VERSION 5.8 ;
BUSBITCHARS "[]" ;
DIVIDERCHAR "/" ;
UNITS
    DATABASE MICRONS 1000 ;
END UNITS

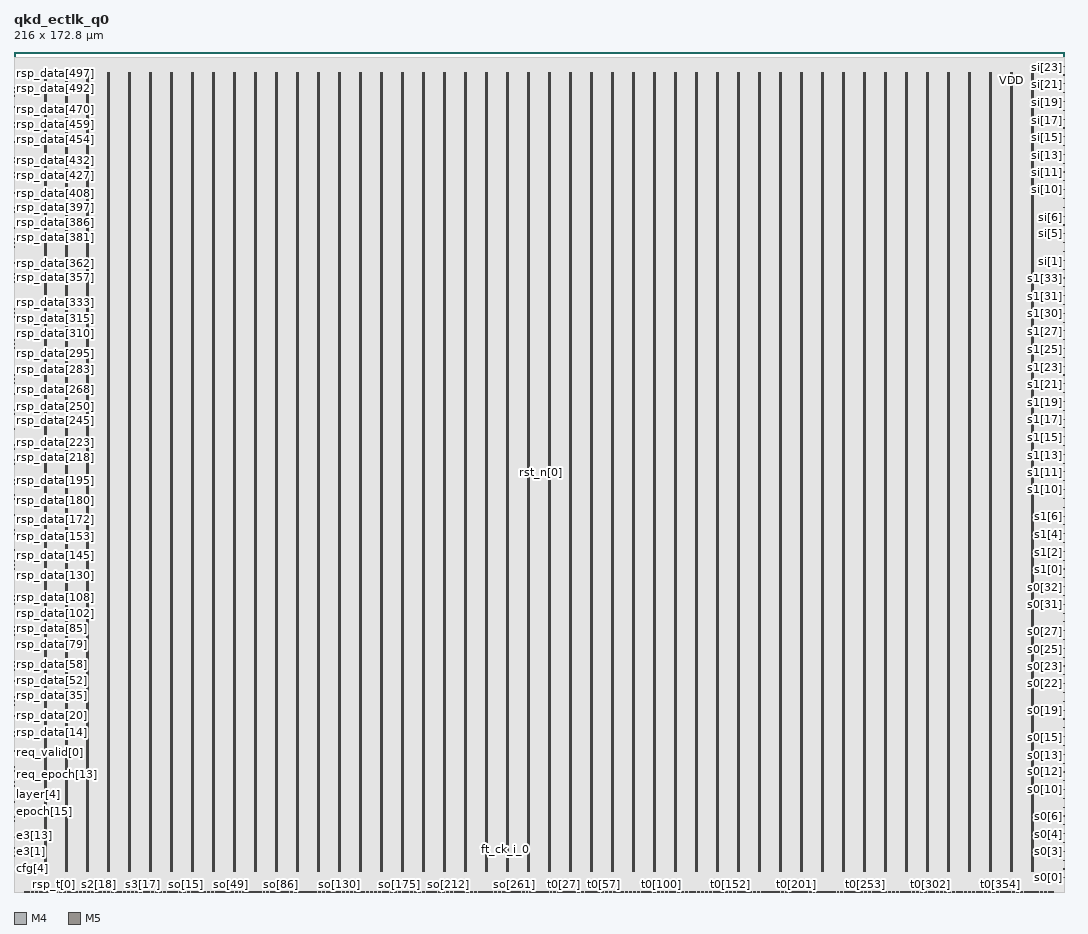
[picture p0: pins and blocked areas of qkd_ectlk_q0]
MACRO qkd_ectlk_q0
  FOREIGN qkd_ectlk_q0 0 0 ;
  CLASS BLOCK ;
  SIZE 216 BY 172.8 ;
  PIN cfg[0]
    DIRECTION INPUT ;
    USE SIGNAL ;
    PORT
      LAYER M4 ;
        RECT  0 2.124 0.192 2.148 ;
    END
  END cfg[0]
  PIN cfg[1]
    DIRECTION INPUT ;
    USE SIGNAL ;
    PORT
      LAYER M4 ;
        RECT  0 2.412 0.192 2.436 ;
    END
  END cfg[1]
  PIN cfg[2]
    DIRECTION INPUT ;
    USE SIGNAL ;
    PORT
      LAYER M4 ;
        RECT  0 2.7 0.192 2.724 ;
    END
  END cfg[2]
  PIN cfg[3]
    DIRECTION INPUT ;
    USE SIGNAL ;
    PORT
      LAYER M4 ;
        RECT  0 2.94 0.192 2.964 ;
    END
  END cfg[3]
  PIN cfg[4]
    DIRECTION INPUT ;
    USE SIGNAL ;
    PORT
      LAYER M4 ;
        RECT  0 3.228 0.192 3.252 ;
    END
  END cfg[4]
  PIN ck[0]
    DIRECTION INPUT ;
    USE SIGNAL ;
    PORT
      LAYER M5 ;
        RECT  108 86.16 108.048 86.64 ;
    END
  END ck[0]
  PIN e2[0]
    DIRECTION OUTPUT ;
    USE SIGNAL ;
    PORT
      LAYER M4 ;
        RECT  0 3.516 0.192 3.54 ;
    END
  END e2[0]
  PIN e2[10]
    DIRECTION OUTPUT ;
    USE SIGNAL ;
    PORT
      LAYER M4 ;
        RECT  0 6.3 0.192 6.324 ;
    END
  END e2[10]
  PIN e2[11]
    DIRECTION OUTPUT ;
    USE SIGNAL ;
    PORT
      LAYER M4 ;
        RECT  0 6.54 0.192 6.564 ;
    END
  END e2[11]
  PIN e2[12]
    DIRECTION OUTPUT ;
    USE SIGNAL ;
    PORT
      LAYER M4 ;
        RECT  0 6.828 0.192 6.852 ;
    END
  END e2[12]
  PIN e2[13]
    DIRECTION OUTPUT ;
    USE SIGNAL ;
    PORT
      LAYER M4 ;
        RECT  0 7.116 0.192 7.14 ;
    END
  END e2[13]
  PIN e2[14]
    DIRECTION OUTPUT ;
    USE SIGNAL ;
    PORT
      LAYER M4 ;
        RECT  0 7.404 0.192 7.428 ;
    END
  END e2[14]
  PIN e2[15]
    DIRECTION OUTPUT ;
    USE SIGNAL ;
    PORT
      LAYER M4 ;
        RECT  0 7.692 0.192 7.716 ;
    END
  END e2[15]
  PIN e2[1]
    DIRECTION OUTPUT ;
    USE SIGNAL ;
    PORT
      LAYER M4 ;
        RECT  0 3.804 0.192 3.828 ;
    END
  END e2[1]
  PIN e2[2]
    DIRECTION OUTPUT ;
    USE SIGNAL ;
    PORT
      LAYER M4 ;
        RECT  0 4.044 0.192 4.068 ;
    END
  END e2[2]
  PIN e2[3]
    DIRECTION OUTPUT ;
    USE SIGNAL ;
    PORT
      LAYER M4 ;
        RECT  0 4.332 0.192 4.356 ;
    END
  END e2[3]
  PIN e2[4]
    DIRECTION OUTPUT ;
    USE SIGNAL ;
    PORT
      LAYER M4 ;
        RECT  0 4.62 0.192 4.644 ;
    END
  END e2[4]
  PIN e2[5]
    DIRECTION OUTPUT ;
    USE SIGNAL ;
    PORT
      LAYER M4 ;
        RECT  0 4.908 0.192 4.932 ;
    END
  END e2[5]
  PIN e2[6]
    DIRECTION OUTPUT ;
    USE SIGNAL ;
    PORT
      LAYER M4 ;
        RECT  0 5.196 0.192 5.22 ;
    END
  END e2[6]
  PIN e2[7]
    DIRECTION OUTPUT ;
    USE SIGNAL ;
    PORT
      LAYER M4 ;
        RECT  0 5.436 0.192 5.46 ;
    END
  END e2[7]
  PIN e2[8]
    DIRECTION OUTPUT ;
    USE SIGNAL ;
    PORT
      LAYER M4 ;
        RECT  0 5.724 0.192 5.748 ;
    END
  END e2[8]
  PIN e2[9]
    DIRECTION OUTPUT ;
    USE SIGNAL ;
    PORT
      LAYER M4 ;
        RECT  0 6.012 0.192 6.036 ;
    END
  END e2[9]
  PIN e3[0]
    DIRECTION OUTPUT ;
    USE SIGNAL ;
    PORT
      LAYER M4 ;
        RECT  0 7.932 0.192 7.956 ;
    END
  END e3[0]
  PIN e3[10]
    DIRECTION OUTPUT ;
    USE SIGNAL ;
    PORT
      LAYER M4 ;
        RECT  0 10.716 0.192 10.74 ;
    END
  END e3[10]
  PIN e3[11]
    DIRECTION OUTPUT ;
    USE SIGNAL ;
    PORT
      LAYER M4 ;
        RECT  0 11.004 0.192 11.028 ;
    END
  END e3[11]
  PIN e3[12]
    DIRECTION OUTPUT ;
    USE SIGNAL ;
    PORT
      LAYER M4 ;
        RECT  0 11.292 0.192 11.316 ;
    END
  END e3[12]
  PIN e3[13]
    DIRECTION OUTPUT ;
    USE SIGNAL ;
    PORT
      LAYER M4 ;
        RECT  0 11.532 0.192 11.556 ;
    END
  END e3[13]
  PIN e3[14]
    DIRECTION OUTPUT ;
    USE SIGNAL ;
    PORT
      LAYER M4 ;
        RECT  0 11.82 0.192 11.844 ;
    END
  END e3[14]
  PIN e3[15]
    DIRECTION OUTPUT ;
    USE SIGNAL ;
    PORT
      LAYER M4 ;
        RECT  0 12.108 0.192 12.132 ;
    END
  END e3[15]
  PIN e3[1]
    DIRECTION OUTPUT ;
    USE SIGNAL ;
    PORT
      LAYER M4 ;
        RECT  0 8.22 0.192 8.244 ;
    END
  END e3[1]
  PIN e3[2]
    DIRECTION OUTPUT ;
    USE SIGNAL ;
    PORT
      LAYER M4 ;
        RECT  0 8.508 0.192 8.532 ;
    END
  END e3[2]
  PIN e3[3]
    DIRECTION OUTPUT ;
    USE SIGNAL ;
    PORT
      LAYER M4 ;
        RECT  0 8.796 0.192 8.82 ;
    END
  END e3[3]
  PIN e3[4]
    DIRECTION OUTPUT ;
    USE SIGNAL ;
    PORT
      LAYER M4 ;
        RECT  0 9.036 0.192 9.06 ;
    END
  END e3[4]
  PIN e3[5]
    DIRECTION OUTPUT ;
    USE SIGNAL ;
    PORT
      LAYER M4 ;
        RECT  0 9.324 0.192 9.348 ;
    END
  END e3[5]
  PIN e3[6]
    DIRECTION OUTPUT ;
    USE SIGNAL ;
    PORT
      LAYER M4 ;
        RECT  0 9.612 0.192 9.636 ;
    END
  END e3[6]
  PIN e3[7]
    DIRECTION OUTPUT ;
    USE SIGNAL ;
    PORT
      LAYER M4 ;
        RECT  0 9.9 0.192 9.924 ;
    END
  END e3[7]
  PIN e3[8]
    DIRECTION OUTPUT ;
    USE SIGNAL ;
    PORT
      LAYER M4 ;
        RECT  0 10.188 0.192 10.212 ;
    END
  END e3[8]
  PIN e3[9]
    DIRECTION OUTPUT ;
    USE SIGNAL ;
    PORT
      LAYER M4 ;
        RECT  0 10.428 0.192 10.452 ;
    END
  END e3[9]
  PIN epoch[0]
    DIRECTION INPUT ;
    USE SIGNAL ;
    PORT
      LAYER M4 ;
        RECT  0 12.396 0.192 12.42 ;
    END
  END epoch[0]
  PIN epoch[10]
    DIRECTION INPUT ;
    USE SIGNAL ;
    PORT
      LAYER M4 ;
        RECT  0 15.132 0.192 15.156 ;
    END
  END epoch[10]
  PIN epoch[11]
    DIRECTION INPUT ;
    USE SIGNAL ;
    PORT
      LAYER M4 ;
        RECT  0 15.42 0.192 15.444 ;
    END
  END epoch[11]
  PIN epoch[12]
    DIRECTION INPUT ;
    USE SIGNAL ;
    PORT
      LAYER M4 ;
        RECT  0 15.708 0.192 15.732 ;
    END
  END epoch[12]
  PIN epoch[13]
    DIRECTION INPUT ;
    USE SIGNAL ;
    PORT
      LAYER M4 ;
        RECT  0 15.996 0.192 16.02 ;
    END
  END epoch[13]
  PIN epoch[14]
    DIRECTION INPUT ;
    USE SIGNAL ;
    PORT
      LAYER M4 ;
        RECT  0 16.284 0.192 16.308 ;
    END
  END epoch[14]
  PIN epoch[15]
    DIRECTION INPUT ;
    USE SIGNAL ;
    PORT
      LAYER M4 ;
        RECT  0 16.524 0.192 16.548 ;
    END
  END epoch[15]
  PIN epoch[1]
    DIRECTION INPUT ;
    USE SIGNAL ;
    PORT
      LAYER M4 ;
        RECT  0 12.636 0.192 12.66 ;
    END
  END epoch[1]
  PIN epoch[2]
    DIRECTION INPUT ;
    USE SIGNAL ;
    PORT
      LAYER M4 ;
        RECT  0 12.924 0.192 12.948 ;
    END
  END epoch[2]
  PIN epoch[3]
    DIRECTION INPUT ;
    USE SIGNAL ;
    PORT
      LAYER M4 ;
        RECT  0 13.212 0.192 13.236 ;
    END
  END epoch[3]
  PIN epoch[4]
    DIRECTION INPUT ;
    USE SIGNAL ;
    PORT
      LAYER M4 ;
        RECT  0 13.5 0.192 13.524 ;
    END
  END epoch[4]
  PIN epoch[5]
    DIRECTION INPUT ;
    USE SIGNAL ;
    PORT
      LAYER M4 ;
        RECT  0 13.788 0.192 13.812 ;
    END
  END epoch[5]
  PIN epoch[6]
    DIRECTION INPUT ;
    USE SIGNAL ;
    PORT
      LAYER M4 ;
        RECT  0 14.028 0.192 14.052 ;
    END
  END epoch[6]
  PIN epoch[7]
    DIRECTION INPUT ;
    USE SIGNAL ;
    PORT
      LAYER M4 ;
        RECT  0 14.316 0.192 14.34 ;
    END
  END epoch[7]
  PIN epoch[8]
    DIRECTION INPUT ;
    USE SIGNAL ;
    PORT
      LAYER M4 ;
        RECT  0 14.604 0.192 14.628 ;
    END
  END epoch[8]
  PIN epoch[9]
    DIRECTION INPUT ;
    USE SIGNAL ;
    PORT
      LAYER M4 ;
        RECT  0 14.892 0.192 14.916 ;
    END
  END epoch[9]
  PIN fault[0]
    DIRECTION OUTPUT ;
    USE SIGNAL ;
    PORT
      LAYER M4 ;
        RECT  0 16.812 0.192 16.836 ;
    END
  END fault[0]
  PIN ft_ck_i_0
    DIRECTION INPUT ;
    USE SIGNAL ;
    PORT
      LAYER M5 ;
        RECT  101.04 8.535 101.088 9.015 ;
    END
  END ft_ck_i_0
  PIN ft_ck_o_0
    DIRECTION OUTPUT ;
    USE SIGNAL ;
    PORT
      LAYER M5 ;
        RECT  104.88 8.535 104.928 9.015 ;
    END
  END ft_ck_o_0
  PIN kgo[0]
    DIRECTION INPUT ;
    USE SIGNAL ;
    PORT
      LAYER M4 ;
        RECT  0 17.1 0.192 17.124 ;
    END
  END kgo[0]
  PIN layer[0]
    DIRECTION INPUT ;
    USE SIGNAL ;
    PORT
      LAYER M4 ;
        RECT  0 17.388 0.192 17.412 ;
    END
  END layer[0]
  PIN layer[1]
    DIRECTION INPUT ;
    USE SIGNAL ;
    PORT
      LAYER M4 ;
        RECT  0 17.628 0.192 17.652 ;
    END
  END layer[1]
  PIN layer[2]
    DIRECTION INPUT ;
    USE SIGNAL ;
    PORT
      LAYER M4 ;
        RECT  0 17.916 0.192 17.94 ;
    END
  END layer[2]
  PIN layer[3]
    DIRECTION INPUT ;
    USE SIGNAL ;
    PORT
      LAYER M4 ;
        RECT  0 18.204 0.192 18.228 ;
    END
  END layer[3]
  PIN layer[4]
    DIRECTION INPUT ;
    USE SIGNAL ;
    PORT
      LAYER M4 ;
        RECT  0 18.492 0.192 18.516 ;
    END
  END layer[4]
  PIN layer[5]
    DIRECTION INPUT ;
    USE SIGNAL ;
    PORT
      LAYER M4 ;
        RECT  0 18.78 0.192 18.804 ;
    END
  END layer[5]
  PIN req_epoch[0]
    DIRECTION OUTPUT ;
    USE SIGNAL ;
    PORT
      LAYER M4 ;
        RECT  0 19.02 0.192 19.044 ;
    END
  END req_epoch[0]
  PIN req_epoch[10]
    DIRECTION OUTPUT ;
    USE SIGNAL ;
    PORT
      LAYER M4 ;
        RECT  0 21.804 0.192 21.828 ;
    END
  END req_epoch[10]
  PIN req_epoch[11]
    DIRECTION OUTPUT ;
    USE SIGNAL ;
    PORT
      LAYER M4 ;
        RECT  0 22.092 0.192 22.116 ;
    END
  END req_epoch[11]
  PIN req_epoch[12]
    DIRECTION OUTPUT ;
    USE SIGNAL ;
    PORT
      LAYER M4 ;
        RECT  0 22.38 0.192 22.404 ;
    END
  END req_epoch[12]
  PIN req_epoch[13]
    DIRECTION OUTPUT ;
    USE SIGNAL ;
    PORT
      LAYER M4 ;
        RECT  0 22.62 0.192 22.644 ;
    END
  END req_epoch[13]
  PIN req_epoch[14]
    DIRECTION OUTPUT ;
    USE SIGNAL ;
    PORT
      LAYER M4 ;
        RECT  0 22.908 0.192 22.932 ;
    END
  END req_epoch[14]
  PIN req_epoch[15]
    DIRECTION OUTPUT ;
    USE SIGNAL ;
    PORT
      LAYER M4 ;
        RECT  0 23.196 0.192 23.22 ;
    END
  END req_epoch[15]
  PIN req_epoch[1]
    DIRECTION OUTPUT ;
    USE SIGNAL ;
    PORT
      LAYER M4 ;
        RECT  0 19.308 0.192 19.332 ;
    END
  END req_epoch[1]
  PIN req_epoch[2]
    DIRECTION OUTPUT ;
    USE SIGNAL ;
    PORT
      LAYER M4 ;
        RECT  0 19.596 0.192 19.62 ;
    END
  END req_epoch[2]
  PIN req_epoch[3]
    DIRECTION OUTPUT ;
    USE SIGNAL ;
    PORT
      LAYER M4 ;
        RECT  0 19.884 0.192 19.908 ;
    END
  END req_epoch[3]
  PIN req_epoch[4]
    DIRECTION OUTPUT ;
    USE SIGNAL ;
    PORT
      LAYER M4 ;
        RECT  0 20.124 0.192 20.148 ;
    END
  END req_epoch[4]
  PIN req_epoch[5]
    DIRECTION OUTPUT ;
    USE SIGNAL ;
    PORT
      LAYER M4 ;
        RECT  0 20.412 0.192 20.436 ;
    END
  END req_epoch[5]
  PIN req_epoch[6]
    DIRECTION OUTPUT ;
    USE SIGNAL ;
    PORT
      LAYER M4 ;
        RECT  0 20.7 0.192 20.724 ;
    END
  END req_epoch[6]
  PIN req_epoch[7]
    DIRECTION OUTPUT ;
    USE SIGNAL ;
    PORT
      LAYER M4 ;
        RECT  0 20.988 0.192 21.012 ;
    END
  END req_epoch[7]
  PIN req_epoch[8]
    DIRECTION OUTPUT ;
    USE SIGNAL ;
    PORT
      LAYER M4 ;
        RECT  0 21.228 0.192 21.252 ;
    END
  END req_epoch[8]
  PIN req_epoch[9]
    DIRECTION OUTPUT ;
    USE SIGNAL ;
    PORT
      LAYER M4 ;
        RECT  0 21.516 0.192 21.54 ;
    END
  END req_epoch[9]
  PIN req_layer[0]
    DIRECTION OUTPUT ;
    USE SIGNAL ;
    PORT
      LAYER M4 ;
        RECT  0 23.484 0.192 23.508 ;
    END
  END req_layer[0]
  PIN req_layer[1]
    DIRECTION OUTPUT ;
    USE SIGNAL ;
    PORT
      LAYER M4 ;
        RECT  0 23.724 0.192 23.748 ;
    END
  END req_layer[1]
  PIN req_layer[2]
    DIRECTION OUTPUT ;
    USE SIGNAL ;
    PORT
      LAYER M4 ;
        RECT  0 24.012 0.192 24.036 ;
    END
  END req_layer[2]
  PIN req_layer[3]
    DIRECTION OUTPUT ;
    USE SIGNAL ;
    PORT
      LAYER M4 ;
        RECT  0 24.3 0.192 24.324 ;
    END
  END req_layer[3]
  PIN req_layer[4]
    DIRECTION OUTPUT ;
    USE SIGNAL ;
    PORT
      LAYER M4 ;
        RECT  0 24.588 0.192 24.612 ;
    END
  END req_layer[4]
  PIN req_layer[5]
    DIRECTION OUTPUT ;
    USE SIGNAL ;
    PORT
      LAYER M4 ;
        RECT  0 24.876 0.192 24.9 ;
    END
  END req_layer[5]
  PIN req_t[0]
    DIRECTION OUTPUT ;
    USE SIGNAL ;
    PORT
      LAYER M4 ;
        RECT  0 25.116 0.192 25.14 ;
    END
  END req_t[0]
  PIN req_t[10]
    DIRECTION OUTPUT ;
    USE SIGNAL ;
    PORT
      LAYER M4 ;
        RECT  0 27.9 0.192 27.924 ;
    END
  END req_t[10]
  PIN req_t[11]
    DIRECTION OUTPUT ;
    USE SIGNAL ;
    PORT
      LAYER M4 ;
        RECT  0 28.188 0.192 28.212 ;
    END
  END req_t[11]
  PIN req_t[12]
    DIRECTION OUTPUT ;
    USE SIGNAL ;
    PORT
      LAYER M4 ;
        RECT  0 28.476 0.192 28.5 ;
    END
  END req_t[12]
  PIN req_t[1]
    DIRECTION OUTPUT ;
    USE SIGNAL ;
    PORT
      LAYER M4 ;
        RECT  0 25.404 0.192 25.428 ;
    END
  END req_t[1]
  PIN req_t[2]
    DIRECTION OUTPUT ;
    USE SIGNAL ;
    PORT
      LAYER M4 ;
        RECT  0 25.692 0.192 25.716 ;
    END
  END req_t[2]
  PIN req_t[3]
    DIRECTION OUTPUT ;
    USE SIGNAL ;
    PORT
      LAYER M4 ;
        RECT  0 25.98 0.192 26.004 ;
    END
  END req_t[3]
  PIN req_t[4]
    DIRECTION OUTPUT ;
    USE SIGNAL ;
    PORT
      LAYER M4 ;
        RECT  0 26.22 0.192 26.244 ;
    END
  END req_t[4]
  PIN req_t[5]
    DIRECTION OUTPUT ;
    USE SIGNAL ;
    PORT
      LAYER M4 ;
        RECT  0 26.508 0.192 26.532 ;
    END
  END req_t[5]
  PIN req_t[6]
    DIRECTION OUTPUT ;
    USE SIGNAL ;
    PORT
      LAYER M4 ;
        RECT  0 26.796 0.192 26.82 ;
    END
  END req_t[6]
  PIN req_t[7]
    DIRECTION OUTPUT ;
    USE SIGNAL ;
    PORT
      LAYER M4 ;
        RECT  0 27.084 0.192 27.108 ;
    END
  END req_t[7]
  PIN req_t[8]
    DIRECTION OUTPUT ;
    USE SIGNAL ;
    PORT
      LAYER M4 ;
        RECT  0 27.372 0.192 27.396 ;
    END
  END req_t[8]
  PIN req_t[9]
    DIRECTION OUTPUT ;
    USE SIGNAL ;
    PORT
      LAYER M4 ;
        RECT  0 27.612 0.192 27.636 ;
    END
  END req_t[9]
  PIN req_valid[0]
    DIRECTION OUTPUT ;
    USE SIGNAL ;
    PORT
      LAYER M4 ;
        RECT  0 28.716 0.192 28.74 ;
    END
  END req_valid[0]
  PIN rsp_data[0]
    DIRECTION INPUT ;
    USE SIGNAL ;
    PORT
      LAYER M4 ;
        RECT  0 29.004 0.192 29.028 ;
    END
  END rsp_data[0]
  PIN rsp_data[100]
    DIRECTION INPUT ;
    USE SIGNAL ;
    PORT
      LAYER M4 ;
        RECT  0 56.748 0.192 56.772 ;
    END
  END rsp_data[100]
  PIN rsp_data[101]
    DIRECTION INPUT ;
    USE SIGNAL ;
    PORT
      LAYER M4 ;
        RECT  0 56.988 0.192 57.012 ;
    END
  END rsp_data[101]
  PIN rsp_data[102]
    DIRECTION INPUT ;
    USE SIGNAL ;
    PORT
      LAYER M4 ;
        RECT  0 57.276 0.192 57.3 ;
    END
  END rsp_data[102]
  PIN rsp_data[103]
    DIRECTION INPUT ;
    USE SIGNAL ;
    PORT
      LAYER M4 ;
        RECT  0 57.564 0.192 57.588 ;
    END
  END rsp_data[103]
  PIN rsp_data[104]
    DIRECTION INPUT ;
    USE SIGNAL ;
    PORT
      LAYER M4 ;
        RECT  0 57.852 0.192 57.876 ;
    END
  END rsp_data[104]
  PIN rsp_data[105]
    DIRECTION INPUT ;
    USE SIGNAL ;
    PORT
      LAYER M4 ;
        RECT  0 58.14 0.192 58.164 ;
    END
  END rsp_data[105]
  PIN rsp_data[106]
    DIRECTION INPUT ;
    USE SIGNAL ;
    PORT
      LAYER M4 ;
        RECT  0 58.38 0.192 58.404 ;
    END
  END rsp_data[106]
  PIN rsp_data[107]
    DIRECTION INPUT ;
    USE SIGNAL ;
    PORT
      LAYER M4 ;
        RECT  0 58.668 0.192 58.692 ;
    END
  END rsp_data[107]
  PIN rsp_data[108]
    DIRECTION INPUT ;
    USE SIGNAL ;
    PORT
      LAYER M4 ;
        RECT  0 58.956 0.192 58.98 ;
    END
  END rsp_data[108]
  PIN rsp_data[109]
    DIRECTION INPUT ;
    USE SIGNAL ;
    PORT
      LAYER M4 ;
        RECT  0 59.244 0.192 59.268 ;
    END
  END rsp_data[109]
  PIN rsp_data[10]
    DIRECTION INPUT ;
    USE SIGNAL ;
    PORT
      LAYER M4 ;
        RECT  0 31.788 0.192 31.812 ;
    END
  END rsp_data[10]
  PIN rsp_data[110]
    DIRECTION INPUT ;
    USE SIGNAL ;
    PORT
      LAYER M4 ;
        RECT  0 59.484 0.192 59.508 ;
    END
  END rsp_data[110]
  PIN rsp_data[111]
    DIRECTION INPUT ;
    USE SIGNAL ;
    PORT
      LAYER M4 ;
        RECT  0 59.772 0.192 59.796 ;
    END
  END rsp_data[111]
  PIN rsp_data[112]
    DIRECTION INPUT ;
    USE SIGNAL ;
    PORT
      LAYER M4 ;
        RECT  0 60.06 0.192 60.084 ;
    END
  END rsp_data[112]
  PIN rsp_data[113]
    DIRECTION INPUT ;
    USE SIGNAL ;
    PORT
      LAYER M4 ;
        RECT  0 60.348 0.192 60.372 ;
    END
  END rsp_data[113]
  PIN rsp_data[114]
    DIRECTION INPUT ;
    USE SIGNAL ;
    PORT
      LAYER M4 ;
        RECT  0 60.588 0.192 60.612 ;
    END
  END rsp_data[114]
  PIN rsp_data[115]
    DIRECTION INPUT ;
    USE SIGNAL ;
    PORT
      LAYER M4 ;
        RECT  0 60.876 0.192 60.9 ;
    END
  END rsp_data[115]
  PIN rsp_data[116]
    DIRECTION INPUT ;
    USE SIGNAL ;
    PORT
      LAYER M4 ;
        RECT  0 61.164 0.192 61.188 ;
    END
  END rsp_data[116]
  PIN rsp_data[117]
    DIRECTION INPUT ;
    USE SIGNAL ;
    PORT
      LAYER M4 ;
        RECT  0 61.452 0.192 61.476 ;
    END
  END rsp_data[117]
  PIN rsp_data[118]
    DIRECTION INPUT ;
    USE SIGNAL ;
    PORT
      LAYER M4 ;
        RECT  0 61.74 0.192 61.764 ;
    END
  END rsp_data[118]
  PIN rsp_data[119]
    DIRECTION INPUT ;
    USE SIGNAL ;
    PORT
      LAYER M4 ;
        RECT  0 61.98 0.192 62.004 ;
    END
  END rsp_data[119]
  PIN rsp_data[11]
    DIRECTION INPUT ;
    USE SIGNAL ;
    PORT
      LAYER M4 ;
        RECT  0 32.076 0.192 32.1 ;
    END
  END rsp_data[11]
  PIN rsp_data[120]
    DIRECTION INPUT ;
    USE SIGNAL ;
    PORT
      LAYER M4 ;
        RECT  0 62.268 0.192 62.292 ;
    END
  END rsp_data[120]
  PIN rsp_data[121]
    DIRECTION INPUT ;
    USE SIGNAL ;
    PORT
      LAYER M4 ;
        RECT  0 62.556 0.192 62.58 ;
    END
  END rsp_data[121]
  PIN rsp_data[122]
    DIRECTION INPUT ;
    USE SIGNAL ;
    PORT
      LAYER M4 ;
        RECT  0 62.844 0.192 62.868 ;
    END
  END rsp_data[122]
  PIN rsp_data[123]
    DIRECTION INPUT ;
    USE SIGNAL ;
    PORT
      LAYER M4 ;
        RECT  0 63.084 0.192 63.108 ;
    END
  END rsp_data[123]
  PIN rsp_data[124]
    DIRECTION INPUT ;
    USE SIGNAL ;
    PORT
      LAYER M4 ;
        RECT  0 63.372 0.192 63.396 ;
    END
  END rsp_data[124]
  PIN rsp_data[125]
    DIRECTION INPUT ;
    USE SIGNAL ;
    PORT
      LAYER M4 ;
        RECT  0 63.66 0.192 63.684 ;
    END
  END rsp_data[125]
  PIN rsp_data[126]
    DIRECTION INPUT ;
    USE SIGNAL ;
    PORT
      LAYER M4 ;
        RECT  0 63.948 0.192 63.972 ;
    END
  END rsp_data[126]
  PIN rsp_data[127]
    DIRECTION INPUT ;
    USE SIGNAL ;
    PORT
      LAYER M4 ;
        RECT  0 64.236 0.192 64.26 ;
    END
  END rsp_data[127]
  PIN rsp_data[128]
    DIRECTION INPUT ;
    USE SIGNAL ;
    PORT
      LAYER M4 ;
        RECT  0 64.476 0.192 64.5 ;
    END
  END rsp_data[128]
  PIN rsp_data[129]
    DIRECTION INPUT ;
    USE SIGNAL ;
    PORT
      LAYER M4 ;
        RECT  0 64.764 0.192 64.788 ;
    END
  END rsp_data[129]
  PIN rsp_data[12]
    DIRECTION INPUT ;
    USE SIGNAL ;
    PORT
      LAYER M4 ;
        RECT  0 32.316 0.192 32.34 ;
    END
  END rsp_data[12]
  PIN rsp_data[130]
    DIRECTION INPUT ;
    USE SIGNAL ;
    PORT
      LAYER M4 ;
        RECT  0 65.052 0.192 65.076 ;
    END
  END rsp_data[130]
  PIN rsp_data[131]
    DIRECTION INPUT ;
    USE SIGNAL ;
    PORT
      LAYER M4 ;
        RECT  0 65.34 0.192 65.364 ;
    END
  END rsp_data[131]
  PIN rsp_data[132]
    DIRECTION INPUT ;
    USE SIGNAL ;
    PORT
      LAYER M4 ;
        RECT  0 65.58 0.192 65.604 ;
    END
  END rsp_data[132]
  PIN rsp_data[133]
    DIRECTION INPUT ;
    USE SIGNAL ;
    PORT
      LAYER M4 ;
        RECT  0 65.868 0.192 65.892 ;
    END
  END rsp_data[133]
  PIN rsp_data[134]
    DIRECTION INPUT ;
    USE SIGNAL ;
    PORT
      LAYER M4 ;
        RECT  0 66.156 0.192 66.18 ;
    END
  END rsp_data[134]
  PIN rsp_data[135]
    DIRECTION INPUT ;
    USE SIGNAL ;
    PORT
      LAYER M4 ;
        RECT  0 66.444 0.192 66.468 ;
    END
  END rsp_data[135]
  PIN rsp_data[136]
    DIRECTION INPUT ;
    USE SIGNAL ;
    PORT
      LAYER M4 ;
        RECT  0 66.732 0.192 66.756 ;
    END
  END rsp_data[136]
  PIN rsp_data[137]
    DIRECTION INPUT ;
    USE SIGNAL ;
    PORT
      LAYER M4 ;
        RECT  0 66.972 0.192 66.996 ;
    END
  END rsp_data[137]
  PIN rsp_data[138]
    DIRECTION INPUT ;
    USE SIGNAL ;
    PORT
      LAYER M4 ;
        RECT  0 67.26 0.192 67.284 ;
    END
  END rsp_data[138]
  PIN rsp_data[139]
    DIRECTION INPUT ;
    USE SIGNAL ;
    PORT
      LAYER M4 ;
        RECT  0 67.548 0.192 67.572 ;
    END
  END rsp_data[139]
  PIN rsp_data[13]
    DIRECTION INPUT ;
    USE SIGNAL ;
    PORT
      LAYER M4 ;
        RECT  0 32.604 0.192 32.628 ;
    END
  END rsp_data[13]
  PIN rsp_data[140]
    DIRECTION INPUT ;
    USE SIGNAL ;
    PORT
      LAYER M4 ;
        RECT  0 67.836 0.192 67.86 ;
    END
  END rsp_data[140]
  PIN rsp_data[141]
    DIRECTION INPUT ;
    USE SIGNAL ;
    PORT
      LAYER M4 ;
        RECT  0 68.076 0.192 68.1 ;
    END
  END rsp_data[141]
  PIN rsp_data[142]
    DIRECTION INPUT ;
    USE SIGNAL ;
    PORT
      LAYER M4 ;
        RECT  0 68.364 0.192 68.388 ;
    END
  END rsp_data[142]
  PIN rsp_data[143]
    DIRECTION INPUT ;
    USE SIGNAL ;
    PORT
      LAYER M4 ;
        RECT  0 68.652 0.192 68.676 ;
    END
  END rsp_data[143]
  PIN rsp_data[144]
    DIRECTION INPUT ;
    USE SIGNAL ;
    PORT
      LAYER M4 ;
        RECT  0 68.94 0.192 68.964 ;
    END
  END rsp_data[144]
  PIN rsp_data[145]
    DIRECTION INPUT ;
    USE SIGNAL ;
    PORT
      LAYER M4 ;
        RECT  0 69.18 0.192 69.204 ;
    END
  END rsp_data[145]
  PIN rsp_data[146]
    DIRECTION INPUT ;
    USE SIGNAL ;
    PORT
      LAYER M4 ;
        RECT  0 69.468 0.192 69.492 ;
    END
  END rsp_data[146]
  PIN rsp_data[147]
    DIRECTION INPUT ;
    USE SIGNAL ;
    PORT
      LAYER M4 ;
        RECT  0 69.756 0.192 69.78 ;
    END
  END rsp_data[147]
  PIN rsp_data[148]
    DIRECTION INPUT ;
    USE SIGNAL ;
    PORT
      LAYER M4 ;
        RECT  0 70.044 0.192 70.068 ;
    END
  END rsp_data[148]
  PIN rsp_data[149]
    DIRECTION INPUT ;
    USE SIGNAL ;
    PORT
      LAYER M4 ;
        RECT  0 70.332 0.192 70.356 ;
    END
  END rsp_data[149]
  PIN rsp_data[14]
    DIRECTION INPUT ;
    USE SIGNAL ;
    PORT
      LAYER M4 ;
        RECT  0 32.892 0.192 32.916 ;
    END
  END rsp_data[14]
  PIN rsp_data[150]
    DIRECTION INPUT ;
    USE SIGNAL ;
    PORT
      LAYER M4 ;
        RECT  0 70.572 0.192 70.596 ;
    END
  END rsp_data[150]
  PIN rsp_data[151]
    DIRECTION INPUT ;
    USE SIGNAL ;
    PORT
      LAYER M4 ;
        RECT  0 70.86 0.192 70.884 ;
    END
  END rsp_data[151]
  PIN rsp_data[152]
    DIRECTION INPUT ;
    USE SIGNAL ;
    PORT
      LAYER M4 ;
        RECT  0 71.148 0.192 71.172 ;
    END
  END rsp_data[152]
  PIN rsp_data[153]
    DIRECTION INPUT ;
    USE SIGNAL ;
    PORT
      LAYER M4 ;
        RECT  0 71.436 0.192 71.46 ;
    END
  END rsp_data[153]
  PIN rsp_data[154]
    DIRECTION INPUT ;
    USE SIGNAL ;
    PORT
      LAYER M4 ;
        RECT  0 71.676 0.192 71.7 ;
    END
  END rsp_data[154]
  PIN rsp_data[155]
    DIRECTION INPUT ;
    USE SIGNAL ;
    PORT
      LAYER M4 ;
        RECT  0 71.964 0.192 71.988 ;
    END
  END rsp_data[155]
  PIN rsp_data[156]
    DIRECTION INPUT ;
    USE SIGNAL ;
    PORT
      LAYER M4 ;
        RECT  0 72.252 0.192 72.276 ;
    END
  END rsp_data[156]
  PIN rsp_data[157]
    DIRECTION INPUT ;
    USE SIGNAL ;
    PORT
      LAYER M4 ;
        RECT  0 72.54 0.192 72.564 ;
    END
  END rsp_data[157]
  PIN rsp_data[158]
    DIRECTION INPUT ;
    USE SIGNAL ;
    PORT
      LAYER M4 ;
        RECT  0 72.828 0.192 72.852 ;
    END
  END rsp_data[158]
  PIN rsp_data[159]
    DIRECTION INPUT ;
    USE SIGNAL ;
    PORT
      LAYER M4 ;
        RECT  0 73.068 0.192 73.092 ;
    END
  END rsp_data[159]
  PIN rsp_data[15]
    DIRECTION INPUT ;
    USE SIGNAL ;
    PORT
      LAYER M4 ;
        RECT  0 33.18 0.192 33.204 ;
    END
  END rsp_data[15]
  PIN rsp_data[160]
    DIRECTION INPUT ;
    USE SIGNAL ;
    PORT
      LAYER M4 ;
        RECT  0 73.356 0.192 73.38 ;
    END
  END rsp_data[160]
  PIN rsp_data[161]
    DIRECTION INPUT ;
    USE SIGNAL ;
    PORT
      LAYER M4 ;
        RECT  0 73.644 0.192 73.668 ;
    END
  END rsp_data[161]
  PIN rsp_data[162]
    DIRECTION INPUT ;
    USE SIGNAL ;
    PORT
      LAYER M4 ;
        RECT  0 73.932 0.192 73.956 ;
    END
  END rsp_data[162]
  PIN rsp_data[163]
    DIRECTION INPUT ;
    USE SIGNAL ;
    PORT
      LAYER M4 ;
        RECT  0 74.172 0.192 74.196 ;
    END
  END rsp_data[163]
  PIN rsp_data[164]
    DIRECTION INPUT ;
    USE SIGNAL ;
    PORT
      LAYER M4 ;
        RECT  0 74.46 0.192 74.484 ;
    END
  END rsp_data[164]
  PIN rsp_data[165]
    DIRECTION INPUT ;
    USE SIGNAL ;
    PORT
      LAYER M4 ;
        RECT  0 74.748 0.192 74.772 ;
    END
  END rsp_data[165]
  PIN rsp_data[166]
    DIRECTION INPUT ;
    USE SIGNAL ;
    PORT
      LAYER M4 ;
        RECT  0 75.036 0.192 75.06 ;
    END
  END rsp_data[166]
  PIN rsp_data[167]
    DIRECTION INPUT ;
    USE SIGNAL ;
    PORT
      LAYER M4 ;
        RECT  0 75.324 0.192 75.348 ;
    END
  END rsp_data[167]
  PIN rsp_data[168]
    DIRECTION INPUT ;
    USE SIGNAL ;
    PORT
      LAYER M4 ;
        RECT  0 75.564 0.192 75.588 ;
    END
  END rsp_data[168]
  PIN rsp_data[169]
    DIRECTION INPUT ;
    USE SIGNAL ;
    PORT
      LAYER M4 ;
        RECT  0 75.852 0.192 75.876 ;
    END
  END rsp_data[169]
  PIN rsp_data[16]
    DIRECTION INPUT ;
    USE SIGNAL ;
    PORT
      LAYER M4 ;
        RECT  0 33.468 0.192 33.492 ;
    END
  END rsp_data[16]
  PIN rsp_data[170]
    DIRECTION INPUT ;
    USE SIGNAL ;
    PORT
      LAYER M4 ;
        RECT  0 76.14 0.192 76.164 ;
    END
  END rsp_data[170]
  PIN rsp_data[171]
    DIRECTION INPUT ;
    USE SIGNAL ;
    PORT
      LAYER M4 ;
        RECT  0 76.428 0.192 76.452 ;
    END
  END rsp_data[171]
  PIN rsp_data[172]
    DIRECTION INPUT ;
    USE SIGNAL ;
    PORT
      LAYER M4 ;
        RECT  0 76.668 0.192 76.692 ;
    END
  END rsp_data[172]
  PIN rsp_data[173]
    DIRECTION INPUT ;
    USE SIGNAL ;
    PORT
      LAYER M4 ;
        RECT  0 76.956 0.192 76.98 ;
    END
  END rsp_data[173]
  PIN rsp_data[174]
    DIRECTION INPUT ;
    USE SIGNAL ;
    PORT
      LAYER M4 ;
        RECT  0 77.244 0.192 77.268 ;
    END
  END rsp_data[174]
  PIN rsp_data[175]
    DIRECTION INPUT ;
    USE SIGNAL ;
    PORT
      LAYER M4 ;
        RECT  0 77.532 0.192 77.556 ;
    END
  END rsp_data[175]
  PIN rsp_data[176]
    DIRECTION INPUT ;
    USE SIGNAL ;
    PORT
      LAYER M4 ;
        RECT  0 77.772 0.192 77.796 ;
    END
  END rsp_data[176]
  PIN rsp_data[177]
    DIRECTION INPUT ;
    USE SIGNAL ;
    PORT
      LAYER M4 ;
        RECT  0 78.06 0.192 78.084 ;
    END
  END rsp_data[177]
  PIN rsp_data[178]
    DIRECTION INPUT ;
    USE SIGNAL ;
    PORT
      LAYER M4 ;
        RECT  0 78.348 0.192 78.372 ;
    END
  END rsp_data[178]
  PIN rsp_data[179]
    DIRECTION INPUT ;
    USE SIGNAL ;
    PORT
      LAYER M4 ;
        RECT  0 78.636 0.192 78.66 ;
    END
  END rsp_data[179]
  PIN rsp_data[17]
    DIRECTION INPUT ;
    USE SIGNAL ;
    PORT
      LAYER M4 ;
        RECT  0 33.708 0.192 33.732 ;
    END
  END rsp_data[17]
  PIN rsp_data[180]
    DIRECTION INPUT ;
    USE SIGNAL ;
    PORT
      LAYER M4 ;
        RECT  0 78.924 0.192 78.948 ;
    END
  END rsp_data[180]
  PIN rsp_data[181]
    DIRECTION INPUT ;
    USE SIGNAL ;
    PORT
      LAYER M4 ;
        RECT  0 79.164 0.192 79.188 ;
    END
  END rsp_data[181]
  PIN rsp_data[182]
    DIRECTION INPUT ;
    USE SIGNAL ;
    PORT
      LAYER M4 ;
        RECT  0 79.452 0.192 79.476 ;
    END
  END rsp_data[182]
  PIN rsp_data[183]
    DIRECTION INPUT ;
    USE SIGNAL ;
    PORT
      LAYER M4 ;
        RECT  0 79.74 0.192 79.764 ;
    END
  END rsp_data[183]
  PIN rsp_data[184]
    DIRECTION INPUT ;
    USE SIGNAL ;
    PORT
      LAYER M4 ;
        RECT  0 80.028 0.192 80.052 ;
    END
  END rsp_data[184]
  PIN rsp_data[185]
    DIRECTION INPUT ;
    USE SIGNAL ;
    PORT
      LAYER M4 ;
        RECT  0 80.268 0.192 80.292 ;
    END
  END rsp_data[185]
  PIN rsp_data[186]
    DIRECTION INPUT ;
    USE SIGNAL ;
    PORT
      LAYER M4 ;
        RECT  0 80.556 0.192 80.58 ;
    END
  END rsp_data[186]
  PIN rsp_data[187]
    DIRECTION INPUT ;
    USE SIGNAL ;
    PORT
      LAYER M4 ;
        RECT  0 80.844 0.192 80.868 ;
    END
  END rsp_data[187]
  PIN rsp_data[188]
    DIRECTION INPUT ;
    USE SIGNAL ;
    PORT
      LAYER M4 ;
        RECT  0 81.132 0.192 81.156 ;
    END
  END rsp_data[188]
  PIN rsp_data[189]
    DIRECTION INPUT ;
    USE SIGNAL ;
    PORT
      LAYER M4 ;
        RECT  0 81.42 0.192 81.444 ;
    END
  END rsp_data[189]
  PIN rsp_data[18]
    DIRECTION INPUT ;
    USE SIGNAL ;
    PORT
      LAYER M4 ;
        RECT  0 33.996 0.192 34.02 ;
    END
  END rsp_data[18]
  PIN rsp_data[190]
    DIRECTION INPUT ;
    USE SIGNAL ;
    PORT
      LAYER M4 ;
        RECT  0 81.66 0.192 81.684 ;
    END
  END rsp_data[190]
  PIN rsp_data[191]
    DIRECTION INPUT ;
    USE SIGNAL ;
    PORT
      LAYER M4 ;
        RECT  0 81.948 0.192 81.972 ;
    END
  END rsp_data[191]
  PIN rsp_data[192]
    DIRECTION INPUT ;
    USE SIGNAL ;
    PORT
      LAYER M4 ;
        RECT  0 82.236 0.192 82.26 ;
    END
  END rsp_data[192]
  PIN rsp_data[193]
    DIRECTION INPUT ;
    USE SIGNAL ;
    PORT
      LAYER M4 ;
        RECT  0 82.524 0.192 82.548 ;
    END
  END rsp_data[193]
  PIN rsp_data[194]
    DIRECTION INPUT ;
    USE SIGNAL ;
    PORT
      LAYER M4 ;
        RECT  0 82.764 0.192 82.788 ;
    END
  END rsp_data[194]
  PIN rsp_data[195]
    DIRECTION INPUT ;
    USE SIGNAL ;
    PORT
      LAYER M4 ;
        RECT  0 83.052 0.192 83.076 ;
    END
  END rsp_data[195]
  PIN rsp_data[196]
    DIRECTION INPUT ;
    USE SIGNAL ;
    PORT
      LAYER M4 ;
        RECT  0 83.34 0.192 83.364 ;
    END
  END rsp_data[196]
  PIN rsp_data[197]
    DIRECTION INPUT ;
    USE SIGNAL ;
    PORT
      LAYER M4 ;
        RECT  0 83.628 0.192 83.652 ;
    END
  END rsp_data[197]
  PIN rsp_data[198]
    DIRECTION INPUT ;
    USE SIGNAL ;
    PORT
      LAYER M4 ;
        RECT  0 83.916 0.192 83.94 ;
    END
  END rsp_data[198]
  PIN rsp_data[199]
    DIRECTION INPUT ;
    USE SIGNAL ;
    PORT
      LAYER M4 ;
        RECT  0 84.156 0.192 84.18 ;
    END
  END rsp_data[199]
  PIN rsp_data[19]
    DIRECTION INPUT ;
    USE SIGNAL ;
    PORT
      LAYER M4 ;
        RECT  0 34.284 0.192 34.308 ;
    END
  END rsp_data[19]
  PIN rsp_data[1]
    DIRECTION INPUT ;
    USE SIGNAL ;
    PORT
      LAYER M4 ;
        RECT  0 29.292 0.192 29.316 ;
    END
  END rsp_data[1]
  PIN rsp_data[200]
    DIRECTION INPUT ;
    USE SIGNAL ;
    PORT
      LAYER M4 ;
        RECT  0 84.444 0.192 84.468 ;
    END
  END rsp_data[200]
  PIN rsp_data[201]
    DIRECTION INPUT ;
    USE SIGNAL ;
    PORT
      LAYER M4 ;
        RECT  0 84.732 0.192 84.756 ;
    END
  END rsp_data[201]
  PIN rsp_data[202]
    DIRECTION INPUT ;
    USE SIGNAL ;
    PORT
      LAYER M4 ;
        RECT  0 85.02 0.192 85.044 ;
    END
  END rsp_data[202]
  PIN rsp_data[203]
    DIRECTION INPUT ;
    USE SIGNAL ;
    PORT
      LAYER M4 ;
        RECT  0 85.26 0.192 85.284 ;
    END
  END rsp_data[203]
  PIN rsp_data[204]
    DIRECTION INPUT ;
    USE SIGNAL ;
    PORT
      LAYER M4 ;
        RECT  0 85.548 0.192 85.572 ;
    END
  END rsp_data[204]
  PIN rsp_data[205]
    DIRECTION INPUT ;
    USE SIGNAL ;
    PORT
      LAYER M4 ;
        RECT  0 85.836 0.192 85.86 ;
    END
  END rsp_data[205]
  PIN rsp_data[206]
    DIRECTION INPUT ;
    USE SIGNAL ;
    PORT
      LAYER M4 ;
        RECT  0 86.124 0.192 86.148 ;
    END
  END rsp_data[206]
  PIN rsp_data[207]
    DIRECTION INPUT ;
    USE SIGNAL ;
    PORT
      LAYER M4 ;
        RECT  0 86.412 0.192 86.436 ;
    END
  END rsp_data[207]
  PIN rsp_data[208]
    DIRECTION INPUT ;
    USE SIGNAL ;
    PORT
      LAYER M4 ;
        RECT  0 86.652 0.192 86.676 ;
    END
  END rsp_data[208]
  PIN rsp_data[209]
    DIRECTION INPUT ;
    USE SIGNAL ;
    PORT
      LAYER M4 ;
        RECT  0 86.94 0.192 86.964 ;
    END
  END rsp_data[209]
  PIN rsp_data[20]
    DIRECTION INPUT ;
    USE SIGNAL ;
    PORT
      LAYER M4 ;
        RECT  0 34.572 0.192 34.596 ;
    END
  END rsp_data[20]
  PIN rsp_data[210]
    DIRECTION INPUT ;
    USE SIGNAL ;
    PORT
      LAYER M4 ;
        RECT  0 87.228 0.192 87.252 ;
    END
  END rsp_data[210]
  PIN rsp_data[211]
    DIRECTION INPUT ;
    USE SIGNAL ;
    PORT
      LAYER M4 ;
        RECT  0 87.516 0.192 87.54 ;
    END
  END rsp_data[211]
  PIN rsp_data[212]
    DIRECTION INPUT ;
    USE SIGNAL ;
    PORT
      LAYER M4 ;
        RECT  0 87.756 0.192 87.78 ;
    END
  END rsp_data[212]
  PIN rsp_data[213]
    DIRECTION INPUT ;
    USE SIGNAL ;
    PORT
      LAYER M4 ;
        RECT  0 88.044 0.192 88.068 ;
    END
  END rsp_data[213]
  PIN rsp_data[214]
    DIRECTION INPUT ;
    USE SIGNAL ;
    PORT
      LAYER M4 ;
        RECT  0 88.332 0.192 88.356 ;
    END
  END rsp_data[214]
  PIN rsp_data[215]
    DIRECTION INPUT ;
    USE SIGNAL ;
    PORT
      LAYER M4 ;
        RECT  0 88.62 0.192 88.644 ;
    END
  END rsp_data[215]
  PIN rsp_data[216]
    DIRECTION INPUT ;
    USE SIGNAL ;
    PORT
      LAYER M4 ;
        RECT  0 88.86 0.192 88.884 ;
    END
  END rsp_data[216]
  PIN rsp_data[217]
    DIRECTION INPUT ;
    USE SIGNAL ;
    PORT
      LAYER M4 ;
        RECT  0 89.148 0.192 89.172 ;
    END
  END rsp_data[217]
  PIN rsp_data[218]
    DIRECTION INPUT ;
    USE SIGNAL ;
    PORT
      LAYER M4 ;
        RECT  0 89.436 0.192 89.46 ;
    END
  END rsp_data[218]
  PIN rsp_data[219]
    DIRECTION INPUT ;
    USE SIGNAL ;
    PORT
      LAYER M4 ;
        RECT  0 89.724 0.192 89.748 ;
    END
  END rsp_data[219]
  PIN rsp_data[21]
    DIRECTION INPUT ;
    USE SIGNAL ;
    PORT
      LAYER M4 ;
        RECT  0 34.812 0.192 34.836 ;
    END
  END rsp_data[21]
  PIN rsp_data[220]
    DIRECTION INPUT ;
    USE SIGNAL ;
    PORT
      LAYER M4 ;
        RECT  0 90.012 0.192 90.036 ;
    END
  END rsp_data[220]
  PIN rsp_data[221]
    DIRECTION INPUT ;
    USE SIGNAL ;
    PORT
      LAYER M4 ;
        RECT  0 90.252 0.192 90.276 ;
    END
  END rsp_data[221]
  PIN rsp_data[222]
    DIRECTION INPUT ;
    USE SIGNAL ;
    PORT
      LAYER M4 ;
        RECT  0 90.54 0.192 90.564 ;
    END
  END rsp_data[222]
  PIN rsp_data[223]
    DIRECTION INPUT ;
    USE SIGNAL ;
    PORT
      LAYER M4 ;
        RECT  0 90.828 0.192 90.852 ;
    END
  END rsp_data[223]
  PIN rsp_data[224]
    DIRECTION INPUT ;
    USE SIGNAL ;
    PORT
      LAYER M4 ;
        RECT  0 91.116 0.192 91.14 ;
    END
  END rsp_data[224]
  PIN rsp_data[225]
    DIRECTION INPUT ;
    USE SIGNAL ;
    PORT
      LAYER M4 ;
        RECT  0 91.356 0.192 91.38 ;
    END
  END rsp_data[225]
  PIN rsp_data[226]
    DIRECTION INPUT ;
    USE SIGNAL ;
    PORT
      LAYER M4 ;
        RECT  0 91.644 0.192 91.668 ;
    END
  END rsp_data[226]
  PIN rsp_data[227]
    DIRECTION INPUT ;
    USE SIGNAL ;
    PORT
      LAYER M4 ;
        RECT  0 91.932 0.192 91.956 ;
    END
  END rsp_data[227]
  PIN rsp_data[228]
    DIRECTION INPUT ;
    USE SIGNAL ;
    PORT
      LAYER M4 ;
        RECT  0 92.22 0.192 92.244 ;
    END
  END rsp_data[228]
  PIN rsp_data[229]
    DIRECTION INPUT ;
    USE SIGNAL ;
    PORT
      LAYER M4 ;
        RECT  0 92.508 0.192 92.532 ;
    END
  END rsp_data[229]
  PIN rsp_data[22]
    DIRECTION INPUT ;
    USE SIGNAL ;
    PORT
      LAYER M4 ;
        RECT  0 35.1 0.192 35.124 ;
    END
  END rsp_data[22]
  PIN rsp_data[230]
    DIRECTION INPUT ;
    USE SIGNAL ;
    PORT
      LAYER M4 ;
        RECT  0 92.748 0.192 92.772 ;
    END
  END rsp_data[230]
  PIN rsp_data[231]
    DIRECTION INPUT ;
    USE SIGNAL ;
    PORT
      LAYER M4 ;
        RECT  0 93.036 0.192 93.06 ;
    END
  END rsp_data[231]
  PIN rsp_data[232]
    DIRECTION INPUT ;
    USE SIGNAL ;
    PORT
      LAYER M4 ;
        RECT  0 93.324 0.192 93.348 ;
    END
  END rsp_data[232]
  PIN rsp_data[233]
    DIRECTION INPUT ;
    USE SIGNAL ;
    PORT
      LAYER M4 ;
        RECT  0 93.612 0.192 93.636 ;
    END
  END rsp_data[233]
  PIN rsp_data[234]
    DIRECTION INPUT ;
    USE SIGNAL ;
    PORT
      LAYER M4 ;
        RECT  0 93.852 0.192 93.876 ;
    END
  END rsp_data[234]
  PIN rsp_data[235]
    DIRECTION INPUT ;
    USE SIGNAL ;
    PORT
      LAYER M4 ;
        RECT  0 94.14 0.192 94.164 ;
    END
  END rsp_data[235]
  PIN rsp_data[236]
    DIRECTION INPUT ;
    USE SIGNAL ;
    PORT
      LAYER M4 ;
        RECT  0 94.428 0.192 94.452 ;
    END
  END rsp_data[236]
  PIN rsp_data[237]
    DIRECTION INPUT ;
    USE SIGNAL ;
    PORT
      LAYER M4 ;
        RECT  0 94.716 0.192 94.74 ;
    END
  END rsp_data[237]
  PIN rsp_data[238]
    DIRECTION INPUT ;
    USE SIGNAL ;
    PORT
      LAYER M4 ;
        RECT  0 95.004 0.192 95.028 ;
    END
  END rsp_data[238]
  PIN rsp_data[239]
    DIRECTION INPUT ;
    USE SIGNAL ;
    PORT
      LAYER M4 ;
        RECT  0 95.244 0.192 95.268 ;
    END
  END rsp_data[239]
  PIN rsp_data[23]
    DIRECTION INPUT ;
    USE SIGNAL ;
    PORT
      LAYER M4 ;
        RECT  0 35.388 0.192 35.412 ;
    END
  END rsp_data[23]
  PIN rsp_data[240]
    DIRECTION INPUT ;
    USE SIGNAL ;
    PORT
      LAYER M4 ;
        RECT  0 95.532 0.192 95.556 ;
    END
  END rsp_data[240]
  PIN rsp_data[241]
    DIRECTION INPUT ;
    USE SIGNAL ;
    PORT
      LAYER M4 ;
        RECT  0 95.82 0.192 95.844 ;
    END
  END rsp_data[241]
  PIN rsp_data[242]
    DIRECTION INPUT ;
    USE SIGNAL ;
    PORT
      LAYER M4 ;
        RECT  0 96.108 0.192 96.132 ;
    END
  END rsp_data[242]
  PIN rsp_data[243]
    DIRECTION INPUT ;
    USE SIGNAL ;
    PORT
      LAYER M4 ;
        RECT  0 96.348 0.192 96.372 ;
    END
  END rsp_data[243]
  PIN rsp_data[244]
    DIRECTION INPUT ;
    USE SIGNAL ;
    PORT
      LAYER M4 ;
        RECT  0 96.636 0.192 96.66 ;
    END
  END rsp_data[244]
  PIN rsp_data[245]
    DIRECTION INPUT ;
    USE SIGNAL ;
    PORT
      LAYER M4 ;
        RECT  0 96.924 0.192 96.948 ;
    END
  END rsp_data[245]
  PIN rsp_data[246]
    DIRECTION INPUT ;
    USE SIGNAL ;
    PORT
      LAYER M4 ;
        RECT  0 97.212 0.192 97.236 ;
    END
  END rsp_data[246]
  PIN rsp_data[247]
    DIRECTION INPUT ;
    USE SIGNAL ;
    PORT
      LAYER M4 ;
        RECT  0 97.452 0.192 97.476 ;
    END
  END rsp_data[247]
  PIN rsp_data[248]
    DIRECTION INPUT ;
    USE SIGNAL ;
    PORT
      LAYER M4 ;
        RECT  0 97.74 0.192 97.764 ;
    END
  END rsp_data[248]
  PIN rsp_data[249]
    DIRECTION INPUT ;
    USE SIGNAL ;
    PORT
      LAYER M4 ;
        RECT  0 98.028 0.192 98.052 ;
    END
  END rsp_data[249]
  PIN rsp_data[24]
    DIRECTION INPUT ;
    USE SIGNAL ;
    PORT
      LAYER M4 ;
        RECT  0 35.676 0.192 35.7 ;
    END
  END rsp_data[24]
  PIN rsp_data[250]
    DIRECTION INPUT ;
    USE SIGNAL ;
    PORT
      LAYER M4 ;
        RECT  0 98.316 0.192 98.34 ;
    END
  END rsp_data[250]
  PIN rsp_data[251]
    DIRECTION INPUT ;
    USE SIGNAL ;
    PORT
      LAYER M4 ;
        RECT  0 98.604 0.192 98.628 ;
    END
  END rsp_data[251]
  PIN rsp_data[252]
    DIRECTION INPUT ;
    USE SIGNAL ;
    PORT
      LAYER M4 ;
        RECT  0 98.844 0.192 98.868 ;
    END
  END rsp_data[252]
  PIN rsp_data[253]
    DIRECTION INPUT ;
    USE SIGNAL ;
    PORT
      LAYER M4 ;
        RECT  0 99.132 0.192 99.156 ;
    END
  END rsp_data[253]
  PIN rsp_data[254]
    DIRECTION INPUT ;
    USE SIGNAL ;
    PORT
      LAYER M4 ;
        RECT  0 99.42 0.192 99.444 ;
    END
  END rsp_data[254]
  PIN rsp_data[255]
    DIRECTION INPUT ;
    USE SIGNAL ;
    PORT
      LAYER M4 ;
        RECT  0 99.708 0.192 99.732 ;
    END
  END rsp_data[255]
  PIN rsp_data[256]
    DIRECTION INPUT ;
    USE SIGNAL ;
    PORT
      LAYER M4 ;
        RECT  0 99.948 0.192 99.972 ;
    END
  END rsp_data[256]
  PIN rsp_data[257]
    DIRECTION INPUT ;
    USE SIGNAL ;
    PORT
      LAYER M4 ;
        RECT  0 100.236 0.192 100.26 ;
    END
  END rsp_data[257]
  PIN rsp_data[258]
    DIRECTION INPUT ;
    USE SIGNAL ;
    PORT
      LAYER M4 ;
        RECT  0 100.524 0.192 100.548 ;
    END
  END rsp_data[258]
  PIN rsp_data[259]
    DIRECTION INPUT ;
    USE SIGNAL ;
    PORT
      LAYER M4 ;
        RECT  0 100.812 0.192 100.836 ;
    END
  END rsp_data[259]
  PIN rsp_data[25]
    DIRECTION INPUT ;
    USE SIGNAL ;
    PORT
      LAYER M4 ;
        RECT  0 35.964 0.192 35.988 ;
    END
  END rsp_data[25]
  PIN rsp_data[260]
    DIRECTION INPUT ;
    USE SIGNAL ;
    PORT
      LAYER M4 ;
        RECT  0 101.1 0.192 101.124 ;
    END
  END rsp_data[260]
  PIN rsp_data[261]
    DIRECTION INPUT ;
    USE SIGNAL ;
    PORT
      LAYER M4 ;
        RECT  0 101.34 0.192 101.364 ;
    END
  END rsp_data[261]
  PIN rsp_data[262]
    DIRECTION INPUT ;
    USE SIGNAL ;
    PORT
      LAYER M4 ;
        RECT  0 101.628 0.192 101.652 ;
    END
  END rsp_data[262]
  PIN rsp_data[263]
    DIRECTION INPUT ;
    USE SIGNAL ;
    PORT
      LAYER M4 ;
        RECT  0 101.916 0.192 101.94 ;
    END
  END rsp_data[263]
  PIN rsp_data[264]
    DIRECTION INPUT ;
    USE SIGNAL ;
    PORT
      LAYER M4 ;
        RECT  0 102.204 0.192 102.228 ;
    END
  END rsp_data[264]
  PIN rsp_data[265]
    DIRECTION INPUT ;
    USE SIGNAL ;
    PORT
      LAYER M4 ;
        RECT  0 102.444 0.192 102.468 ;
    END
  END rsp_data[265]
  PIN rsp_data[266]
    DIRECTION INPUT ;
    USE SIGNAL ;
    PORT
      LAYER M4 ;
        RECT  0 102.732 0.192 102.756 ;
    END
  END rsp_data[266]
  PIN rsp_data[267]
    DIRECTION INPUT ;
    USE SIGNAL ;
    PORT
      LAYER M4 ;
        RECT  0 103.02 0.192 103.044 ;
    END
  END rsp_data[267]
  PIN rsp_data[268]
    DIRECTION INPUT ;
    USE SIGNAL ;
    PORT
      LAYER M4 ;
        RECT  0 103.308 0.192 103.332 ;
    END
  END rsp_data[268]
  PIN rsp_data[269]
    DIRECTION INPUT ;
    USE SIGNAL ;
    PORT
      LAYER M4 ;
        RECT  0 103.596 0.192 103.62 ;
    END
  END rsp_data[269]
  PIN rsp_data[26]
    DIRECTION INPUT ;
    USE SIGNAL ;
    PORT
      LAYER M4 ;
        RECT  0 36.204 0.192 36.228 ;
    END
  END rsp_data[26]
  PIN rsp_data[270]
    DIRECTION INPUT ;
    USE SIGNAL ;
    PORT
      LAYER M4 ;
        RECT  0 103.836 0.192 103.86 ;
    END
  END rsp_data[270]
  PIN rsp_data[271]
    DIRECTION INPUT ;
    USE SIGNAL ;
    PORT
      LAYER M4 ;
        RECT  0 104.124 0.192 104.148 ;
    END
  END rsp_data[271]
  PIN rsp_data[272]
    DIRECTION INPUT ;
    USE SIGNAL ;
    PORT
      LAYER M4 ;
        RECT  0 104.412 0.192 104.436 ;
    END
  END rsp_data[272]
  PIN rsp_data[273]
    DIRECTION INPUT ;
    USE SIGNAL ;
    PORT
      LAYER M4 ;
        RECT  0 104.7 0.192 104.724 ;
    END
  END rsp_data[273]
  PIN rsp_data[274]
    DIRECTION INPUT ;
    USE SIGNAL ;
    PORT
      LAYER M4 ;
        RECT  0 104.94 0.192 104.964 ;
    END
  END rsp_data[274]
  PIN rsp_data[275]
    DIRECTION INPUT ;
    USE SIGNAL ;
    PORT
      LAYER M4 ;
        RECT  0 105.228 0.192 105.252 ;
    END
  END rsp_data[275]
  PIN rsp_data[276]
    DIRECTION INPUT ;
    USE SIGNAL ;
    PORT
      LAYER M4 ;
        RECT  0 105.516 0.192 105.54 ;
    END
  END rsp_data[276]
  PIN rsp_data[277]
    DIRECTION INPUT ;
    USE SIGNAL ;
    PORT
      LAYER M4 ;
        RECT  0 105.804 0.192 105.828 ;
    END
  END rsp_data[277]
  PIN rsp_data[278]
    DIRECTION INPUT ;
    USE SIGNAL ;
    PORT
      LAYER M4 ;
        RECT  0 106.044 0.192 106.068 ;
    END
  END rsp_data[278]
  PIN rsp_data[279]
    DIRECTION INPUT ;
    USE SIGNAL ;
    PORT
      LAYER M4 ;
        RECT  0 106.332 0.192 106.356 ;
    END
  END rsp_data[279]
  PIN rsp_data[27]
    DIRECTION INPUT ;
    USE SIGNAL ;
    PORT
      LAYER M4 ;
        RECT  0 36.492 0.192 36.516 ;
    END
  END rsp_data[27]
  PIN rsp_data[280]
    DIRECTION INPUT ;
    USE SIGNAL ;
    PORT
      LAYER M4 ;
        RECT  0 106.62 0.192 106.644 ;
    END
  END rsp_data[280]
  PIN rsp_data[281]
    DIRECTION INPUT ;
    USE SIGNAL ;
    PORT
      LAYER M4 ;
        RECT  0 106.908 0.192 106.932 ;
    END
  END rsp_data[281]
  PIN rsp_data[282]
    DIRECTION INPUT ;
    USE SIGNAL ;
    PORT
      LAYER M4 ;
        RECT  0 107.196 0.192 107.22 ;
    END
  END rsp_data[282]
  PIN rsp_data[283]
    DIRECTION INPUT ;
    USE SIGNAL ;
    PORT
      LAYER M4 ;
        RECT  0 107.436 0.192 107.46 ;
    END
  END rsp_data[283]
  PIN rsp_data[284]
    DIRECTION INPUT ;
    USE SIGNAL ;
    PORT
      LAYER M4 ;
        RECT  0 107.724 0.192 107.748 ;
    END
  END rsp_data[284]
  PIN rsp_data[285]
    DIRECTION INPUT ;
    USE SIGNAL ;
    PORT
      LAYER M4 ;
        RECT  0 108.012 0.192 108.036 ;
    END
  END rsp_data[285]
  PIN rsp_data[286]
    DIRECTION INPUT ;
    USE SIGNAL ;
    PORT
      LAYER M4 ;
        RECT  0 108.3 0.192 108.324 ;
    END
  END rsp_data[286]
  PIN rsp_data[287]
    DIRECTION INPUT ;
    USE SIGNAL ;
    PORT
      LAYER M4 ;
        RECT  0 108.54 0.192 108.564 ;
    END
  END rsp_data[287]
  PIN rsp_data[288]
    DIRECTION INPUT ;
    USE SIGNAL ;
    PORT
      LAYER M4 ;
        RECT  0 108.828 0.192 108.852 ;
    END
  END rsp_data[288]
  PIN rsp_data[289]
    DIRECTION INPUT ;
    USE SIGNAL ;
    PORT
      LAYER M4 ;
        RECT  0 109.116 0.192 109.14 ;
    END
  END rsp_data[289]
  PIN rsp_data[28]
    DIRECTION INPUT ;
    USE SIGNAL ;
    PORT
      LAYER M4 ;
        RECT  0 36.78 0.192 36.804 ;
    END
  END rsp_data[28]
  PIN rsp_data[290]
    DIRECTION INPUT ;
    USE SIGNAL ;
    PORT
      LAYER M4 ;
        RECT  0 109.404 0.192 109.428 ;
    END
  END rsp_data[290]
  PIN rsp_data[291]
    DIRECTION INPUT ;
    USE SIGNAL ;
    PORT
      LAYER M4 ;
        RECT  0 109.692 0.192 109.716 ;
    END
  END rsp_data[291]
  PIN rsp_data[292]
    DIRECTION INPUT ;
    USE SIGNAL ;
    PORT
      LAYER M4 ;
        RECT  0 109.932 0.192 109.956 ;
    END
  END rsp_data[292]
  PIN rsp_data[293]
    DIRECTION INPUT ;
    USE SIGNAL ;
    PORT
      LAYER M4 ;
        RECT  0 110.22 0.192 110.244 ;
    END
  END rsp_data[293]
  PIN rsp_data[294]
    DIRECTION INPUT ;
    USE SIGNAL ;
    PORT
      LAYER M4 ;
        RECT  0 110.508 0.192 110.532 ;
    END
  END rsp_data[294]
  PIN rsp_data[295]
    DIRECTION INPUT ;
    USE SIGNAL ;
    PORT
      LAYER M4 ;
        RECT  0 110.796 0.192 110.82 ;
    END
  END rsp_data[295]
  PIN rsp_data[296]
    DIRECTION INPUT ;
    USE SIGNAL ;
    PORT
      LAYER M4 ;
        RECT  0 111.036 0.192 111.06 ;
    END
  END rsp_data[296]
  PIN rsp_data[297]
    DIRECTION INPUT ;
    USE SIGNAL ;
    PORT
      LAYER M4 ;
        RECT  0 111.324 0.192 111.348 ;
    END
  END rsp_data[297]
  PIN rsp_data[298]
    DIRECTION INPUT ;
    USE SIGNAL ;
    PORT
      LAYER M4 ;
        RECT  0 111.612 0.192 111.636 ;
    END
  END rsp_data[298]
  PIN rsp_data[299]
    DIRECTION INPUT ;
    USE SIGNAL ;
    PORT
      LAYER M4 ;
        RECT  0 111.9 0.192 111.924 ;
    END
  END rsp_data[299]
  PIN rsp_data[29]
    DIRECTION INPUT ;
    USE SIGNAL ;
    PORT
      LAYER M4 ;
        RECT  0 37.068 0.192 37.092 ;
    END
  END rsp_data[29]
  PIN rsp_data[2]
    DIRECTION INPUT ;
    USE SIGNAL ;
    PORT
      LAYER M4 ;
        RECT  0 29.58 0.192 29.604 ;
    END
  END rsp_data[2]
  PIN rsp_data[300]
    DIRECTION INPUT ;
    USE SIGNAL ;
    PORT
      LAYER M4 ;
        RECT  0 112.188 0.192 112.212 ;
    END
  END rsp_data[300]
  PIN rsp_data[301]
    DIRECTION INPUT ;
    USE SIGNAL ;
    PORT
      LAYER M4 ;
        RECT  0 112.428 0.192 112.452 ;
    END
  END rsp_data[301]
  PIN rsp_data[302]
    DIRECTION INPUT ;
    USE SIGNAL ;
    PORT
      LAYER M4 ;
        RECT  0 112.716 0.192 112.74 ;
    END
  END rsp_data[302]
  PIN rsp_data[303]
    DIRECTION INPUT ;
    USE SIGNAL ;
    PORT
      LAYER M4 ;
        RECT  0 113.004 0.192 113.028 ;
    END
  END rsp_data[303]
  PIN rsp_data[304]
    DIRECTION INPUT ;
    USE SIGNAL ;
    PORT
      LAYER M4 ;
        RECT  0 113.292 0.192 113.316 ;
    END
  END rsp_data[304]
  PIN rsp_data[305]
    DIRECTION INPUT ;
    USE SIGNAL ;
    PORT
      LAYER M4 ;
        RECT  0 113.532 0.192 113.556 ;
    END
  END rsp_data[305]
  PIN rsp_data[306]
    DIRECTION INPUT ;
    USE SIGNAL ;
    PORT
      LAYER M4 ;
        RECT  0 113.82 0.192 113.844 ;
    END
  END rsp_data[306]
  PIN rsp_data[307]
    DIRECTION INPUT ;
    USE SIGNAL ;
    PORT
      LAYER M4 ;
        RECT  0 114.108 0.192 114.132 ;
    END
  END rsp_data[307]
  PIN rsp_data[308]
    DIRECTION INPUT ;
    USE SIGNAL ;
    PORT
      LAYER M4 ;
        RECT  0 114.396 0.192 114.42 ;
    END
  END rsp_data[308]
  PIN rsp_data[309]
    DIRECTION INPUT ;
    USE SIGNAL ;
    PORT
      LAYER M4 ;
        RECT  0 114.636 0.192 114.66 ;
    END
  END rsp_data[309]
  PIN rsp_data[30]
    DIRECTION INPUT ;
    USE SIGNAL ;
    PORT
      LAYER M4 ;
        RECT  0 37.308 0.192 37.332 ;
    END
  END rsp_data[30]
  PIN rsp_data[310]
    DIRECTION INPUT ;
    USE SIGNAL ;
    PORT
      LAYER M4 ;
        RECT  0 114.924 0.192 114.948 ;
    END
  END rsp_data[310]
  PIN rsp_data[311]
    DIRECTION INPUT ;
    USE SIGNAL ;
    PORT
      LAYER M4 ;
        RECT  0 115.212 0.192 115.236 ;
    END
  END rsp_data[311]
  PIN rsp_data[312]
    DIRECTION INPUT ;
    USE SIGNAL ;
    PORT
      LAYER M4 ;
        RECT  0 115.5 0.192 115.524 ;
    END
  END rsp_data[312]
  PIN rsp_data[313]
    DIRECTION INPUT ;
    USE SIGNAL ;
    PORT
      LAYER M4 ;
        RECT  0 115.788 0.192 115.812 ;
    END
  END rsp_data[313]
  PIN rsp_data[314]
    DIRECTION INPUT ;
    USE SIGNAL ;
    PORT
      LAYER M4 ;
        RECT  0 116.028 0.192 116.052 ;
    END
  END rsp_data[314]
  PIN rsp_data[315]
    DIRECTION INPUT ;
    USE SIGNAL ;
    PORT
      LAYER M4 ;
        RECT  0 116.316 0.192 116.34 ;
    END
  END rsp_data[315]
  PIN rsp_data[316]
    DIRECTION INPUT ;
    USE SIGNAL ;
    PORT
      LAYER M4 ;
        RECT  0 116.604 0.192 116.628 ;
    END
  END rsp_data[316]
  PIN rsp_data[317]
    DIRECTION INPUT ;
    USE SIGNAL ;
    PORT
      LAYER M4 ;
        RECT  0 116.892 0.192 116.916 ;
    END
  END rsp_data[317]
  PIN rsp_data[318]
    DIRECTION INPUT ;
    USE SIGNAL ;
    PORT
      LAYER M4 ;
        RECT  0 117.132 0.192 117.156 ;
    END
  END rsp_data[318]
  PIN rsp_data[319]
    DIRECTION INPUT ;
    USE SIGNAL ;
    PORT
      LAYER M4 ;
        RECT  0 117.42 0.192 117.444 ;
    END
  END rsp_data[319]
  PIN rsp_data[31]
    DIRECTION INPUT ;
    USE SIGNAL ;
    PORT
      LAYER M4 ;
        RECT  0 37.596 0.192 37.62 ;
    END
  END rsp_data[31]
  PIN rsp_data[320]
    DIRECTION INPUT ;
    USE SIGNAL ;
    PORT
      LAYER M4 ;
        RECT  0 117.708 0.192 117.732 ;
    END
  END rsp_data[320]
  PIN rsp_data[321]
    DIRECTION INPUT ;
    USE SIGNAL ;
    PORT
      LAYER M4 ;
        RECT  0 117.996 0.192 118.02 ;
    END
  END rsp_data[321]
  PIN rsp_data[322]
    DIRECTION INPUT ;
    USE SIGNAL ;
    PORT
      LAYER M4 ;
        RECT  0 118.284 0.192 118.308 ;
    END
  END rsp_data[322]
  PIN rsp_data[323]
    DIRECTION INPUT ;
    USE SIGNAL ;
    PORT
      LAYER M4 ;
        RECT  0 118.524 0.192 118.548 ;
    END
  END rsp_data[323]
  PIN rsp_data[324]
    DIRECTION INPUT ;
    USE SIGNAL ;
    PORT
      LAYER M4 ;
        RECT  0 118.812 0.192 118.836 ;
    END
  END rsp_data[324]
  PIN rsp_data[325]
    DIRECTION INPUT ;
    USE SIGNAL ;
    PORT
      LAYER M4 ;
        RECT  0 119.1 0.192 119.124 ;
    END
  END rsp_data[325]
  PIN rsp_data[326]
    DIRECTION INPUT ;
    USE SIGNAL ;
    PORT
      LAYER M4 ;
        RECT  0 119.388 0.192 119.412 ;
    END
  END rsp_data[326]
  PIN rsp_data[327]
    DIRECTION INPUT ;
    USE SIGNAL ;
    PORT
      LAYER M4 ;
        RECT  0 119.628 0.192 119.652 ;
    END
  END rsp_data[327]
  PIN rsp_data[328]
    DIRECTION INPUT ;
    USE SIGNAL ;
    PORT
      LAYER M4 ;
        RECT  0 119.916 0.192 119.94 ;
    END
  END rsp_data[328]
  PIN rsp_data[329]
    DIRECTION INPUT ;
    USE SIGNAL ;
    PORT
      LAYER M4 ;
        RECT  0 120.204 0.192 120.228 ;
    END
  END rsp_data[329]
  PIN rsp_data[32]
    DIRECTION INPUT ;
    USE SIGNAL ;
    PORT
      LAYER M4 ;
        RECT  0 37.884 0.192 37.908 ;
    END
  END rsp_data[32]
  PIN rsp_data[330]
    DIRECTION INPUT ;
    USE SIGNAL ;
    PORT
      LAYER M4 ;
        RECT  0 120.492 0.192 120.516 ;
    END
  END rsp_data[330]
  PIN rsp_data[331]
    DIRECTION INPUT ;
    USE SIGNAL ;
    PORT
      LAYER M4 ;
        RECT  0 120.78 0.192 120.804 ;
    END
  END rsp_data[331]
  PIN rsp_data[332]
    DIRECTION INPUT ;
    USE SIGNAL ;
    PORT
      LAYER M4 ;
        RECT  0 121.02 0.192 121.044 ;
    END
  END rsp_data[332]
  PIN rsp_data[333]
    DIRECTION INPUT ;
    USE SIGNAL ;
    PORT
      LAYER M4 ;
        RECT  0 121.308 0.192 121.332 ;
    END
  END rsp_data[333]
  PIN rsp_data[334]
    DIRECTION INPUT ;
    USE SIGNAL ;
    PORT
      LAYER M4 ;
        RECT  0 121.596 0.192 121.62 ;
    END
  END rsp_data[334]
  PIN rsp_data[335]
    DIRECTION INPUT ;
    USE SIGNAL ;
    PORT
      LAYER M4 ;
        RECT  0 121.884 0.192 121.908 ;
    END
  END rsp_data[335]
  PIN rsp_data[336]
    DIRECTION INPUT ;
    USE SIGNAL ;
    PORT
      LAYER M4 ;
        RECT  0 122.124 0.192 122.148 ;
    END
  END rsp_data[336]
  PIN rsp_data[337]
    DIRECTION INPUT ;
    USE SIGNAL ;
    PORT
      LAYER M4 ;
        RECT  0 122.412 0.192 122.436 ;
    END
  END rsp_data[337]
  PIN rsp_data[338]
    DIRECTION INPUT ;
    USE SIGNAL ;
    PORT
      LAYER M4 ;
        RECT  0 122.7 0.192 122.724 ;
    END
  END rsp_data[338]
  PIN rsp_data[339]
    DIRECTION INPUT ;
    USE SIGNAL ;
    PORT
      LAYER M4 ;
        RECT  0 122.988 0.192 123.012 ;
    END
  END rsp_data[339]
  PIN rsp_data[33]
    DIRECTION INPUT ;
    USE SIGNAL ;
    PORT
      LAYER M4 ;
        RECT  0 38.172 0.192 38.196 ;
    END
  END rsp_data[33]
  PIN rsp_data[340]
    DIRECTION INPUT ;
    USE SIGNAL ;
    PORT
      LAYER M4 ;
        RECT  0 123.276 0.192 123.3 ;
    END
  END rsp_data[340]
  PIN rsp_data[341]
    DIRECTION INPUT ;
    USE SIGNAL ;
    PORT
      LAYER M4 ;
        RECT  0 123.516 0.192 123.54 ;
    END
  END rsp_data[341]
  PIN rsp_data[342]
    DIRECTION INPUT ;
    USE SIGNAL ;
    PORT
      LAYER M4 ;
        RECT  0 123.804 0.192 123.828 ;
    END
  END rsp_data[342]
  PIN rsp_data[343]
    DIRECTION INPUT ;
    USE SIGNAL ;
    PORT
      LAYER M4 ;
        RECT  0 124.092 0.192 124.116 ;
    END
  END rsp_data[343]
  PIN rsp_data[344]
    DIRECTION INPUT ;
    USE SIGNAL ;
    PORT
      LAYER M4 ;
        RECT  0 124.38 0.192 124.404 ;
    END
  END rsp_data[344]
  PIN rsp_data[345]
    DIRECTION INPUT ;
    USE SIGNAL ;
    PORT
      LAYER M4 ;
        RECT  0 124.62 0.192 124.644 ;
    END
  END rsp_data[345]
  PIN rsp_data[346]
    DIRECTION INPUT ;
    USE SIGNAL ;
    PORT
      LAYER M4 ;
        RECT  0 124.908 0.192 124.932 ;
    END
  END rsp_data[346]
  PIN rsp_data[347]
    DIRECTION INPUT ;
    USE SIGNAL ;
    PORT
      LAYER M4 ;
        RECT  0 125.196 0.192 125.22 ;
    END
  END rsp_data[347]
  PIN rsp_data[348]
    DIRECTION INPUT ;
    USE SIGNAL ;
    PORT
      LAYER M4 ;
        RECT  0 125.484 0.192 125.508 ;
    END
  END rsp_data[348]
  PIN rsp_data[349]
    DIRECTION INPUT ;
    USE SIGNAL ;
    PORT
      LAYER M4 ;
        RECT  0 125.724 0.192 125.748 ;
    END
  END rsp_data[349]
  PIN rsp_data[34]
    DIRECTION INPUT ;
    USE SIGNAL ;
    PORT
      LAYER M4 ;
        RECT  0 38.46 0.192 38.484 ;
    END
  END rsp_data[34]
  PIN rsp_data[350]
    DIRECTION INPUT ;
    USE SIGNAL ;
    PORT
      LAYER M4 ;
        RECT  0 126.012 0.192 126.036 ;
    END
  END rsp_data[350]
  PIN rsp_data[351]
    DIRECTION INPUT ;
    USE SIGNAL ;
    PORT
      LAYER M4 ;
        RECT  0 126.3 0.192 126.324 ;
    END
  END rsp_data[351]
  PIN rsp_data[352]
    DIRECTION INPUT ;
    USE SIGNAL ;
    PORT
      LAYER M4 ;
        RECT  0 126.588 0.192 126.612 ;
    END
  END rsp_data[352]
  PIN rsp_data[353]
    DIRECTION INPUT ;
    USE SIGNAL ;
    PORT
      LAYER M4 ;
        RECT  0 126.876 0.192 126.9 ;
    END
  END rsp_data[353]
  PIN rsp_data[354]
    DIRECTION INPUT ;
    USE SIGNAL ;
    PORT
      LAYER M4 ;
        RECT  0 127.116 0.192 127.14 ;
    END
  END rsp_data[354]
  PIN rsp_data[355]
    DIRECTION INPUT ;
    USE SIGNAL ;
    PORT
      LAYER M4 ;
        RECT  0 127.404 0.192 127.428 ;
    END
  END rsp_data[355]
  PIN rsp_data[356]
    DIRECTION INPUT ;
    USE SIGNAL ;
    PORT
      LAYER M4 ;
        RECT  0 127.692 0.192 127.716 ;
    END
  END rsp_data[356]
  PIN rsp_data[357]
    DIRECTION INPUT ;
    USE SIGNAL ;
    PORT
      LAYER M4 ;
        RECT  0 127.98 0.192 128.004 ;
    END
  END rsp_data[357]
  PIN rsp_data[358]
    DIRECTION INPUT ;
    USE SIGNAL ;
    PORT
      LAYER M4 ;
        RECT  0 128.22 0.192 128.244 ;
    END
  END rsp_data[358]
  PIN rsp_data[359]
    DIRECTION INPUT ;
    USE SIGNAL ;
    PORT
      LAYER M4 ;
        RECT  0 128.508 0.192 128.532 ;
    END
  END rsp_data[359]
  PIN rsp_data[35]
    DIRECTION INPUT ;
    USE SIGNAL ;
    PORT
      LAYER M4 ;
        RECT  0 38.7 0.192 38.724 ;
    END
  END rsp_data[35]
  PIN rsp_data[360]
    DIRECTION INPUT ;
    USE SIGNAL ;
    PORT
      LAYER M4 ;
        RECT  0 128.796 0.192 128.82 ;
    END
  END rsp_data[360]
  PIN rsp_data[361]
    DIRECTION INPUT ;
    USE SIGNAL ;
    PORT
      LAYER M4 ;
        RECT  0 129.084 0.192 129.108 ;
    END
  END rsp_data[361]
  PIN rsp_data[362]
    DIRECTION INPUT ;
    USE SIGNAL ;
    PORT
      LAYER M4 ;
        RECT  0 129.372 0.192 129.396 ;
    END
  END rsp_data[362]
  PIN rsp_data[363]
    DIRECTION INPUT ;
    USE SIGNAL ;
    PORT
      LAYER M4 ;
        RECT  0 129.612 0.192 129.636 ;
    END
  END rsp_data[363]
  PIN rsp_data[364]
    DIRECTION INPUT ;
    USE SIGNAL ;
    PORT
      LAYER M4 ;
        RECT  0 129.9 0.192 129.924 ;
    END
  END rsp_data[364]
  PIN rsp_data[365]
    DIRECTION INPUT ;
    USE SIGNAL ;
    PORT
      LAYER M4 ;
        RECT  0 130.188 0.192 130.212 ;
    END
  END rsp_data[365]
  PIN rsp_data[366]
    DIRECTION INPUT ;
    USE SIGNAL ;
    PORT
      LAYER M4 ;
        RECT  0 130.476 0.192 130.5 ;
    END
  END rsp_data[366]
  PIN rsp_data[367]
    DIRECTION INPUT ;
    USE SIGNAL ;
    PORT
      LAYER M4 ;
        RECT  0 130.716 0.192 130.74 ;
    END
  END rsp_data[367]
  PIN rsp_data[368]
    DIRECTION INPUT ;
    USE SIGNAL ;
    PORT
      LAYER M4 ;
        RECT  0 131.004 0.192 131.028 ;
    END
  END rsp_data[368]
  PIN rsp_data[369]
    DIRECTION INPUT ;
    USE SIGNAL ;
    PORT
      LAYER M4 ;
        RECT  0 131.292 0.192 131.316 ;
    END
  END rsp_data[369]
  PIN rsp_data[36]
    DIRECTION INPUT ;
    USE SIGNAL ;
    PORT
      LAYER M4 ;
        RECT  0 38.988 0.192 39.012 ;
    END
  END rsp_data[36]
  PIN rsp_data[370]
    DIRECTION INPUT ;
    USE SIGNAL ;
    PORT
      LAYER M4 ;
        RECT  0 131.58 0.192 131.604 ;
    END
  END rsp_data[370]
  PIN rsp_data[371]
    DIRECTION INPUT ;
    USE SIGNAL ;
    PORT
      LAYER M4 ;
        RECT  0 131.868 0.192 131.892 ;
    END
  END rsp_data[371]
  PIN rsp_data[372]
    DIRECTION INPUT ;
    USE SIGNAL ;
    PORT
      LAYER M4 ;
        RECT  0 132.108 0.192 132.132 ;
    END
  END rsp_data[372]
  PIN rsp_data[373]
    DIRECTION INPUT ;
    USE SIGNAL ;
    PORT
      LAYER M4 ;
        RECT  0 132.396 0.192 132.42 ;
    END
  END rsp_data[373]
  PIN rsp_data[374]
    DIRECTION INPUT ;
    USE SIGNAL ;
    PORT
      LAYER M4 ;
        RECT  0 132.684 0.192 132.708 ;
    END
  END rsp_data[374]
  PIN rsp_data[375]
    DIRECTION INPUT ;
    USE SIGNAL ;
    PORT
      LAYER M4 ;
        RECT  0 132.972 0.192 132.996 ;
    END
  END rsp_data[375]
  PIN rsp_data[376]
    DIRECTION INPUT ;
    USE SIGNAL ;
    PORT
      LAYER M4 ;
        RECT  0 133.212 0.192 133.236 ;
    END
  END rsp_data[376]
  PIN rsp_data[377]
    DIRECTION INPUT ;
    USE SIGNAL ;
    PORT
      LAYER M4 ;
        RECT  0 133.5 0.192 133.524 ;
    END
  END rsp_data[377]
  PIN rsp_data[378]
    DIRECTION INPUT ;
    USE SIGNAL ;
    PORT
      LAYER M4 ;
        RECT  0 133.788 0.192 133.812 ;
    END
  END rsp_data[378]
  PIN rsp_data[379]
    DIRECTION INPUT ;
    USE SIGNAL ;
    PORT
      LAYER M4 ;
        RECT  0 134.076 0.192 134.1 ;
    END
  END rsp_data[379]
  PIN rsp_data[37]
    DIRECTION INPUT ;
    USE SIGNAL ;
    PORT
      LAYER M4 ;
        RECT  0 39.276 0.192 39.3 ;
    END
  END rsp_data[37]
  PIN rsp_data[380]
    DIRECTION INPUT ;
    USE SIGNAL ;
    PORT
      LAYER M4 ;
        RECT  0 134.316 0.192 134.34 ;
    END
  END rsp_data[380]
  PIN rsp_data[381]
    DIRECTION INPUT ;
    USE SIGNAL ;
    PORT
      LAYER M4 ;
        RECT  0 134.604 0.192 134.628 ;
    END
  END rsp_data[381]
  PIN rsp_data[382]
    DIRECTION INPUT ;
    USE SIGNAL ;
    PORT
      LAYER M4 ;
        RECT  0 134.892 0.192 134.916 ;
    END
  END rsp_data[382]
  PIN rsp_data[383]
    DIRECTION INPUT ;
    USE SIGNAL ;
    PORT
      LAYER M4 ;
        RECT  0 135.18 0.192 135.204 ;
    END
  END rsp_data[383]
  PIN rsp_data[384]
    DIRECTION INPUT ;
    USE SIGNAL ;
    PORT
      LAYER M4 ;
        RECT  0 135.468 0.192 135.492 ;
    END
  END rsp_data[384]
  PIN rsp_data[385]
    DIRECTION INPUT ;
    USE SIGNAL ;
    PORT
      LAYER M4 ;
        RECT  0 135.708 0.192 135.732 ;
    END
  END rsp_data[385]
  PIN rsp_data[386]
    DIRECTION INPUT ;
    USE SIGNAL ;
    PORT
      LAYER M4 ;
        RECT  0 135.996 0.192 136.02 ;
    END
  END rsp_data[386]
  PIN rsp_data[387]
    DIRECTION INPUT ;
    USE SIGNAL ;
    PORT
      LAYER M4 ;
        RECT  0 136.284 0.192 136.308 ;
    END
  END rsp_data[387]
  PIN rsp_data[388]
    DIRECTION INPUT ;
    USE SIGNAL ;
    PORT
      LAYER M4 ;
        RECT  0 136.572 0.192 136.596 ;
    END
  END rsp_data[388]
  PIN rsp_data[389]
    DIRECTION INPUT ;
    USE SIGNAL ;
    PORT
      LAYER M4 ;
        RECT  0 136.812 0.192 136.836 ;
    END
  END rsp_data[389]
  PIN rsp_data[38]
    DIRECTION INPUT ;
    USE SIGNAL ;
    PORT
      LAYER M4 ;
        RECT  0 39.564 0.192 39.588 ;
    END
  END rsp_data[38]
  PIN rsp_data[390]
    DIRECTION INPUT ;
    USE SIGNAL ;
    PORT
      LAYER M4 ;
        RECT  0 137.1 0.192 137.124 ;
    END
  END rsp_data[390]
  PIN rsp_data[391]
    DIRECTION INPUT ;
    USE SIGNAL ;
    PORT
      LAYER M4 ;
        RECT  0 137.388 0.192 137.412 ;
    END
  END rsp_data[391]
  PIN rsp_data[392]
    DIRECTION INPUT ;
    USE SIGNAL ;
    PORT
      LAYER M4 ;
        RECT  0 137.676 0.192 137.7 ;
    END
  END rsp_data[392]
  PIN rsp_data[393]
    DIRECTION INPUT ;
    USE SIGNAL ;
    PORT
      LAYER M4 ;
        RECT  0 137.964 0.192 137.988 ;
    END
  END rsp_data[393]
  PIN rsp_data[394]
    DIRECTION INPUT ;
    USE SIGNAL ;
    PORT
      LAYER M4 ;
        RECT  0 138.204 0.192 138.228 ;
    END
  END rsp_data[394]
  PIN rsp_data[395]
    DIRECTION INPUT ;
    USE SIGNAL ;
    PORT
      LAYER M4 ;
        RECT  0 138.492 0.192 138.516 ;
    END
  END rsp_data[395]
  PIN rsp_data[396]
    DIRECTION INPUT ;
    USE SIGNAL ;
    PORT
      LAYER M4 ;
        RECT  0 138.78 0.192 138.804 ;
    END
  END rsp_data[396]
  PIN rsp_data[397]
    DIRECTION INPUT ;
    USE SIGNAL ;
    PORT
      LAYER M4 ;
        RECT  0 139.068 0.192 139.092 ;
    END
  END rsp_data[397]
  PIN rsp_data[398]
    DIRECTION INPUT ;
    USE SIGNAL ;
    PORT
      LAYER M4 ;
        RECT  0 139.308 0.192 139.332 ;
    END
  END rsp_data[398]
  PIN rsp_data[399]
    DIRECTION INPUT ;
    USE SIGNAL ;
    PORT
      LAYER M4 ;
        RECT  0 139.596 0.192 139.62 ;
    END
  END rsp_data[399]
  PIN rsp_data[39]
    DIRECTION INPUT ;
    USE SIGNAL ;
    PORT
      LAYER M4 ;
        RECT  0 39.804 0.192 39.828 ;
    END
  END rsp_data[39]
  PIN rsp_data[3]
    DIRECTION INPUT ;
    USE SIGNAL ;
    PORT
      LAYER M4 ;
        RECT  0 29.868 0.192 29.892 ;
    END
  END rsp_data[3]
  PIN rsp_data[400]
    DIRECTION INPUT ;
    USE SIGNAL ;
    PORT
      LAYER M4 ;
        RECT  0 139.884 0.192 139.908 ;
    END
  END rsp_data[400]
  PIN rsp_data[401]
    DIRECTION INPUT ;
    USE SIGNAL ;
    PORT
      LAYER M4 ;
        RECT  0 140.172 0.192 140.196 ;
    END
  END rsp_data[401]
  PIN rsp_data[402]
    DIRECTION INPUT ;
    USE SIGNAL ;
    PORT
      LAYER M4 ;
        RECT  0 140.46 0.192 140.484 ;
    END
  END rsp_data[402]
  PIN rsp_data[403]
    DIRECTION INPUT ;
    USE SIGNAL ;
    PORT
      LAYER M4 ;
        RECT  0 140.7 0.192 140.724 ;
    END
  END rsp_data[403]
  PIN rsp_data[404]
    DIRECTION INPUT ;
    USE SIGNAL ;
    PORT
      LAYER M4 ;
        RECT  0 140.988 0.192 141.012 ;
    END
  END rsp_data[404]
  PIN rsp_data[405]
    DIRECTION INPUT ;
    USE SIGNAL ;
    PORT
      LAYER M4 ;
        RECT  0 141.276 0.192 141.3 ;
    END
  END rsp_data[405]
  PIN rsp_data[406]
    DIRECTION INPUT ;
    USE SIGNAL ;
    PORT
      LAYER M4 ;
        RECT  0 141.564 0.192 141.588 ;
    END
  END rsp_data[406]
  PIN rsp_data[407]
    DIRECTION INPUT ;
    USE SIGNAL ;
    PORT
      LAYER M4 ;
        RECT  0 141.804 0.192 141.828 ;
    END
  END rsp_data[407]
  PIN rsp_data[408]
    DIRECTION INPUT ;
    USE SIGNAL ;
    PORT
      LAYER M4 ;
        RECT  0 142.092 0.192 142.116 ;
    END
  END rsp_data[408]
  PIN rsp_data[409]
    DIRECTION INPUT ;
    USE SIGNAL ;
    PORT
      LAYER M4 ;
        RECT  0 142.38 0.192 142.404 ;
    END
  END rsp_data[409]
  PIN rsp_data[40]
    DIRECTION INPUT ;
    USE SIGNAL ;
    PORT
      LAYER M4 ;
        RECT  0 40.092 0.192 40.116 ;
    END
  END rsp_data[40]
  PIN rsp_data[410]
    DIRECTION INPUT ;
    USE SIGNAL ;
    PORT
      LAYER M4 ;
        RECT  0 142.668 0.192 142.692 ;
    END
  END rsp_data[410]
  PIN rsp_data[411]
    DIRECTION INPUT ;
    USE SIGNAL ;
    PORT
      LAYER M4 ;
        RECT  0 142.908 0.192 142.932 ;
    END
  END rsp_data[411]
  PIN rsp_data[412]
    DIRECTION INPUT ;
    USE SIGNAL ;
    PORT
      LAYER M4 ;
        RECT  0 143.196 0.192 143.22 ;
    END
  END rsp_data[412]
  PIN rsp_data[413]
    DIRECTION INPUT ;
    USE SIGNAL ;
    PORT
      LAYER M4 ;
        RECT  0 143.484 0.192 143.508 ;
    END
  END rsp_data[413]
  PIN rsp_data[414]
    DIRECTION INPUT ;
    USE SIGNAL ;
    PORT
      LAYER M4 ;
        RECT  0 143.772 0.192 143.796 ;
    END
  END rsp_data[414]
  PIN rsp_data[415]
    DIRECTION INPUT ;
    USE SIGNAL ;
    PORT
      LAYER M4 ;
        RECT  0 144.06 0.192 144.084 ;
    END
  END rsp_data[415]
  PIN rsp_data[416]
    DIRECTION INPUT ;
    USE SIGNAL ;
    PORT
      LAYER M4 ;
        RECT  0 144.3 0.192 144.324 ;
    END
  END rsp_data[416]
  PIN rsp_data[417]
    DIRECTION INPUT ;
    USE SIGNAL ;
    PORT
      LAYER M4 ;
        RECT  0 144.588 0.192 144.612 ;
    END
  END rsp_data[417]
  PIN rsp_data[418]
    DIRECTION INPUT ;
    USE SIGNAL ;
    PORT
      LAYER M4 ;
        RECT  0 144.876 0.192 144.9 ;
    END
  END rsp_data[418]
  PIN rsp_data[419]
    DIRECTION INPUT ;
    USE SIGNAL ;
    PORT
      LAYER M4 ;
        RECT  0 145.164 0.192 145.188 ;
    END
  END rsp_data[419]
  PIN rsp_data[41]
    DIRECTION INPUT ;
    USE SIGNAL ;
    PORT
      LAYER M4 ;
        RECT  0 40.38 0.192 40.404 ;
    END
  END rsp_data[41]
  PIN rsp_data[420]
    DIRECTION INPUT ;
    USE SIGNAL ;
    PORT
      LAYER M4 ;
        RECT  0 145.404 0.192 145.428 ;
    END
  END rsp_data[420]
  PIN rsp_data[421]
    DIRECTION INPUT ;
    USE SIGNAL ;
    PORT
      LAYER M4 ;
        RECT  0 145.692 0.192 145.716 ;
    END
  END rsp_data[421]
  PIN rsp_data[422]
    DIRECTION INPUT ;
    USE SIGNAL ;
    PORT
      LAYER M4 ;
        RECT  0 145.98 0.192 146.004 ;
    END
  END rsp_data[422]
  PIN rsp_data[423]
    DIRECTION INPUT ;
    USE SIGNAL ;
    PORT
      LAYER M4 ;
        RECT  0 146.268 0.192 146.292 ;
    END
  END rsp_data[423]
  PIN rsp_data[424]
    DIRECTION INPUT ;
    USE SIGNAL ;
    PORT
      LAYER M4 ;
        RECT  0 146.556 0.192 146.58 ;
    END
  END rsp_data[424]
  PIN rsp_data[425]
    DIRECTION INPUT ;
    USE SIGNAL ;
    PORT
      LAYER M4 ;
        RECT  0 146.796 0.192 146.82 ;
    END
  END rsp_data[425]
  PIN rsp_data[426]
    DIRECTION INPUT ;
    USE SIGNAL ;
    PORT
      LAYER M4 ;
        RECT  0 147.084 0.192 147.108 ;
    END
  END rsp_data[426]
  PIN rsp_data[427]
    DIRECTION INPUT ;
    USE SIGNAL ;
    PORT
      LAYER M4 ;
        RECT  0 147.372 0.192 147.396 ;
    END
  END rsp_data[427]
  PIN rsp_data[428]
    DIRECTION INPUT ;
    USE SIGNAL ;
    PORT
      LAYER M4 ;
        RECT  0 147.66 0.192 147.684 ;
    END
  END rsp_data[428]
  PIN rsp_data[429]
    DIRECTION INPUT ;
    USE SIGNAL ;
    PORT
      LAYER M4 ;
        RECT  0 147.9 0.192 147.924 ;
    END
  END rsp_data[429]
  PIN rsp_data[42]
    DIRECTION INPUT ;
    USE SIGNAL ;
    PORT
      LAYER M4 ;
        RECT  0 40.668 0.192 40.692 ;
    END
  END rsp_data[42]
  PIN rsp_data[430]
    DIRECTION INPUT ;
    USE SIGNAL ;
    PORT
      LAYER M4 ;
        RECT  0 148.188 0.192 148.212 ;
    END
  END rsp_data[430]
  PIN rsp_data[431]
    DIRECTION INPUT ;
    USE SIGNAL ;
    PORT
      LAYER M4 ;
        RECT  0 148.476 0.192 148.5 ;
    END
  END rsp_data[431]
  PIN rsp_data[432]
    DIRECTION INPUT ;
    USE SIGNAL ;
    PORT
      LAYER M4 ;
        RECT  0 148.764 0.192 148.788 ;
    END
  END rsp_data[432]
  PIN rsp_data[433]
    DIRECTION INPUT ;
    USE SIGNAL ;
    PORT
      LAYER M4 ;
        RECT  0 149.052 0.192 149.076 ;
    END
  END rsp_data[433]
  PIN rsp_data[434]
    DIRECTION INPUT ;
    USE SIGNAL ;
    PORT
      LAYER M4 ;
        RECT  0 149.292 0.192 149.316 ;
    END
  END rsp_data[434]
  PIN rsp_data[435]
    DIRECTION INPUT ;
    USE SIGNAL ;
    PORT
      LAYER M4 ;
        RECT  0 149.58 0.192 149.604 ;
    END
  END rsp_data[435]
  PIN rsp_data[436]
    DIRECTION INPUT ;
    USE SIGNAL ;
    PORT
      LAYER M4 ;
        RECT  0 149.868 0.192 149.892 ;
    END
  END rsp_data[436]
  PIN rsp_data[437]
    DIRECTION INPUT ;
    USE SIGNAL ;
    PORT
      LAYER M4 ;
        RECT  0 150.156 0.192 150.18 ;
    END
  END rsp_data[437]
  PIN rsp_data[438]
    DIRECTION INPUT ;
    USE SIGNAL ;
    PORT
      LAYER M4 ;
        RECT  0 150.396 0.192 150.42 ;
    END
  END rsp_data[438]
  PIN rsp_data[439]
    DIRECTION INPUT ;
    USE SIGNAL ;
    PORT
      LAYER M4 ;
        RECT  0 150.684 0.192 150.708 ;
    END
  END rsp_data[439]
  PIN rsp_data[43]
    DIRECTION INPUT ;
    USE SIGNAL ;
    PORT
      LAYER M4 ;
        RECT  0 40.908 0.192 40.932 ;
    END
  END rsp_data[43]
  PIN rsp_data[440]
    DIRECTION INPUT ;
    USE SIGNAL ;
    PORT
      LAYER M4 ;
        RECT  0 150.972 0.192 150.996 ;
    END
  END rsp_data[440]
  PIN rsp_data[441]
    DIRECTION INPUT ;
    USE SIGNAL ;
    PORT
      LAYER M4 ;
        RECT  0 151.26 0.192 151.284 ;
    END
  END rsp_data[441]
  PIN rsp_data[442]
    DIRECTION INPUT ;
    USE SIGNAL ;
    PORT
      LAYER M4 ;
        RECT  0 151.548 0.192 151.572 ;
    END
  END rsp_data[442]
  PIN rsp_data[443]
    DIRECTION INPUT ;
    USE SIGNAL ;
    PORT
      LAYER M4 ;
        RECT  0 151.788 0.192 151.812 ;
    END
  END rsp_data[443]
  PIN rsp_data[444]
    DIRECTION INPUT ;
    USE SIGNAL ;
    PORT
      LAYER M4 ;
        RECT  0 152.076 0.192 152.1 ;
    END
  END rsp_data[444]
  PIN rsp_data[445]
    DIRECTION INPUT ;
    USE SIGNAL ;
    PORT
      LAYER M4 ;
        RECT  0 152.364 0.192 152.388 ;
    END
  END rsp_data[445]
  PIN rsp_data[446]
    DIRECTION INPUT ;
    USE SIGNAL ;
    PORT
      LAYER M4 ;
        RECT  0 152.652 0.192 152.676 ;
    END
  END rsp_data[446]
  PIN rsp_data[447]
    DIRECTION INPUT ;
    USE SIGNAL ;
    PORT
      LAYER M4 ;
        RECT  0 152.892 0.192 152.916 ;
    END
  END rsp_data[447]
  PIN rsp_data[448]
    DIRECTION INPUT ;
    USE SIGNAL ;
    PORT
      LAYER M4 ;
        RECT  0 153.18 0.192 153.204 ;
    END
  END rsp_data[448]
  PIN rsp_data[449]
    DIRECTION INPUT ;
    USE SIGNAL ;
    PORT
      LAYER M4 ;
        RECT  0 153.468 0.192 153.492 ;
    END
  END rsp_data[449]
  PIN rsp_data[44]
    DIRECTION INPUT ;
    USE SIGNAL ;
    PORT
      LAYER M4 ;
        RECT  0 41.196 0.192 41.22 ;
    END
  END rsp_data[44]
  PIN rsp_data[450]
    DIRECTION INPUT ;
    USE SIGNAL ;
    PORT
      LAYER M4 ;
        RECT  0 153.756 0.192 153.78 ;
    END
  END rsp_data[450]
  PIN rsp_data[451]
    DIRECTION INPUT ;
    USE SIGNAL ;
    PORT
      LAYER M4 ;
        RECT  0 153.996 0.192 154.02 ;
    END
  END rsp_data[451]
  PIN rsp_data[452]
    DIRECTION INPUT ;
    USE SIGNAL ;
    PORT
      LAYER M4 ;
        RECT  0 154.284 0.192 154.308 ;
    END
  END rsp_data[452]
  PIN rsp_data[453]
    DIRECTION INPUT ;
    USE SIGNAL ;
    PORT
      LAYER M4 ;
        RECT  0 154.572 0.192 154.596 ;
    END
  END rsp_data[453]
  PIN rsp_data[454]
    DIRECTION INPUT ;
    USE SIGNAL ;
    PORT
      LAYER M4 ;
        RECT  0 154.86 0.192 154.884 ;
    END
  END rsp_data[454]
  PIN rsp_data[455]
    DIRECTION INPUT ;
    USE SIGNAL ;
    PORT
      LAYER M4 ;
        RECT  0 155.148 0.192 155.172 ;
    END
  END rsp_data[455]
  PIN rsp_data[456]
    DIRECTION INPUT ;
    USE SIGNAL ;
    PORT
      LAYER M4 ;
        RECT  0 155.388 0.192 155.412 ;
    END
  END rsp_data[456]
  PIN rsp_data[457]
    DIRECTION INPUT ;
    USE SIGNAL ;
    PORT
      LAYER M4 ;
        RECT  0 155.676 0.192 155.7 ;
    END
  END rsp_data[457]
  PIN rsp_data[458]
    DIRECTION INPUT ;
    USE SIGNAL ;
    PORT
      LAYER M4 ;
        RECT  0 155.964 0.192 155.988 ;
    END
  END rsp_data[458]
  PIN rsp_data[459]
    DIRECTION INPUT ;
    USE SIGNAL ;
    PORT
      LAYER M4 ;
        RECT  0 156.252 0.192 156.276 ;
    END
  END rsp_data[459]
  PIN rsp_data[45]
    DIRECTION INPUT ;
    USE SIGNAL ;
    PORT
      LAYER M4 ;
        RECT  0 41.484 0.192 41.508 ;
    END
  END rsp_data[45]
  PIN rsp_data[460]
    DIRECTION INPUT ;
    USE SIGNAL ;
    PORT
      LAYER M4 ;
        RECT  0 156.492 0.192 156.516 ;
    END
  END rsp_data[460]
  PIN rsp_data[461]
    DIRECTION INPUT ;
    USE SIGNAL ;
    PORT
      LAYER M4 ;
        RECT  0 156.78 0.192 156.804 ;
    END
  END rsp_data[461]
  PIN rsp_data[462]
    DIRECTION INPUT ;
    USE SIGNAL ;
    PORT
      LAYER M4 ;
        RECT  0 157.068 0.192 157.092 ;
    END
  END rsp_data[462]
  PIN rsp_data[463]
    DIRECTION INPUT ;
    USE SIGNAL ;
    PORT
      LAYER M4 ;
        RECT  0 157.356 0.192 157.38 ;
    END
  END rsp_data[463]
  PIN rsp_data[464]
    DIRECTION INPUT ;
    USE SIGNAL ;
    PORT
      LAYER M4 ;
        RECT  0 157.644 0.192 157.668 ;
    END
  END rsp_data[464]
  PIN rsp_data[465]
    DIRECTION INPUT ;
    USE SIGNAL ;
    PORT
      LAYER M4 ;
        RECT  0 157.884 0.192 157.908 ;
    END
  END rsp_data[465]
  PIN rsp_data[466]
    DIRECTION INPUT ;
    USE SIGNAL ;
    PORT
      LAYER M4 ;
        RECT  0 158.172 0.192 158.196 ;
    END
  END rsp_data[466]
  PIN rsp_data[467]
    DIRECTION INPUT ;
    USE SIGNAL ;
    PORT
      LAYER M4 ;
        RECT  0 158.46 0.192 158.484 ;
    END
  END rsp_data[467]
  PIN rsp_data[468]
    DIRECTION INPUT ;
    USE SIGNAL ;
    PORT
      LAYER M4 ;
        RECT  0 158.748 0.192 158.772 ;
    END
  END rsp_data[468]
  PIN rsp_data[469]
    DIRECTION INPUT ;
    USE SIGNAL ;
    PORT
      LAYER M4 ;
        RECT  0 158.988 0.192 159.012 ;
    END
  END rsp_data[469]
  PIN rsp_data[46]
    DIRECTION INPUT ;
    USE SIGNAL ;
    PORT
      LAYER M4 ;
        RECT  0 41.772 0.192 41.796 ;
    END
  END rsp_data[46]
  PIN rsp_data[470]
    DIRECTION INPUT ;
    USE SIGNAL ;
    PORT
      LAYER M4 ;
        RECT  0 159.276 0.192 159.3 ;
    END
  END rsp_data[470]
  PIN rsp_data[471]
    DIRECTION INPUT ;
    USE SIGNAL ;
    PORT
      LAYER M4 ;
        RECT  0 159.564 0.192 159.588 ;
    END
  END rsp_data[471]
  PIN rsp_data[472]
    DIRECTION INPUT ;
    USE SIGNAL ;
    PORT
      LAYER M4 ;
        RECT  0 159.852 0.192 159.876 ;
    END
  END rsp_data[472]
  PIN rsp_data[473]
    DIRECTION INPUT ;
    USE SIGNAL ;
    PORT
      LAYER M4 ;
        RECT  0 160.14 0.192 160.164 ;
    END
  END rsp_data[473]
  PIN rsp_data[474]
    DIRECTION INPUT ;
    USE SIGNAL ;
    PORT
      LAYER M4 ;
        RECT  0 160.38 0.192 160.404 ;
    END
  END rsp_data[474]
  PIN rsp_data[475]
    DIRECTION INPUT ;
    USE SIGNAL ;
    PORT
      LAYER M4 ;
        RECT  0 160.668 0.192 160.692 ;
    END
  END rsp_data[475]
  PIN rsp_data[476]
    DIRECTION INPUT ;
    USE SIGNAL ;
    PORT
      LAYER M4 ;
        RECT  0 160.956 0.192 160.98 ;
    END
  END rsp_data[476]
  PIN rsp_data[477]
    DIRECTION INPUT ;
    USE SIGNAL ;
    PORT
      LAYER M4 ;
        RECT  0 161.244 0.192 161.268 ;
    END
  END rsp_data[477]
  PIN rsp_data[478]
    DIRECTION INPUT ;
    USE SIGNAL ;
    PORT
      LAYER M4 ;
        RECT  0 161.484 0.192 161.508 ;
    END
  END rsp_data[478]
  PIN rsp_data[479]
    DIRECTION INPUT ;
    USE SIGNAL ;
    PORT
      LAYER M4 ;
        RECT  0 161.772 0.192 161.796 ;
    END
  END rsp_data[479]
  PIN rsp_data[47]
    DIRECTION INPUT ;
    USE SIGNAL ;
    PORT
      LAYER M4 ;
        RECT  0 42.06 0.192 42.084 ;
    END
  END rsp_data[47]
  PIN rsp_data[480]
    DIRECTION INPUT ;
    USE SIGNAL ;
    PORT
      LAYER M4 ;
        RECT  0 162.06 0.192 162.084 ;
    END
  END rsp_data[480]
  PIN rsp_data[481]
    DIRECTION INPUT ;
    USE SIGNAL ;
    PORT
      LAYER M4 ;
        RECT  0 162.348 0.192 162.372 ;
    END
  END rsp_data[481]
  PIN rsp_data[482]
    DIRECTION INPUT ;
    USE SIGNAL ;
    PORT
      LAYER M4 ;
        RECT  0 162.588 0.192 162.612 ;
    END
  END rsp_data[482]
  PIN rsp_data[483]
    DIRECTION INPUT ;
    USE SIGNAL ;
    PORT
      LAYER M4 ;
        RECT  0 162.876 0.192 162.9 ;
    END
  END rsp_data[483]
  PIN rsp_data[484]
    DIRECTION INPUT ;
    USE SIGNAL ;
    PORT
      LAYER M4 ;
        RECT  0 163.164 0.192 163.188 ;
    END
  END rsp_data[484]
  PIN rsp_data[485]
    DIRECTION INPUT ;
    USE SIGNAL ;
    PORT
      LAYER M4 ;
        RECT  0 163.452 0.192 163.476 ;
    END
  END rsp_data[485]
  PIN rsp_data[486]
    DIRECTION INPUT ;
    USE SIGNAL ;
    PORT
      LAYER M4 ;
        RECT  0 163.74 0.192 163.764 ;
    END
  END rsp_data[486]
  PIN rsp_data[487]
    DIRECTION INPUT ;
    USE SIGNAL ;
    PORT
      LAYER M4 ;
        RECT  0 163.98 0.192 164.004 ;
    END
  END rsp_data[487]
  PIN rsp_data[488]
    DIRECTION INPUT ;
    USE SIGNAL ;
    PORT
      LAYER M4 ;
        RECT  0 164.268 0.192 164.292 ;
    END
  END rsp_data[488]
  PIN rsp_data[489]
    DIRECTION INPUT ;
    USE SIGNAL ;
    PORT
      LAYER M4 ;
        RECT  0 164.556 0.192 164.58 ;
    END
  END rsp_data[489]
  PIN rsp_data[48]
    DIRECTION INPUT ;
    USE SIGNAL ;
    PORT
      LAYER M4 ;
        RECT  0 42.3 0.192 42.324 ;
    END
  END rsp_data[48]
  PIN rsp_data[490]
    DIRECTION INPUT ;
    USE SIGNAL ;
    PORT
      LAYER M4 ;
        RECT  0 164.844 0.192 164.868 ;
    END
  END rsp_data[490]
  PIN rsp_data[491]
    DIRECTION INPUT ;
    USE SIGNAL ;
    PORT
      LAYER M4 ;
        RECT  0 165.084 0.192 165.108 ;
    END
  END rsp_data[491]
  PIN rsp_data[492]
    DIRECTION INPUT ;
    USE SIGNAL ;
    PORT
      LAYER M4 ;
        RECT  0 165.372 0.192 165.396 ;
    END
  END rsp_data[492]
  PIN rsp_data[493]
    DIRECTION INPUT ;
    USE SIGNAL ;
    PORT
      LAYER M4 ;
        RECT  0 165.66 0.192 165.684 ;
    END
  END rsp_data[493]
  PIN rsp_data[494]
    DIRECTION INPUT ;
    USE SIGNAL ;
    PORT
      LAYER M4 ;
        RECT  0 165.948 0.192 165.972 ;
    END
  END rsp_data[494]
  PIN rsp_data[495]
    DIRECTION INPUT ;
    USE SIGNAL ;
    PORT
      LAYER M4 ;
        RECT  0 166.236 0.192 166.26 ;
    END
  END rsp_data[495]
  PIN rsp_data[496]
    DIRECTION INPUT ;
    USE SIGNAL ;
    PORT
      LAYER M4 ;
        RECT  0 166.476 0.192 166.5 ;
    END
  END rsp_data[496]
  PIN rsp_data[497]
    DIRECTION INPUT ;
    USE SIGNAL ;
    PORT
      LAYER M4 ;
        RECT  0 166.764 0.192 166.788 ;
    END
  END rsp_data[497]
  PIN rsp_data[498]
    DIRECTION INPUT ;
    USE SIGNAL ;
    PORT
      LAYER M4 ;
        RECT  0 167.052 0.192 167.076 ;
    END
  END rsp_data[498]
  PIN rsp_data[499]
    DIRECTION INPUT ;
    USE SIGNAL ;
    PORT
      LAYER M4 ;
        RECT  0 167.34 0.192 167.364 ;
    END
  END rsp_data[499]
  PIN rsp_data[49]
    DIRECTION INPUT ;
    USE SIGNAL ;
    PORT
      LAYER M4 ;
        RECT  0 42.588 0.192 42.612 ;
    END
  END rsp_data[49]
  PIN rsp_data[4]
    DIRECTION INPUT ;
    USE SIGNAL ;
    PORT
      LAYER M4 ;
        RECT  0 30.108 0.192 30.132 ;
    END
  END rsp_data[4]
  PIN rsp_data[500]
    DIRECTION INPUT ;
    USE SIGNAL ;
    PORT
      LAYER M4 ;
        RECT  0 167.58 0.192 167.604 ;
    END
  END rsp_data[500]
  PIN rsp_data[501]
    DIRECTION INPUT ;
    USE SIGNAL ;
    PORT
      LAYER M4 ;
        RECT  0 167.868 0.192 167.892 ;
    END
  END rsp_data[501]
  PIN rsp_data[502]
    DIRECTION INPUT ;
    USE SIGNAL ;
    PORT
      LAYER M4 ;
        RECT  0 168.156 0.192 168.18 ;
    END
  END rsp_data[502]
  PIN rsp_data[503]
    DIRECTION INPUT ;
    USE SIGNAL ;
    PORT
      LAYER M4 ;
        RECT  0 168.444 0.192 168.468 ;
    END
  END rsp_data[503]
  PIN rsp_data[504]
    DIRECTION INPUT ;
    USE SIGNAL ;
    PORT
      LAYER M4 ;
        RECT  0 168.732 0.192 168.756 ;
    END
  END rsp_data[504]
  PIN rsp_data[505]
    DIRECTION INPUT ;
    USE SIGNAL ;
    PORT
      LAYER M4 ;
        RECT  0 168.972 0.192 168.996 ;
    END
  END rsp_data[505]
  PIN rsp_data[506]
    DIRECTION INPUT ;
    USE SIGNAL ;
    PORT
      LAYER M4 ;
        RECT  0 169.26 0.192 169.284 ;
    END
  END rsp_data[506]
  PIN rsp_data[507]
    DIRECTION INPUT ;
    USE SIGNAL ;
    PORT
      LAYER M4 ;
        RECT  0 169.548 0.192 169.572 ;
    END
  END rsp_data[507]
  PIN rsp_data[508]
    DIRECTION INPUT ;
    USE SIGNAL ;
    PORT
      LAYER M4 ;
        RECT  0 169.836 0.192 169.86 ;
    END
  END rsp_data[508]
  PIN rsp_data[509]
    DIRECTION INPUT ;
    USE SIGNAL ;
    PORT
      LAYER M4 ;
        RECT  0 170.076 0.192 170.1 ;
    END
  END rsp_data[509]
  PIN rsp_data[50]
    DIRECTION INPUT ;
    USE SIGNAL ;
    PORT
      LAYER M4 ;
        RECT  0 42.876 0.192 42.9 ;
    END
  END rsp_data[50]
  PIN rsp_data[510]
    DIRECTION INPUT ;
    USE SIGNAL ;
    PORT
      LAYER M4 ;
        RECT  0 170.364 0.192 170.388 ;
    END
  END rsp_data[510]
  PIN rsp_data[511]
    DIRECTION INPUT ;
    USE SIGNAL ;
    PORT
      LAYER M4 ;
        RECT  0 170.652 0.192 170.676 ;
    END
  END rsp_data[511]
  PIN rsp_data[51]
    DIRECTION INPUT ;
    USE SIGNAL ;
    PORT
      LAYER M4 ;
        RECT  0 43.164 0.192 43.188 ;
    END
  END rsp_data[51]
  PIN rsp_data[52]
    DIRECTION INPUT ;
    USE SIGNAL ;
    PORT
      LAYER M4 ;
        RECT  0 43.404 0.192 43.428 ;
    END
  END rsp_data[52]
  PIN rsp_data[53]
    DIRECTION INPUT ;
    USE SIGNAL ;
    PORT
      LAYER M4 ;
        RECT  0 43.692 0.192 43.716 ;
    END
  END rsp_data[53]
  PIN rsp_data[54]
    DIRECTION INPUT ;
    USE SIGNAL ;
    PORT
      LAYER M4 ;
        RECT  0 43.98 0.192 44.004 ;
    END
  END rsp_data[54]
  PIN rsp_data[55]
    DIRECTION INPUT ;
    USE SIGNAL ;
    PORT
      LAYER M4 ;
        RECT  0 44.268 0.192 44.292 ;
    END
  END rsp_data[55]
  PIN rsp_data[56]
    DIRECTION INPUT ;
    USE SIGNAL ;
    PORT
      LAYER M4 ;
        RECT  0 44.556 0.192 44.58 ;
    END
  END rsp_data[56]
  PIN rsp_data[57]
    DIRECTION INPUT ;
    USE SIGNAL ;
    PORT
      LAYER M4 ;
        RECT  0 44.796 0.192 44.82 ;
    END
  END rsp_data[57]
  PIN rsp_data[58]
    DIRECTION INPUT ;
    USE SIGNAL ;
    PORT
      LAYER M4 ;
        RECT  0 45.084 0.192 45.108 ;
    END
  END rsp_data[58]
  PIN rsp_data[59]
    DIRECTION INPUT ;
    USE SIGNAL ;
    PORT
      LAYER M4 ;
        RECT  0 45.372 0.192 45.396 ;
    END
  END rsp_data[59]
  PIN rsp_data[5]
    DIRECTION INPUT ;
    USE SIGNAL ;
    PORT
      LAYER M4 ;
        RECT  0 30.396 0.192 30.42 ;
    END
  END rsp_data[5]
  PIN rsp_data[60]
    DIRECTION INPUT ;
    USE SIGNAL ;
    PORT
      LAYER M4 ;
        RECT  0 45.66 0.192 45.684 ;
    END
  END rsp_data[60]
  PIN rsp_data[61]
    DIRECTION INPUT ;
    USE SIGNAL ;
    PORT
      LAYER M4 ;
        RECT  0 45.9 0.192 45.924 ;
    END
  END rsp_data[61]
  PIN rsp_data[62]
    DIRECTION INPUT ;
    USE SIGNAL ;
    PORT
      LAYER M4 ;
        RECT  0 46.188 0.192 46.212 ;
    END
  END rsp_data[62]
  PIN rsp_data[63]
    DIRECTION INPUT ;
    USE SIGNAL ;
    PORT
      LAYER M4 ;
        RECT  0 46.476 0.192 46.5 ;
    END
  END rsp_data[63]
  PIN rsp_data[64]
    DIRECTION INPUT ;
    USE SIGNAL ;
    PORT
      LAYER M4 ;
        RECT  0 46.764 0.192 46.788 ;
    END
  END rsp_data[64]
  PIN rsp_data[65]
    DIRECTION INPUT ;
    USE SIGNAL ;
    PORT
      LAYER M4 ;
        RECT  0 47.052 0.192 47.076 ;
    END
  END rsp_data[65]
  PIN rsp_data[66]
    DIRECTION INPUT ;
    USE SIGNAL ;
    PORT
      LAYER M4 ;
        RECT  0 47.292 0.192 47.316 ;
    END
  END rsp_data[66]
  PIN rsp_data[67]
    DIRECTION INPUT ;
    USE SIGNAL ;
    PORT
      LAYER M4 ;
        RECT  0 47.58 0.192 47.604 ;
    END
  END rsp_data[67]
  PIN rsp_data[68]
    DIRECTION INPUT ;
    USE SIGNAL ;
    PORT
      LAYER M4 ;
        RECT  0 47.868 0.192 47.892 ;
    END
  END rsp_data[68]
  PIN rsp_data[69]
    DIRECTION INPUT ;
    USE SIGNAL ;
    PORT
      LAYER M4 ;
        RECT  0 48.156 0.192 48.18 ;
    END
  END rsp_data[69]
  PIN rsp_data[6]
    DIRECTION INPUT ;
    USE SIGNAL ;
    PORT
      LAYER M4 ;
        RECT  0 30.684 0.192 30.708 ;
    END
  END rsp_data[6]
  PIN rsp_data[70]
    DIRECTION INPUT ;
    USE SIGNAL ;
    PORT
      LAYER M4 ;
        RECT  0 48.396 0.192 48.42 ;
    END
  END rsp_data[70]
  PIN rsp_data[71]
    DIRECTION INPUT ;
    USE SIGNAL ;
    PORT
      LAYER M4 ;
        RECT  0 48.684 0.192 48.708 ;
    END
  END rsp_data[71]
  PIN rsp_data[72]
    DIRECTION INPUT ;
    USE SIGNAL ;
    PORT
      LAYER M4 ;
        RECT  0 48.972 0.192 48.996 ;
    END
  END rsp_data[72]
  PIN rsp_data[73]
    DIRECTION INPUT ;
    USE SIGNAL ;
    PORT
      LAYER M4 ;
        RECT  0 49.26 0.192 49.284 ;
    END
  END rsp_data[73]
  PIN rsp_data[74]
    DIRECTION INPUT ;
    USE SIGNAL ;
    PORT
      LAYER M4 ;
        RECT  0 49.5 0.192 49.524 ;
    END
  END rsp_data[74]
  PIN rsp_data[75]
    DIRECTION INPUT ;
    USE SIGNAL ;
    PORT
      LAYER M4 ;
        RECT  0 49.788 0.192 49.812 ;
    END
  END rsp_data[75]
  PIN rsp_data[76]
    DIRECTION INPUT ;
    USE SIGNAL ;
    PORT
      LAYER M4 ;
        RECT  0 50.076 0.192 50.1 ;
    END
  END rsp_data[76]
  PIN rsp_data[77]
    DIRECTION INPUT ;
    USE SIGNAL ;
    PORT
      LAYER M4 ;
        RECT  0 50.364 0.192 50.388 ;
    END
  END rsp_data[77]
  PIN rsp_data[78]
    DIRECTION INPUT ;
    USE SIGNAL ;
    PORT
      LAYER M4 ;
        RECT  0 50.652 0.192 50.676 ;
    END
  END rsp_data[78]
  PIN rsp_data[79]
    DIRECTION INPUT ;
    USE SIGNAL ;
    PORT
      LAYER M4 ;
        RECT  0 50.892 0.192 50.916 ;
    END
  END rsp_data[79]
  PIN rsp_data[7]
    DIRECTION INPUT ;
    USE SIGNAL ;
    PORT
      LAYER M4 ;
        RECT  0 30.972 0.192 30.996 ;
    END
  END rsp_data[7]
  PIN rsp_data[80]
    DIRECTION INPUT ;
    USE SIGNAL ;
    PORT
      LAYER M4 ;
        RECT  0 51.18 0.192 51.204 ;
    END
  END rsp_data[80]
  PIN rsp_data[81]
    DIRECTION INPUT ;
    USE SIGNAL ;
    PORT
      LAYER M4 ;
        RECT  0 51.468 0.192 51.492 ;
    END
  END rsp_data[81]
  PIN rsp_data[82]
    DIRECTION INPUT ;
    USE SIGNAL ;
    PORT
      LAYER M4 ;
        RECT  0 51.756 0.192 51.78 ;
    END
  END rsp_data[82]
  PIN rsp_data[83]
    DIRECTION INPUT ;
    USE SIGNAL ;
    PORT
      LAYER M4 ;
        RECT  0 51.996 0.192 52.02 ;
    END
  END rsp_data[83]
  PIN rsp_data[84]
    DIRECTION INPUT ;
    USE SIGNAL ;
    PORT
      LAYER M4 ;
        RECT  0 52.284 0.192 52.308 ;
    END
  END rsp_data[84]
  PIN rsp_data[85]
    DIRECTION INPUT ;
    USE SIGNAL ;
    PORT
      LAYER M4 ;
        RECT  0 52.572 0.192 52.596 ;
    END
  END rsp_data[85]
  PIN rsp_data[86]
    DIRECTION INPUT ;
    USE SIGNAL ;
    PORT
      LAYER M4 ;
        RECT  0 52.86 0.192 52.884 ;
    END
  END rsp_data[86]
  PIN rsp_data[87]
    DIRECTION INPUT ;
    USE SIGNAL ;
    PORT
      LAYER M4 ;
        RECT  0 53.148 0.192 53.172 ;
    END
  END rsp_data[87]
  PIN rsp_data[88]
    DIRECTION INPUT ;
    USE SIGNAL ;
    PORT
      LAYER M4 ;
        RECT  0 53.388 0.192 53.412 ;
    END
  END rsp_data[88]
  PIN rsp_data[89]
    DIRECTION INPUT ;
    USE SIGNAL ;
    PORT
      LAYER M4 ;
        RECT  0 53.676 0.192 53.7 ;
    END
  END rsp_data[89]
  PIN rsp_data[8]
    DIRECTION INPUT ;
    USE SIGNAL ;
    PORT
      LAYER M4 ;
        RECT  0 31.212 0.192 31.236 ;
    END
  END rsp_data[8]
  PIN rsp_data[90]
    DIRECTION INPUT ;
    USE SIGNAL ;
    PORT
      LAYER M4 ;
        RECT  0 53.964 0.192 53.988 ;
    END
  END rsp_data[90]
  PIN rsp_data[91]
    DIRECTION INPUT ;
    USE SIGNAL ;
    PORT
      LAYER M4 ;
        RECT  0 54.252 0.192 54.276 ;
    END
  END rsp_data[91]
  PIN rsp_data[92]
    DIRECTION INPUT ;
    USE SIGNAL ;
    PORT
      LAYER M4 ;
        RECT  0 54.492 0.192 54.516 ;
    END
  END rsp_data[92]
  PIN rsp_data[93]
    DIRECTION INPUT ;
    USE SIGNAL ;
    PORT
      LAYER M4 ;
        RECT  0 54.78 0.192 54.804 ;
    END
  END rsp_data[93]
  PIN rsp_data[94]
    DIRECTION INPUT ;
    USE SIGNAL ;
    PORT
      LAYER M4 ;
        RECT  0 55.068 0.192 55.092 ;
    END
  END rsp_data[94]
  PIN rsp_data[95]
    DIRECTION INPUT ;
    USE SIGNAL ;
    PORT
      LAYER M4 ;
        RECT  0 55.356 0.192 55.38 ;
    END
  END rsp_data[95]
  PIN rsp_data[96]
    DIRECTION INPUT ;
    USE SIGNAL ;
    PORT
      LAYER M4 ;
        RECT  0 55.644 0.192 55.668 ;
    END
  END rsp_data[96]
  PIN rsp_data[97]
    DIRECTION INPUT ;
    USE SIGNAL ;
    PORT
      LAYER M4 ;
        RECT  0 55.884 0.192 55.908 ;
    END
  END rsp_data[97]
  PIN rsp_data[98]
    DIRECTION INPUT ;
    USE SIGNAL ;
    PORT
      LAYER M4 ;
        RECT  0 56.172 0.192 56.196 ;
    END
  END rsp_data[98]
  PIN rsp_data[99]
    DIRECTION INPUT ;
    USE SIGNAL ;
    PORT
      LAYER M4 ;
        RECT  0 56.46 0.192 56.484 ;
    END
  END rsp_data[99]
  PIN rsp_data[9]
    DIRECTION INPUT ;
    USE SIGNAL ;
    PORT
      LAYER M4 ;
        RECT  0 31.5 0.192 31.524 ;
    END
  END rsp_data[9]
  PIN rsp_epoch[0]
    DIRECTION INPUT ;
    USE SIGNAL ;
    PORT
      LAYER M5 ;
        RECT  2.124 0 2.148 0.192 ;
    END
  END rsp_epoch[0]
  PIN rsp_epoch[10]
    DIRECTION INPUT ;
    USE SIGNAL ;
    PORT
      LAYER M5 ;
        RECT  4.86 0 4.884 0.192 ;
    END
  END rsp_epoch[10]
  PIN rsp_epoch[11]
    DIRECTION INPUT ;
    USE SIGNAL ;
    PORT
      LAYER M5 ;
        RECT  5.148 0 5.172 0.192 ;
    END
  END rsp_epoch[11]
  PIN rsp_epoch[12]
    DIRECTION INPUT ;
    USE SIGNAL ;
    PORT
      LAYER M5 ;
        RECT  5.436 0 5.46 0.192 ;
    END
  END rsp_epoch[12]
  PIN rsp_epoch[13]
    DIRECTION INPUT ;
    USE SIGNAL ;
    PORT
      LAYER M5 ;
        RECT  5.676 0 5.7 0.192 ;
    END
  END rsp_epoch[13]
  PIN rsp_epoch[14]
    DIRECTION INPUT ;
    USE SIGNAL ;
    PORT
      LAYER M5 ;
        RECT  5.964 0 5.988 0.192 ;
    END
  END rsp_epoch[14]
  PIN rsp_epoch[15]
    DIRECTION INPUT ;
    USE SIGNAL ;
    PORT
      LAYER M5 ;
        RECT  6.252 0 6.276 0.192 ;
    END
  END rsp_epoch[15]
  PIN rsp_epoch[1]
    DIRECTION INPUT ;
    USE SIGNAL ;
    PORT
      LAYER M5 ;
        RECT  2.412 0 2.436 0.192 ;
    END
  END rsp_epoch[1]
  PIN rsp_epoch[2]
    DIRECTION INPUT ;
    USE SIGNAL ;
    PORT
      LAYER M5 ;
        RECT  2.652 0 2.676 0.192 ;
    END
  END rsp_epoch[2]
  PIN rsp_epoch[3]
    DIRECTION INPUT ;
    USE SIGNAL ;
    PORT
      LAYER M5 ;
        RECT  2.94 0 2.964 0.192 ;
    END
  END rsp_epoch[3]
  PIN rsp_epoch[4]
    DIRECTION INPUT ;
    USE SIGNAL ;
    PORT
      LAYER M5 ;
        RECT  3.228 0 3.252 0.192 ;
    END
  END rsp_epoch[4]
  PIN rsp_epoch[5]
    DIRECTION INPUT ;
    USE SIGNAL ;
    PORT
      LAYER M5 ;
        RECT  3.516 0 3.54 0.192 ;
    END
  END rsp_epoch[5]
  PIN rsp_epoch[6]
    DIRECTION INPUT ;
    USE SIGNAL ;
    PORT
      LAYER M5 ;
        RECT  3.756 0 3.78 0.192 ;
    END
  END rsp_epoch[6]
  PIN rsp_epoch[7]
    DIRECTION INPUT ;
    USE SIGNAL ;
    PORT
      LAYER M5 ;
        RECT  4.044 0 4.068 0.192 ;
    END
  END rsp_epoch[7]
  PIN rsp_epoch[8]
    DIRECTION INPUT ;
    USE SIGNAL ;
    PORT
      LAYER M5 ;
        RECT  4.332 0 4.356 0.192 ;
    END
  END rsp_epoch[8]
  PIN rsp_epoch[9]
    DIRECTION INPUT ;
    USE SIGNAL ;
    PORT
      LAYER M5 ;
        RECT  4.62 0 4.644 0.192 ;
    END
  END rsp_epoch[9]
  PIN rsp_layer[0]
    DIRECTION INPUT ;
    USE SIGNAL ;
    PORT
      LAYER M5 ;
        RECT  6.54 0 6.564 0.192 ;
    END
  END rsp_layer[0]
  PIN rsp_layer[1]
    DIRECTION INPUT ;
    USE SIGNAL ;
    PORT
      LAYER M5 ;
        RECT  6.78 0 6.804 0.192 ;
    END
  END rsp_layer[1]
  PIN rsp_layer[2]
    DIRECTION INPUT ;
    USE SIGNAL ;
    PORT
      LAYER M5 ;
        RECT  7.068 0 7.092 0.192 ;
    END
  END rsp_layer[2]
  PIN rsp_layer[3]
    DIRECTION INPUT ;
    USE SIGNAL ;
    PORT
      LAYER M5 ;
        RECT  7.356 0 7.38 0.192 ;
    END
  END rsp_layer[3]
  PIN rsp_layer[4]
    DIRECTION INPUT ;
    USE SIGNAL ;
    PORT
      LAYER M5 ;
        RECT  7.596 0 7.62 0.192 ;
    END
  END rsp_layer[4]
  PIN rsp_layer[5]
    DIRECTION INPUT ;
    USE SIGNAL ;
    PORT
      LAYER M5 ;
        RECT  7.884 0 7.908 0.192 ;
    END
  END rsp_layer[5]
  PIN rsp_t[0]
    DIRECTION INPUT ;
    USE SIGNAL ;
    PORT
      LAYER M5 ;
        RECT  8.172 0 8.196 0.192 ;
    END
  END rsp_t[0]
  PIN rsp_t[10]
    DIRECTION INPUT ;
    USE SIGNAL ;
    PORT
      LAYER M5 ;
        RECT  10.908 0 10.932 0.192 ;
    END
  END rsp_t[10]
  PIN rsp_t[11]
    DIRECTION INPUT ;
    USE SIGNAL ;
    PORT
      LAYER M5 ;
        RECT  11.196 0 11.22 0.192 ;
    END
  END rsp_t[11]
  PIN rsp_t[12]
    DIRECTION INPUT ;
    USE SIGNAL ;
    PORT
      LAYER M5 ;
        RECT  11.484 0 11.508 0.192 ;
    END
  END rsp_t[12]
  PIN rsp_t[13]
    DIRECTION INPUT ;
    USE SIGNAL ;
    PORT
      LAYER M5 ;
        RECT  11.724 0 11.748 0.192 ;
    END
  END rsp_t[13]
  PIN rsp_t[1]
    DIRECTION INPUT ;
    USE SIGNAL ;
    PORT
      LAYER M5 ;
        RECT  8.46 0 8.484 0.192 ;
    END
  END rsp_t[1]
  PIN rsp_t[2]
    DIRECTION INPUT ;
    USE SIGNAL ;
    PORT
      LAYER M5 ;
        RECT  8.7 0 8.724 0.192 ;
    END
  END rsp_t[2]
  PIN rsp_t[3]
    DIRECTION INPUT ;
    USE SIGNAL ;
    PORT
      LAYER M5 ;
        RECT  8.988 0 9.012 0.192 ;
    END
  END rsp_t[3]
  PIN rsp_t[4]
    DIRECTION INPUT ;
    USE SIGNAL ;
    PORT
      LAYER M5 ;
        RECT  9.276 0 9.3 0.192 ;
    END
  END rsp_t[4]
  PIN rsp_t[5]
    DIRECTION INPUT ;
    USE SIGNAL ;
    PORT
      LAYER M5 ;
        RECT  9.516 0 9.54 0.192 ;
    END
  END rsp_t[5]
  PIN rsp_t[6]
    DIRECTION INPUT ;
    USE SIGNAL ;
    PORT
      LAYER M5 ;
        RECT  9.804 0 9.828 0.192 ;
    END
  END rsp_t[6]
  PIN rsp_t[7]
    DIRECTION INPUT ;
    USE SIGNAL ;
    PORT
      LAYER M5 ;
        RECT  10.092 0 10.116 0.192 ;
    END
  END rsp_t[7]
  PIN rsp_t[8]
    DIRECTION INPUT ;
    USE SIGNAL ;
    PORT
      LAYER M5 ;
        RECT  10.38 0 10.404 0.192 ;
    END
  END rsp_t[8]
  PIN rsp_t[9]
    DIRECTION INPUT ;
    USE SIGNAL ;
    PORT
      LAYER M5 ;
        RECT  10.62 0 10.644 0.192 ;
    END
  END rsp_t[9]
  PIN rsp_v[0]
    DIRECTION INPUT ;
    USE SIGNAL ;
    PORT
      LAYER M5 ;
        RECT  12.012 0 12.036 0.192 ;
    END
  END rsp_v[0]
  PIN rsp_valid[0]
    DIRECTION INPUT ;
    USE SIGNAL ;
    PORT
      LAYER M5 ;
        RECT  12.3 0 12.324 0.192 ;
    END
  END rsp_valid[0]
  PIN rst_n[0]
    DIRECTION INPUT ;
    USE SIGNAL ;
    PORT
      LAYER M5 ;
        RECT  108.396 86.304 108.42 86.496 ;
    END
  END rst_n[0]
  PIN s0[0]
    DIRECTION INPUT ;
    USE SIGNAL ;
    PORT
      LAYER M4 ;
        RECT  215.808 2.892 216 2.916 ;
    END
  END s0[0]
  PIN s0[10]
    DIRECTION INPUT ;
    USE SIGNAL ;
    PORT
      LAYER M4 ;
        RECT  215.808 21.036 216 21.06 ;
    END
  END s0[10]
  PIN s0[11]
    DIRECTION INPUT ;
    USE SIGNAL ;
    PORT
      LAYER M4 ;
        RECT  215.808 22.86 216 22.884 ;
    END
  END s0[11]
  PIN s0[12]
    DIRECTION INPUT ;
    USE SIGNAL ;
    PORT
      LAYER M4 ;
        RECT  215.808 24.684 216 24.708 ;
    END
  END s0[12]
  PIN s0[13]
    DIRECTION INPUT ;
    USE SIGNAL ;
    PORT
      LAYER M4 ;
        RECT  215.808 26.508 216 26.532 ;
    END
  END s0[13]
  PIN s0[14]
    DIRECTION INPUT ;
    USE SIGNAL ;
    PORT
      LAYER M4 ;
        RECT  215.808 28.284 216 28.308 ;
    END
  END s0[14]
  PIN s0[15]
    DIRECTION INPUT ;
    USE SIGNAL ;
    PORT
      LAYER M4 ;
        RECT  215.808 30.108 216 30.132 ;
    END
  END s0[15]
  PIN s0[16]
    DIRECTION INPUT ;
    USE SIGNAL ;
    PORT
      LAYER M4 ;
        RECT  215.808 31.932 216 31.956 ;
    END
  END s0[16]
  PIN s0[17]
    DIRECTION INPUT ;
    USE SIGNAL ;
    PORT
      LAYER M4 ;
        RECT  215.808 33.756 216 33.78 ;
    END
  END s0[17]
  PIN s0[18]
    DIRECTION INPUT ;
    USE SIGNAL ;
    PORT
      LAYER M4 ;
        RECT  215.808 35.58 216 35.604 ;
    END
  END s0[18]
  PIN s0[19]
    DIRECTION INPUT ;
    USE SIGNAL ;
    PORT
      LAYER M4 ;
        RECT  215.808 37.404 216 37.428 ;
    END
  END s0[19]
  PIN s0[1]
    DIRECTION INPUT ;
    USE SIGNAL ;
    PORT
      LAYER M4 ;
        RECT  215.808 4.716 216 4.74 ;
    END
  END s0[1]
  PIN s0[20]
    DIRECTION INPUT ;
    USE SIGNAL ;
    PORT
      LAYER M4 ;
        RECT  215.808 39.18 216 39.204 ;
    END
  END s0[20]
  PIN s0[21]
    DIRECTION INPUT ;
    USE SIGNAL ;
    PORT
      LAYER M4 ;
        RECT  215.808 41.004 216 41.028 ;
    END
  END s0[21]
  PIN s0[22]
    DIRECTION INPUT ;
    USE SIGNAL ;
    PORT
      LAYER M4 ;
        RECT  215.808 42.828 216 42.852 ;
    END
  END s0[22]
  PIN s0[23]
    DIRECTION INPUT ;
    USE SIGNAL ;
    PORT
      LAYER M4 ;
        RECT  215.808 44.652 216 44.676 ;
    END
  END s0[23]
  PIN s0[24]
    DIRECTION INPUT ;
    USE SIGNAL ;
    PORT
      LAYER M4 ;
        RECT  215.808 46.476 216 46.5 ;
    END
  END s0[24]
  PIN s0[25]
    DIRECTION INPUT ;
    USE SIGNAL ;
    PORT
      LAYER M4 ;
        RECT  215.808 48.252 216 48.276 ;
    END
  END s0[25]
  PIN s0[26]
    DIRECTION INPUT ;
    USE SIGNAL ;
    PORT
      LAYER M4 ;
        RECT  215.808 50.076 216 50.1 ;
    END
  END s0[26]
  PIN s0[27]
    DIRECTION INPUT ;
    USE SIGNAL ;
    PORT
      LAYER M4 ;
        RECT  215.808 51.9 216 51.924 ;
    END
  END s0[27]
  PIN s0[28]
    DIRECTION INPUT ;
    USE SIGNAL ;
    PORT
      LAYER M4 ;
        RECT  215.808 53.724 216 53.748 ;
    END
  END s0[28]
  PIN s0[29]
    DIRECTION INPUT ;
    USE SIGNAL ;
    PORT
      LAYER M4 ;
        RECT  215.808 55.548 216 55.572 ;
    END
  END s0[29]
  PIN s0[2]
    DIRECTION INPUT ;
    USE SIGNAL ;
    PORT
      LAYER M4 ;
        RECT  215.808 6.54 216 6.564 ;
    END
  END s0[2]
  PIN s0[30]
    DIRECTION INPUT ;
    USE SIGNAL ;
    PORT
      LAYER M4 ;
        RECT  215.808 57.324 216 57.348 ;
    END
  END s0[30]
  PIN s0[31]
    DIRECTION INPUT ;
    USE SIGNAL ;
    PORT
      LAYER M4 ;
        RECT  215.808 59.148 216 59.172 ;
    END
  END s0[31]
  PIN s0[32]
    DIRECTION INPUT ;
    USE SIGNAL ;
    PORT
      LAYER M4 ;
        RECT  215.808 60.972 216 60.996 ;
    END
  END s0[32]
  PIN s0[33]
    DIRECTION INPUT ;
    USE SIGNAL ;
    PORT
      LAYER M4 ;
        RECT  215.808 62.796 216 62.82 ;
    END
  END s0[33]
  PIN s0[3]
    DIRECTION INPUT ;
    USE SIGNAL ;
    PORT
      LAYER M4 ;
        RECT  215.808 8.364 216 8.388 ;
    END
  END s0[3]
  PIN s0[4]
    DIRECTION INPUT ;
    USE SIGNAL ;
    PORT
      LAYER M4 ;
        RECT  215.808 10.14 216 10.164 ;
    END
  END s0[4]
  PIN s0[5]
    DIRECTION INPUT ;
    USE SIGNAL ;
    PORT
      LAYER M4 ;
        RECT  215.808 11.964 216 11.988 ;
    END
  END s0[5]
  PIN s0[6]
    DIRECTION INPUT ;
    USE SIGNAL ;
    PORT
      LAYER M4 ;
        RECT  215.808 13.788 216 13.812 ;
    END
  END s0[6]
  PIN s0[7]
    DIRECTION INPUT ;
    USE SIGNAL ;
    PORT
      LAYER M4 ;
        RECT  215.808 15.612 216 15.636 ;
    END
  END s0[7]
  PIN s0[8]
    DIRECTION INPUT ;
    USE SIGNAL ;
    PORT
      LAYER M4 ;
        RECT  215.808 17.436 216 17.46 ;
    END
  END s0[8]
  PIN s0[9]
    DIRECTION INPUT ;
    USE SIGNAL ;
    PORT
      LAYER M4 ;
        RECT  215.808 19.212 216 19.236 ;
    END
  END s0[9]
  PIN s1[0]
    DIRECTION INPUT ;
    USE SIGNAL ;
    PORT
      LAYER M4 ;
        RECT  215.808 64.62 216 64.644 ;
    END
  END s1[0]
  PIN s1[10]
    DIRECTION INPUT ;
    USE SIGNAL ;
    PORT
      LAYER M4 ;
        RECT  215.808 82.764 216 82.788 ;
    END
  END s1[10]
  PIN s1[11]
    DIRECTION INPUT ;
    USE SIGNAL ;
    PORT
      LAYER M4 ;
        RECT  215.808 84.588 216 84.612 ;
    END
  END s1[11]
  PIN s1[12]
    DIRECTION INPUT ;
    USE SIGNAL ;
    PORT
      LAYER M4 ;
        RECT  215.808 86.412 216 86.436 ;
    END
  END s1[12]
  PIN s1[13]
    DIRECTION INPUT ;
    USE SIGNAL ;
    PORT
      LAYER M4 ;
        RECT  215.808 88.188 216 88.212 ;
    END
  END s1[13]
  PIN s1[14]
    DIRECTION INPUT ;
    USE SIGNAL ;
    PORT
      LAYER M4 ;
        RECT  215.808 90.012 216 90.036 ;
    END
  END s1[14]
  PIN s1[15]
    DIRECTION INPUT ;
    USE SIGNAL ;
    PORT
      LAYER M4 ;
        RECT  215.808 91.836 216 91.86 ;
    END
  END s1[15]
  PIN s1[16]
    DIRECTION INPUT ;
    USE SIGNAL ;
    PORT
      LAYER M4 ;
        RECT  215.808 93.66 216 93.684 ;
    END
  END s1[16]
  PIN s1[17]
    DIRECTION INPUT ;
    USE SIGNAL ;
    PORT
      LAYER M4 ;
        RECT  215.808 95.484 216 95.508 ;
    END
  END s1[17]
  PIN s1[18]
    DIRECTION INPUT ;
    USE SIGNAL ;
    PORT
      LAYER M4 ;
        RECT  215.808 97.26 216 97.284 ;
    END
  END s1[18]
  PIN s1[19]
    DIRECTION INPUT ;
    USE SIGNAL ;
    PORT
      LAYER M4 ;
        RECT  215.808 99.084 216 99.108 ;
    END
  END s1[19]
  PIN s1[1]
    DIRECTION INPUT ;
    USE SIGNAL ;
    PORT
      LAYER M4 ;
        RECT  215.808 66.444 216 66.468 ;
    END
  END s1[1]
  PIN s1[20]
    DIRECTION INPUT ;
    USE SIGNAL ;
    PORT
      LAYER M4 ;
        RECT  215.808 100.908 216 100.932 ;
    END
  END s1[20]
  PIN s1[21]
    DIRECTION INPUT ;
    USE SIGNAL ;
    PORT
      LAYER M4 ;
        RECT  215.808 102.732 216 102.756 ;
    END
  END s1[21]
  PIN s1[22]
    DIRECTION INPUT ;
    USE SIGNAL ;
    PORT
      LAYER M4 ;
        RECT  215.808 104.556 216 104.58 ;
    END
  END s1[22]
  PIN s1[23]
    DIRECTION INPUT ;
    USE SIGNAL ;
    PORT
      LAYER M4 ;
        RECT  215.808 106.332 216 106.356 ;
    END
  END s1[23]
  PIN s1[24]
    DIRECTION INPUT ;
    USE SIGNAL ;
    PORT
      LAYER M4 ;
        RECT  215.808 108.156 216 108.18 ;
    END
  END s1[24]
  PIN s1[25]
    DIRECTION INPUT ;
    USE SIGNAL ;
    PORT
      LAYER M4 ;
        RECT  215.808 109.98 216 110.004 ;
    END
  END s1[25]
  PIN s1[26]
    DIRECTION INPUT ;
    USE SIGNAL ;
    PORT
      LAYER M4 ;
        RECT  215.808 111.804 216 111.828 ;
    END
  END s1[26]
  PIN s1[27]
    DIRECTION INPUT ;
    USE SIGNAL ;
    PORT
      LAYER M4 ;
        RECT  215.808 113.628 216 113.652 ;
    END
  END s1[27]
  PIN s1[28]
    DIRECTION INPUT ;
    USE SIGNAL ;
    PORT
      LAYER M4 ;
        RECT  215.808 115.452 216 115.476 ;
    END
  END s1[28]
  PIN s1[29]
    DIRECTION INPUT ;
    USE SIGNAL ;
    PORT
      LAYER M4 ;
        RECT  215.808 117.228 216 117.252 ;
    END
  END s1[29]
  PIN s1[2]
    DIRECTION INPUT ;
    USE SIGNAL ;
    PORT
      LAYER M4 ;
        RECT  215.808 68.22 216 68.244 ;
    END
  END s1[2]
  PIN s1[30]
    DIRECTION INPUT ;
    USE SIGNAL ;
    PORT
      LAYER M4 ;
        RECT  215.808 119.052 216 119.076 ;
    END
  END s1[30]
  PIN s1[31]
    DIRECTION INPUT ;
    USE SIGNAL ;
    PORT
      LAYER M4 ;
        RECT  215.808 120.876 216 120.9 ;
    END
  END s1[31]
  PIN s1[32]
    DIRECTION INPUT ;
    USE SIGNAL ;
    PORT
      LAYER M4 ;
        RECT  215.808 122.7 216 122.724 ;
    END
  END s1[32]
  PIN s1[33]
    DIRECTION INPUT ;
    USE SIGNAL ;
    PORT
      LAYER M4 ;
        RECT  215.808 124.524 216 124.548 ;
    END
  END s1[33]
  PIN s1[3]
    DIRECTION INPUT ;
    USE SIGNAL ;
    PORT
      LAYER M4 ;
        RECT  215.808 70.044 216 70.068 ;
    END
  END s1[3]
  PIN s1[4]
    DIRECTION INPUT ;
    USE SIGNAL ;
    PORT
      LAYER M4 ;
        RECT  215.808 71.868 216 71.892 ;
    END
  END s1[4]
  PIN s1[5]
    DIRECTION INPUT ;
    USE SIGNAL ;
    PORT
      LAYER M4 ;
        RECT  215.808 73.692 216 73.716 ;
    END
  END s1[5]
  PIN s1[6]
    DIRECTION INPUT ;
    USE SIGNAL ;
    PORT
      LAYER M4 ;
        RECT  215.808 75.516 216 75.54 ;
    END
  END s1[6]
  PIN s1[7]
    DIRECTION INPUT ;
    USE SIGNAL ;
    PORT
      LAYER M4 ;
        RECT  215.808 77.292 216 77.316 ;
    END
  END s1[7]
  PIN s1[8]
    DIRECTION INPUT ;
    USE SIGNAL ;
    PORT
      LAYER M4 ;
        RECT  215.808 79.116 216 79.14 ;
    END
  END s1[8]
  PIN s1[9]
    DIRECTION INPUT ;
    USE SIGNAL ;
    PORT
      LAYER M4 ;
        RECT  215.808 80.94 216 80.964 ;
    END
  END s1[9]
  PIN s2[0]
    DIRECTION INPUT ;
    USE SIGNAL ;
    PORT
      LAYER M5 ;
        RECT  12.54 0 12.564 0.192 ;
    END
  END s2[0]
  PIN s2[10]
    DIRECTION INPUT ;
    USE SIGNAL ;
    PORT
      LAYER M5 ;
        RECT  15.324 0 15.348 0.192 ;
    END
  END s2[10]
  PIN s2[11]
    DIRECTION INPUT ;
    USE SIGNAL ;
    PORT
      LAYER M5 ;
        RECT  15.564 0 15.588 0.192 ;
    END
  END s2[11]
  PIN s2[12]
    DIRECTION INPUT ;
    USE SIGNAL ;
    PORT
      LAYER M5 ;
        RECT  15.852 0 15.876 0.192 ;
    END
  END s2[12]
  PIN s2[13]
    DIRECTION INPUT ;
    USE SIGNAL ;
    PORT
      LAYER M5 ;
        RECT  16.14 0 16.164 0.192 ;
    END
  END s2[13]
  PIN s2[14]
    DIRECTION INPUT ;
    USE SIGNAL ;
    PORT
      LAYER M5 ;
        RECT  16.428 0 16.452 0.192 ;
    END
  END s2[14]
  PIN s2[15]
    DIRECTION INPUT ;
    USE SIGNAL ;
    PORT
      LAYER M5 ;
        RECT  16.668 0 16.692 0.192 ;
    END
  END s2[15]
  PIN s2[16]
    DIRECTION INPUT ;
    USE SIGNAL ;
    PORT
      LAYER M5 ;
        RECT  16.956 0 16.98 0.192 ;
    END
  END s2[16]
  PIN s2[17]
    DIRECTION INPUT ;
    USE SIGNAL ;
    PORT
      LAYER M5 ;
        RECT  17.244 0 17.268 0.192 ;
    END
  END s2[17]
  PIN s2[18]
    DIRECTION INPUT ;
    USE SIGNAL ;
    PORT
      LAYER M5 ;
        RECT  17.484 0 17.508 0.192 ;
    END
  END s2[18]
  PIN s2[19]
    DIRECTION INPUT ;
    USE SIGNAL ;
    PORT
      LAYER M5 ;
        RECT  17.772 0 17.796 0.192 ;
    END
  END s2[19]
  PIN s2[1]
    DIRECTION INPUT ;
    USE SIGNAL ;
    PORT
      LAYER M5 ;
        RECT  12.828 0 12.852 0.192 ;
    END
  END s2[1]
  PIN s2[20]
    DIRECTION INPUT ;
    USE SIGNAL ;
    PORT
      LAYER M5 ;
        RECT  18.06 0 18.084 0.192 ;
    END
  END s2[20]
  PIN s2[21]
    DIRECTION INPUT ;
    USE SIGNAL ;
    PORT
      LAYER M5 ;
        RECT  18.348 0 18.372 0.192 ;
    END
  END s2[21]
  PIN s2[22]
    DIRECTION INPUT ;
    USE SIGNAL ;
    PORT
      LAYER M5 ;
        RECT  18.588 0 18.612 0.192 ;
    END
  END s2[22]
  PIN s2[23]
    DIRECTION INPUT ;
    USE SIGNAL ;
    PORT
      LAYER M5 ;
        RECT  18.876 0 18.9 0.192 ;
    END
  END s2[23]
  PIN s2[24]
    DIRECTION INPUT ;
    USE SIGNAL ;
    PORT
      LAYER M5 ;
        RECT  19.164 0 19.188 0.192 ;
    END
  END s2[24]
  PIN s2[25]
    DIRECTION INPUT ;
    USE SIGNAL ;
    PORT
      LAYER M5 ;
        RECT  19.404 0 19.428 0.192 ;
    END
  END s2[25]
  PIN s2[26]
    DIRECTION INPUT ;
    USE SIGNAL ;
    PORT
      LAYER M5 ;
        RECT  19.692 0 19.716 0.192 ;
    END
  END s2[26]
  PIN s2[27]
    DIRECTION INPUT ;
    USE SIGNAL ;
    PORT
      LAYER M5 ;
        RECT  19.98 0 20.004 0.192 ;
    END
  END s2[27]
  PIN s2[28]
    DIRECTION INPUT ;
    USE SIGNAL ;
    PORT
      LAYER M5 ;
        RECT  20.268 0 20.292 0.192 ;
    END
  END s2[28]
  PIN s2[29]
    DIRECTION INPUT ;
    USE SIGNAL ;
    PORT
      LAYER M5 ;
        RECT  20.508 0 20.532 0.192 ;
    END
  END s2[29]
  PIN s2[2]
    DIRECTION INPUT ;
    USE SIGNAL ;
    PORT
      LAYER M5 ;
        RECT  13.116 0 13.14 0.192 ;
    END
  END s2[2]
  PIN s2[30]
    DIRECTION INPUT ;
    USE SIGNAL ;
    PORT
      LAYER M5 ;
        RECT  20.796 0 20.82 0.192 ;
    END
  END s2[30]
  PIN s2[31]
    DIRECTION INPUT ;
    USE SIGNAL ;
    PORT
      LAYER M5 ;
        RECT  21.084 0 21.108 0.192 ;
    END
  END s2[31]
  PIN s2[32]
    DIRECTION INPUT ;
    USE SIGNAL ;
    PORT
      LAYER M5 ;
        RECT  21.372 0 21.396 0.192 ;
    END
  END s2[32]
  PIN s2[33]
    DIRECTION INPUT ;
    USE SIGNAL ;
    PORT
      LAYER M5 ;
        RECT  21.612 0 21.636 0.192 ;
    END
  END s2[33]
  PIN s2[3]
    DIRECTION INPUT ;
    USE SIGNAL ;
    PORT
      LAYER M5 ;
        RECT  13.404 0 13.428 0.192 ;
    END
  END s2[3]
  PIN s2[4]
    DIRECTION INPUT ;
    USE SIGNAL ;
    PORT
      LAYER M5 ;
        RECT  13.644 0 13.668 0.192 ;
    END
  END s2[4]
  PIN s2[5]
    DIRECTION INPUT ;
    USE SIGNAL ;
    PORT
      LAYER M5 ;
        RECT  13.932 0 13.956 0.192 ;
    END
  END s2[5]
  PIN s2[6]
    DIRECTION INPUT ;
    USE SIGNAL ;
    PORT
      LAYER M5 ;
        RECT  14.22 0 14.244 0.192 ;
    END
  END s2[6]
  PIN s2[7]
    DIRECTION INPUT ;
    USE SIGNAL ;
    PORT
      LAYER M5 ;
        RECT  14.46 0 14.484 0.192 ;
    END
  END s2[7]
  PIN s2[8]
    DIRECTION INPUT ;
    USE SIGNAL ;
    PORT
      LAYER M5 ;
        RECT  14.748 0 14.772 0.192 ;
    END
  END s2[8]
  PIN s2[9]
    DIRECTION INPUT ;
    USE SIGNAL ;
    PORT
      LAYER M5 ;
        RECT  15.036 0 15.06 0.192 ;
    END
  END s2[9]
  PIN s3[0]
    DIRECTION INPUT ;
    USE SIGNAL ;
    PORT
      LAYER M5 ;
        RECT  21.9 0 21.924 0.192 ;
    END
  END s3[0]
  PIN s3[10]
    DIRECTION INPUT ;
    USE SIGNAL ;
    PORT
      LAYER M5 ;
        RECT  24.636 0 24.66 0.192 ;
    END
  END s3[10]
  PIN s3[11]
    DIRECTION INPUT ;
    USE SIGNAL ;
    PORT
      LAYER M5 ;
        RECT  24.924 0 24.948 0.192 ;
    END
  END s3[11]
  PIN s3[12]
    DIRECTION INPUT ;
    USE SIGNAL ;
    PORT
      LAYER M5 ;
        RECT  25.212 0 25.236 0.192 ;
    END
  END s3[12]
  PIN s3[13]
    DIRECTION INPUT ;
    USE SIGNAL ;
    PORT
      LAYER M5 ;
        RECT  25.452 0 25.476 0.192 ;
    END
  END s3[13]
  PIN s3[14]
    DIRECTION INPUT ;
    USE SIGNAL ;
    PORT
      LAYER M5 ;
        RECT  25.74 0 25.764 0.192 ;
    END
  END s3[14]
  PIN s3[15]
    DIRECTION INPUT ;
    USE SIGNAL ;
    PORT
      LAYER M5 ;
        RECT  26.028 0 26.052 0.192 ;
    END
  END s3[15]
  PIN s3[16]
    DIRECTION INPUT ;
    USE SIGNAL ;
    PORT
      LAYER M5 ;
        RECT  26.268 0 26.292 0.192 ;
    END
  END s3[16]
  PIN s3[17]
    DIRECTION INPUT ;
    USE SIGNAL ;
    PORT
      LAYER M5 ;
        RECT  26.556 0 26.58 0.192 ;
    END
  END s3[17]
  PIN s3[18]
    DIRECTION INPUT ;
    USE SIGNAL ;
    PORT
      LAYER M5 ;
        RECT  26.844 0 26.868 0.192 ;
    END
  END s3[18]
  PIN s3[19]
    DIRECTION INPUT ;
    USE SIGNAL ;
    PORT
      LAYER M5 ;
        RECT  27.132 0 27.156 0.192 ;
    END
  END s3[19]
  PIN s3[1]
    DIRECTION INPUT ;
    USE SIGNAL ;
    PORT
      LAYER M5 ;
        RECT  22.188 0 22.212 0.192 ;
    END
  END s3[1]
  PIN s3[20]
    DIRECTION INPUT ;
    USE SIGNAL ;
    PORT
      LAYER M5 ;
        RECT  27.372 0 27.396 0.192 ;
    END
  END s3[20]
  PIN s3[21]
    DIRECTION INPUT ;
    USE SIGNAL ;
    PORT
      LAYER M5 ;
        RECT  27.66 0 27.684 0.192 ;
    END
  END s3[21]
  PIN s3[22]
    DIRECTION INPUT ;
    USE SIGNAL ;
    PORT
      LAYER M5 ;
        RECT  27.948 0 27.972 0.192 ;
    END
  END s3[22]
  PIN s3[23]
    DIRECTION INPUT ;
    USE SIGNAL ;
    PORT
      LAYER M5 ;
        RECT  28.236 0 28.26 0.192 ;
    END
  END s3[23]
  PIN s3[24]
    DIRECTION INPUT ;
    USE SIGNAL ;
    PORT
      LAYER M5 ;
        RECT  28.476 0 28.5 0.192 ;
    END
  END s3[24]
  PIN s3[25]
    DIRECTION INPUT ;
    USE SIGNAL ;
    PORT
      LAYER M5 ;
        RECT  28.764 0 28.788 0.192 ;
    END
  END s3[25]
  PIN s3[26]
    DIRECTION INPUT ;
    USE SIGNAL ;
    PORT
      LAYER M5 ;
        RECT  29.052 0 29.076 0.192 ;
    END
  END s3[26]
  PIN s3[27]
    DIRECTION INPUT ;
    USE SIGNAL ;
    PORT
      LAYER M5 ;
        RECT  29.292 0 29.316 0.192 ;
    END
  END s3[27]
  PIN s3[28]
    DIRECTION INPUT ;
    USE SIGNAL ;
    PORT
      LAYER M5 ;
        RECT  29.58 0 29.604 0.192 ;
    END
  END s3[28]
  PIN s3[29]
    DIRECTION INPUT ;
    USE SIGNAL ;
    PORT
      LAYER M5 ;
        RECT  29.868 0 29.892 0.192 ;
    END
  END s3[29]
  PIN s3[2]
    DIRECTION INPUT ;
    USE SIGNAL ;
    PORT
      LAYER M5 ;
        RECT  22.428 0 22.452 0.192 ;
    END
  END s3[2]
  PIN s3[30]
    DIRECTION INPUT ;
    USE SIGNAL ;
    PORT
      LAYER M5 ;
        RECT  30.156 0 30.18 0.192 ;
    END
  END s3[30]
  PIN s3[31]
    DIRECTION INPUT ;
    USE SIGNAL ;
    PORT
      LAYER M5 ;
        RECT  30.396 0 30.42 0.192 ;
    END
  END s3[31]
  PIN s3[32]
    DIRECTION INPUT ;
    USE SIGNAL ;
    PORT
      LAYER M5 ;
        RECT  30.684 0 30.708 0.192 ;
    END
  END s3[32]
  PIN s3[33]
    DIRECTION INPUT ;
    USE SIGNAL ;
    PORT
      LAYER M5 ;
        RECT  30.972 0 30.996 0.192 ;
    END
  END s3[33]
  PIN s3[3]
    DIRECTION INPUT ;
    USE SIGNAL ;
    PORT
      LAYER M5 ;
        RECT  22.716 0 22.74 0.192 ;
    END
  END s3[3]
  PIN s3[4]
    DIRECTION INPUT ;
    USE SIGNAL ;
    PORT
      LAYER M5 ;
        RECT  23.004 0 23.028 0.192 ;
    END
  END s3[4]
  PIN s3[5]
    DIRECTION INPUT ;
    USE SIGNAL ;
    PORT
      LAYER M5 ;
        RECT  23.292 0 23.316 0.192 ;
    END
  END s3[5]
  PIN s3[6]
    DIRECTION INPUT ;
    USE SIGNAL ;
    PORT
      LAYER M5 ;
        RECT  23.532 0 23.556 0.192 ;
    END
  END s3[6]
  PIN s3[7]
    DIRECTION INPUT ;
    USE SIGNAL ;
    PORT
      LAYER M5 ;
        RECT  23.82 0 23.844 0.192 ;
    END
  END s3[7]
  PIN s3[8]
    DIRECTION INPUT ;
    USE SIGNAL ;
    PORT
      LAYER M5 ;
        RECT  24.108 0 24.132 0.192 ;
    END
  END s3[8]
  PIN s3[9]
    DIRECTION INPUT ;
    USE SIGNAL ;
    PORT
      LAYER M5 ;
        RECT  24.348 0 24.372 0.192 ;
    END
  END s3[9]
  PIN si[0]
    DIRECTION INPUT ;
    USE SIGNAL ;
    PORT
      LAYER M4 ;
        RECT  215.808 126.3 216 126.324 ;
    END
  END si[0]
  PIN si[10]
    DIRECTION INPUT ;
    USE SIGNAL ;
    PORT
      LAYER M4 ;
        RECT  215.808 144.492 216 144.516 ;
    END
  END si[10]
  PIN si[11]
    DIRECTION INPUT ;
    USE SIGNAL ;
    PORT
      LAYER M4 ;
        RECT  215.808 146.268 216 146.292 ;
    END
  END si[11]
  PIN si[12]
    DIRECTION INPUT ;
    USE SIGNAL ;
    PORT
      LAYER M4 ;
        RECT  215.808 148.092 216 148.116 ;
    END
  END si[12]
  PIN si[13]
    DIRECTION INPUT ;
    USE SIGNAL ;
    PORT
      LAYER M4 ;
        RECT  215.808 149.916 216 149.94 ;
    END
  END si[13]
  PIN si[14]
    DIRECTION INPUT ;
    USE SIGNAL ;
    PORT
      LAYER M4 ;
        RECT  215.808 151.74 216 151.764 ;
    END
  END si[14]
  PIN si[15]
    DIRECTION INPUT ;
    USE SIGNAL ;
    PORT
      LAYER M4 ;
        RECT  215.808 153.564 216 153.588 ;
    END
  END si[15]
  PIN si[16]
    DIRECTION INPUT ;
    USE SIGNAL ;
    PORT
      LAYER M4 ;
        RECT  215.808 155.34 216 155.364 ;
    END
  END si[16]
  PIN si[17]
    DIRECTION INPUT ;
    USE SIGNAL ;
    PORT
      LAYER M4 ;
        RECT  215.808 157.164 216 157.188 ;
    END
  END si[17]
  PIN si[18]
    DIRECTION INPUT ;
    USE SIGNAL ;
    PORT
      LAYER M4 ;
        RECT  215.808 158.988 216 159.012 ;
    END
  END si[18]
  PIN si[19]
    DIRECTION INPUT ;
    USE SIGNAL ;
    PORT
      LAYER M4 ;
        RECT  215.808 160.812 216 160.836 ;
    END
  END si[19]
  PIN si[1]
    DIRECTION INPUT ;
    USE SIGNAL ;
    PORT
      LAYER M4 ;
        RECT  215.808 128.124 216 128.148 ;
    END
  END si[1]
  PIN si[20]
    DIRECTION INPUT ;
    USE SIGNAL ;
    PORT
      LAYER M4 ;
        RECT  215.808 162.636 216 162.66 ;
    END
  END si[20]
  PIN si[21]
    DIRECTION INPUT ;
    USE SIGNAL ;
    PORT
      LAYER M4 ;
        RECT  215.808 164.412 216 164.436 ;
    END
  END si[21]
  PIN si[22]
    DIRECTION INPUT ;
    USE SIGNAL ;
    PORT
      LAYER M4 ;
        RECT  215.808 166.236 216 166.26 ;
    END
  END si[22]
  PIN si[23]
    DIRECTION INPUT ;
    USE SIGNAL ;
    PORT
      LAYER M4 ;
        RECT  215.808 168.06 216 168.084 ;
    END
  END si[23]
  PIN si[24]
    DIRECTION INPUT ;
    USE SIGNAL ;
    PORT
      LAYER M4 ;
        RECT  215.808 169.884 216 169.908 ;
    END
  END si[24]
  PIN si[2]
    DIRECTION INPUT ;
    USE SIGNAL ;
    PORT
      LAYER M4 ;
        RECT  215.808 129.948 216 129.972 ;
    END
  END si[2]
  PIN si[3]
    DIRECTION INPUT ;
    USE SIGNAL ;
    PORT
      LAYER M4 ;
        RECT  215.808 131.772 216 131.796 ;
    END
  END si[3]
  PIN si[4]
    DIRECTION INPUT ;
    USE SIGNAL ;
    PORT
      LAYER M4 ;
        RECT  215.808 133.596 216 133.62 ;
    END
  END si[4]
  PIN si[5]
    DIRECTION INPUT ;
    USE SIGNAL ;
    PORT
      LAYER M4 ;
        RECT  215.808 135.372 216 135.396 ;
    END
  END si[5]
  PIN si[6]
    DIRECTION INPUT ;
    USE SIGNAL ;
    PORT
      LAYER M4 ;
        RECT  215.808 137.196 216 137.22 ;
    END
  END si[6]
  PIN si[7]
    DIRECTION INPUT ;
    USE SIGNAL ;
    PORT
      LAYER M4 ;
        RECT  215.808 139.02 216 139.044 ;
    END
  END si[7]
  PIN si[8]
    DIRECTION INPUT ;
    USE SIGNAL ;
    PORT
      LAYER M4 ;
        RECT  215.808 140.844 216 140.868 ;
    END
  END si[8]
  PIN si[9]
    DIRECTION INPUT ;
    USE SIGNAL ;
    PORT
      LAYER M4 ;
        RECT  215.808 142.668 216 142.692 ;
    END
  END si[9]
  PIN so[0]
    DIRECTION OUTPUT ;
    USE SIGNAL ;
    PORT
      LAYER M5 ;
        RECT  31.212 0 31.236 0.192 ;
    END
  END so[0]
  PIN so[100]
    DIRECTION OUTPUT ;
    USE SIGNAL ;
    PORT
      LAYER M5 ;
        RECT  58.716 0 58.74 0.192 ;
    END
  END so[100]
  PIN so[101]
    DIRECTION OUTPUT ;
    USE SIGNAL ;
    PORT
      LAYER M5 ;
        RECT  58.956 0 58.98 0.192 ;
    END
  END so[101]
  PIN so[102]
    DIRECTION OUTPUT ;
    USE SIGNAL ;
    PORT
      LAYER M5 ;
        RECT  59.244 0 59.268 0.192 ;
    END
  END so[102]
  PIN so[103]
    DIRECTION OUTPUT ;
    USE SIGNAL ;
    PORT
      LAYER M5 ;
        RECT  59.532 0 59.556 0.192 ;
    END
  END so[103]
  PIN so[104]
    DIRECTION OUTPUT ;
    USE SIGNAL ;
    PORT
      LAYER M5 ;
        RECT  59.772 0 59.796 0.192 ;
    END
  END so[104]
  PIN so[105]
    DIRECTION OUTPUT ;
    USE SIGNAL ;
    PORT
      LAYER M5 ;
        RECT  60.06 0 60.084 0.192 ;
    END
  END so[105]
  PIN so[106]
    DIRECTION OUTPUT ;
    USE SIGNAL ;
    PORT
      LAYER M5 ;
        RECT  60.348 0 60.372 0.192 ;
    END
  END so[106]
  PIN so[107]
    DIRECTION OUTPUT ;
    USE SIGNAL ;
    PORT
      LAYER M5 ;
        RECT  60.636 0 60.66 0.192 ;
    END
  END so[107]
  PIN so[108]
    DIRECTION OUTPUT ;
    USE SIGNAL ;
    PORT
      LAYER M5 ;
        RECT  60.876 0 60.9 0.192 ;
    END
  END so[108]
  PIN so[109]
    DIRECTION OUTPUT ;
    USE SIGNAL ;
    PORT
      LAYER M5 ;
        RECT  61.164 0 61.188 0.192 ;
    END
  END so[109]
  PIN so[10]
    DIRECTION OUTPUT ;
    USE SIGNAL ;
    PORT
      LAYER M5 ;
        RECT  33.996 0 34.02 0.192 ;
    END
  END so[10]
  PIN so[110]
    DIRECTION OUTPUT ;
    USE SIGNAL ;
    PORT
      LAYER M5 ;
        RECT  61.452 0 61.476 0.192 ;
    END
  END so[110]
  PIN so[111]
    DIRECTION OUTPUT ;
    USE SIGNAL ;
    PORT
      LAYER M5 ;
        RECT  61.692 0 61.716 0.192 ;
    END
  END so[111]
  PIN so[112]
    DIRECTION OUTPUT ;
    USE SIGNAL ;
    PORT
      LAYER M5 ;
        RECT  61.98 0 62.004 0.192 ;
    END
  END so[112]
  PIN so[113]
    DIRECTION OUTPUT ;
    USE SIGNAL ;
    PORT
      LAYER M5 ;
        RECT  62.268 0 62.292 0.192 ;
    END
  END so[113]
  PIN so[114]
    DIRECTION OUTPUT ;
    USE SIGNAL ;
    PORT
      LAYER M5 ;
        RECT  62.556 0 62.58 0.192 ;
    END
  END so[114]
  PIN so[115]
    DIRECTION OUTPUT ;
    USE SIGNAL ;
    PORT
      LAYER M5 ;
        RECT  62.796 0 62.82 0.192 ;
    END
  END so[115]
  PIN so[116]
    DIRECTION OUTPUT ;
    USE SIGNAL ;
    PORT
      LAYER M5 ;
        RECT  63.084 0 63.108 0.192 ;
    END
  END so[116]
  PIN so[117]
    DIRECTION OUTPUT ;
    USE SIGNAL ;
    PORT
      LAYER M5 ;
        RECT  63.372 0 63.396 0.192 ;
    END
  END so[117]
  PIN so[118]
    DIRECTION OUTPUT ;
    USE SIGNAL ;
    PORT
      LAYER M5 ;
        RECT  63.66 0 63.684 0.192 ;
    END
  END so[118]
  PIN so[119]
    DIRECTION OUTPUT ;
    USE SIGNAL ;
    PORT
      LAYER M5 ;
        RECT  63.9 0 63.924 0.192 ;
    END
  END so[119]
  PIN so[11]
    DIRECTION OUTPUT ;
    USE SIGNAL ;
    PORT
      LAYER M5 ;
        RECT  34.236 0 34.26 0.192 ;
    END
  END so[11]
  PIN so[120]
    DIRECTION OUTPUT ;
    USE SIGNAL ;
    PORT
      LAYER M5 ;
        RECT  64.188 0 64.212 0.192 ;
    END
  END so[120]
  PIN so[121]
    DIRECTION OUTPUT ;
    USE SIGNAL ;
    PORT
      LAYER M5 ;
        RECT  64.476 0 64.5 0.192 ;
    END
  END so[121]
  PIN so[122]
    DIRECTION OUTPUT ;
    USE SIGNAL ;
    PORT
      LAYER M5 ;
        RECT  64.716 0 64.74 0.192 ;
    END
  END so[122]
  PIN so[123]
    DIRECTION OUTPUT ;
    USE SIGNAL ;
    PORT
      LAYER M5 ;
        RECT  65.004 0 65.028 0.192 ;
    END
  END so[123]
  PIN so[124]
    DIRECTION OUTPUT ;
    USE SIGNAL ;
    PORT
      LAYER M5 ;
        RECT  65.292 0 65.316 0.192 ;
    END
  END so[124]
  PIN so[125]
    DIRECTION OUTPUT ;
    USE SIGNAL ;
    PORT
      LAYER M5 ;
        RECT  65.58 0 65.604 0.192 ;
    END
  END so[125]
  PIN so[126]
    DIRECTION OUTPUT ;
    USE SIGNAL ;
    PORT
      LAYER M5 ;
        RECT  65.82 0 65.844 0.192 ;
    END
  END so[126]
  PIN so[127]
    DIRECTION OUTPUT ;
    USE SIGNAL ;
    PORT
      LAYER M5 ;
        RECT  66.108 0 66.132 0.192 ;
    END
  END so[127]
  PIN so[128]
    DIRECTION OUTPUT ;
    USE SIGNAL ;
    PORT
      LAYER M5 ;
        RECT  66.396 0 66.42 0.192 ;
    END
  END so[128]
  PIN so[129]
    DIRECTION OUTPUT ;
    USE SIGNAL ;
    PORT
      LAYER M5 ;
        RECT  66.636 0 66.66 0.192 ;
    END
  END so[129]
  PIN so[12]
    DIRECTION OUTPUT ;
    USE SIGNAL ;
    PORT
      LAYER M5 ;
        RECT  34.524 0 34.548 0.192 ;
    END
  END so[12]
  PIN so[130]
    DIRECTION OUTPUT ;
    USE SIGNAL ;
    PORT
      LAYER M5 ;
        RECT  66.924 0 66.948 0.192 ;
    END
  END so[130]
  PIN so[131]
    DIRECTION OUTPUT ;
    USE SIGNAL ;
    PORT
      LAYER M5 ;
        RECT  67.212 0 67.236 0.192 ;
    END
  END so[131]
  PIN so[132]
    DIRECTION OUTPUT ;
    USE SIGNAL ;
    PORT
      LAYER M5 ;
        RECT  67.5 0 67.524 0.192 ;
    END
  END so[132]
  PIN so[133]
    DIRECTION OUTPUT ;
    USE SIGNAL ;
    PORT
      LAYER M5 ;
        RECT  67.74 0 67.764 0.192 ;
    END
  END so[133]
  PIN so[134]
    DIRECTION OUTPUT ;
    USE SIGNAL ;
    PORT
      LAYER M5 ;
        RECT  68.028 0 68.052 0.192 ;
    END
  END so[134]
  PIN so[135]
    DIRECTION OUTPUT ;
    USE SIGNAL ;
    PORT
      LAYER M5 ;
        RECT  68.316 0 68.34 0.192 ;
    END
  END so[135]
  PIN so[136]
    DIRECTION OUTPUT ;
    USE SIGNAL ;
    PORT
      LAYER M5 ;
        RECT  68.604 0 68.628 0.192 ;
    END
  END so[136]
  PIN so[137]
    DIRECTION OUTPUT ;
    USE SIGNAL ;
    PORT
      LAYER M5 ;
        RECT  68.844 0 68.868 0.192 ;
    END
  END so[137]
  PIN so[138]
    DIRECTION OUTPUT ;
    USE SIGNAL ;
    PORT
      LAYER M5 ;
        RECT  69.132 0 69.156 0.192 ;
    END
  END so[138]
  PIN so[139]
    DIRECTION OUTPUT ;
    USE SIGNAL ;
    PORT
      LAYER M5 ;
        RECT  69.42 0 69.444 0.192 ;
    END
  END so[139]
  PIN so[13]
    DIRECTION OUTPUT ;
    USE SIGNAL ;
    PORT
      LAYER M5 ;
        RECT  34.812 0 34.836 0.192 ;
    END
  END so[13]
  PIN so[140]
    DIRECTION OUTPUT ;
    USE SIGNAL ;
    PORT
      LAYER M5 ;
        RECT  69.66 0 69.684 0.192 ;
    END
  END so[140]
  PIN so[141]
    DIRECTION OUTPUT ;
    USE SIGNAL ;
    PORT
      LAYER M5 ;
        RECT  69.948 0 69.972 0.192 ;
    END
  END so[141]
  PIN so[142]
    DIRECTION OUTPUT ;
    USE SIGNAL ;
    PORT
      LAYER M5 ;
        RECT  70.236 0 70.26 0.192 ;
    END
  END so[142]
  PIN so[143]
    DIRECTION OUTPUT ;
    USE SIGNAL ;
    PORT
      LAYER M5 ;
        RECT  70.524 0 70.548 0.192 ;
    END
  END so[143]
  PIN so[144]
    DIRECTION OUTPUT ;
    USE SIGNAL ;
    PORT
      LAYER M5 ;
        RECT  70.764 0 70.788 0.192 ;
    END
  END so[144]
  PIN so[145]
    DIRECTION OUTPUT ;
    USE SIGNAL ;
    PORT
      LAYER M5 ;
        RECT  71.052 0 71.076 0.192 ;
    END
  END so[145]
  PIN so[146]
    DIRECTION OUTPUT ;
    USE SIGNAL ;
    PORT
      LAYER M5 ;
        RECT  71.34 0 71.364 0.192 ;
    END
  END so[146]
  PIN so[147]
    DIRECTION OUTPUT ;
    USE SIGNAL ;
    PORT
      LAYER M5 ;
        RECT  71.58 0 71.604 0.192 ;
    END
  END so[147]
  PIN so[148]
    DIRECTION OUTPUT ;
    USE SIGNAL ;
    PORT
      LAYER M5 ;
        RECT  71.868 0 71.892 0.192 ;
    END
  END so[148]
  PIN so[149]
    DIRECTION OUTPUT ;
    USE SIGNAL ;
    PORT
      LAYER M5 ;
        RECT  72.156 0 72.18 0.192 ;
    END
  END so[149]
  PIN so[14]
    DIRECTION OUTPUT ;
    USE SIGNAL ;
    PORT
      LAYER M5 ;
        RECT  35.1 0 35.124 0.192 ;
    END
  END so[14]
  PIN so[150]
    DIRECTION OUTPUT ;
    USE SIGNAL ;
    PORT
      LAYER M5 ;
        RECT  72.444 0 72.468 0.192 ;
    END
  END so[150]
  PIN so[151]
    DIRECTION OUTPUT ;
    USE SIGNAL ;
    PORT
      LAYER M5 ;
        RECT  72.684 0 72.708 0.192 ;
    END
  END so[151]
  PIN so[152]
    DIRECTION OUTPUT ;
    USE SIGNAL ;
    PORT
      LAYER M5 ;
        RECT  72.972 0 72.996 0.192 ;
    END
  END so[152]
  PIN so[153]
    DIRECTION OUTPUT ;
    USE SIGNAL ;
    PORT
      LAYER M5 ;
        RECT  73.26 0 73.284 0.192 ;
    END
  END so[153]
  PIN so[154]
    DIRECTION OUTPUT ;
    USE SIGNAL ;
    PORT
      LAYER M5 ;
        RECT  73.548 0 73.572 0.192 ;
    END
  END so[154]
  PIN so[155]
    DIRECTION OUTPUT ;
    USE SIGNAL ;
    PORT
      LAYER M5 ;
        RECT  73.788 0 73.812 0.192 ;
    END
  END so[155]
  PIN so[156]
    DIRECTION OUTPUT ;
    USE SIGNAL ;
    PORT
      LAYER M5 ;
        RECT  74.076 0 74.1 0.192 ;
    END
  END so[156]
  PIN so[157]
    DIRECTION OUTPUT ;
    USE SIGNAL ;
    PORT
      LAYER M5 ;
        RECT  74.364 0 74.388 0.192 ;
    END
  END so[157]
  PIN so[158]
    DIRECTION OUTPUT ;
    USE SIGNAL ;
    PORT
      LAYER M5 ;
        RECT  74.604 0 74.628 0.192 ;
    END
  END so[158]
  PIN so[159]
    DIRECTION OUTPUT ;
    USE SIGNAL ;
    PORT
      LAYER M5 ;
        RECT  74.892 0 74.916 0.192 ;
    END
  END so[159]
  PIN so[15]
    DIRECTION OUTPUT ;
    USE SIGNAL ;
    PORT
      LAYER M5 ;
        RECT  35.34 0 35.364 0.192 ;
    END
  END so[15]
  PIN so[160]
    DIRECTION OUTPUT ;
    USE SIGNAL ;
    PORT
      LAYER M5 ;
        RECT  75.18 0 75.204 0.192 ;
    END
  END so[160]
  PIN so[161]
    DIRECTION OUTPUT ;
    USE SIGNAL ;
    PORT
      LAYER M5 ;
        RECT  75.468 0 75.492 0.192 ;
    END
  END so[161]
  PIN so[162]
    DIRECTION OUTPUT ;
    USE SIGNAL ;
    PORT
      LAYER M5 ;
        RECT  75.708 0 75.732 0.192 ;
    END
  END so[162]
  PIN so[163]
    DIRECTION OUTPUT ;
    USE SIGNAL ;
    PORT
      LAYER M5 ;
        RECT  75.996 0 76.02 0.192 ;
    END
  END so[163]
  PIN so[164]
    DIRECTION OUTPUT ;
    USE SIGNAL ;
    PORT
      LAYER M5 ;
        RECT  76.284 0 76.308 0.192 ;
    END
  END so[164]
  PIN so[165]
    DIRECTION OUTPUT ;
    USE SIGNAL ;
    PORT
      LAYER M5 ;
        RECT  76.524 0 76.548 0.192 ;
    END
  END so[165]
  PIN so[166]
    DIRECTION OUTPUT ;
    USE SIGNAL ;
    PORT
      LAYER M5 ;
        RECT  76.812 0 76.836 0.192 ;
    END
  END so[166]
  PIN so[167]
    DIRECTION OUTPUT ;
    USE SIGNAL ;
    PORT
      LAYER M5 ;
        RECT  77.1 0 77.124 0.192 ;
    END
  END so[167]
  PIN so[168]
    DIRECTION OUTPUT ;
    USE SIGNAL ;
    PORT
      LAYER M5 ;
        RECT  77.388 0 77.412 0.192 ;
    END
  END so[168]
  PIN so[169]
    DIRECTION OUTPUT ;
    USE SIGNAL ;
    PORT
      LAYER M5 ;
        RECT  77.628 0 77.652 0.192 ;
    END
  END so[169]
  PIN so[16]
    DIRECTION OUTPUT ;
    USE SIGNAL ;
    PORT
      LAYER M5 ;
        RECT  35.628 0 35.652 0.192 ;
    END
  END so[16]
  PIN so[170]
    DIRECTION OUTPUT ;
    USE SIGNAL ;
    PORT
      LAYER M5 ;
        RECT  77.916 0 77.94 0.192 ;
    END
  END so[170]
  PIN so[171]
    DIRECTION OUTPUT ;
    USE SIGNAL ;
    PORT
      LAYER M5 ;
        RECT  78.204 0 78.228 0.192 ;
    END
  END so[171]
  PIN so[172]
    DIRECTION OUTPUT ;
    USE SIGNAL ;
    PORT
      LAYER M5 ;
        RECT  78.444 0 78.468 0.192 ;
    END
  END so[172]
  PIN so[173]
    DIRECTION OUTPUT ;
    USE SIGNAL ;
    PORT
      LAYER M5 ;
        RECT  78.732 0 78.756 0.192 ;
    END
  END so[173]
  PIN so[174]
    DIRECTION OUTPUT ;
    USE SIGNAL ;
    PORT
      LAYER M5 ;
        RECT  79.02 0 79.044 0.192 ;
    END
  END so[174]
  PIN so[175]
    DIRECTION OUTPUT ;
    USE SIGNAL ;
    PORT
      LAYER M5 ;
        RECT  79.308 0 79.332 0.192 ;
    END
  END so[175]
  PIN so[176]
    DIRECTION OUTPUT ;
    USE SIGNAL ;
    PORT
      LAYER M5 ;
        RECT  79.548 0 79.572 0.192 ;
    END
  END so[176]
  PIN so[177]
    DIRECTION OUTPUT ;
    USE SIGNAL ;
    PORT
      LAYER M5 ;
        RECT  79.836 0 79.86 0.192 ;
    END
  END so[177]
  PIN so[178]
    DIRECTION OUTPUT ;
    USE SIGNAL ;
    PORT
      LAYER M5 ;
        RECT  80.124 0 80.148 0.192 ;
    END
  END so[178]
  PIN so[179]
    DIRECTION OUTPUT ;
    USE SIGNAL ;
    PORT
      LAYER M5 ;
        RECT  80.412 0 80.436 0.192 ;
    END
  END so[179]
  PIN so[17]
    DIRECTION OUTPUT ;
    USE SIGNAL ;
    PORT
      LAYER M5 ;
        RECT  35.916 0 35.94 0.192 ;
    END
  END so[17]
  PIN so[180]
    DIRECTION OUTPUT ;
    USE SIGNAL ;
    PORT
      LAYER M5 ;
        RECT  80.652 0 80.676 0.192 ;
    END
  END so[180]
  PIN so[181]
    DIRECTION OUTPUT ;
    USE SIGNAL ;
    PORT
      LAYER M5 ;
        RECT  80.94 0 80.964 0.192 ;
    END
  END so[181]
  PIN so[182]
    DIRECTION OUTPUT ;
    USE SIGNAL ;
    PORT
      LAYER M5 ;
        RECT  81.228 0 81.252 0.192 ;
    END
  END so[182]
  PIN so[183]
    DIRECTION OUTPUT ;
    USE SIGNAL ;
    PORT
      LAYER M5 ;
        RECT  81.468 0 81.492 0.192 ;
    END
  END so[183]
  PIN so[184]
    DIRECTION OUTPUT ;
    USE SIGNAL ;
    PORT
      LAYER M5 ;
        RECT  81.756 0 81.78 0.192 ;
    END
  END so[184]
  PIN so[185]
    DIRECTION OUTPUT ;
    USE SIGNAL ;
    PORT
      LAYER M5 ;
        RECT  82.044 0 82.068 0.192 ;
    END
  END so[185]
  PIN so[186]
    DIRECTION OUTPUT ;
    USE SIGNAL ;
    PORT
      LAYER M5 ;
        RECT  82.332 0 82.356 0.192 ;
    END
  END so[186]
  PIN so[187]
    DIRECTION OUTPUT ;
    USE SIGNAL ;
    PORT
      LAYER M5 ;
        RECT  82.572 0 82.596 0.192 ;
    END
  END so[187]
  PIN so[188]
    DIRECTION OUTPUT ;
    USE SIGNAL ;
    PORT
      LAYER M5 ;
        RECT  82.86 0 82.884 0.192 ;
    END
  END so[188]
  PIN so[189]
    DIRECTION OUTPUT ;
    USE SIGNAL ;
    PORT
      LAYER M5 ;
        RECT  83.148 0 83.172 0.192 ;
    END
  END so[189]
  PIN so[18]
    DIRECTION OUTPUT ;
    USE SIGNAL ;
    PORT
      LAYER M5 ;
        RECT  36.156 0 36.18 0.192 ;
    END
  END so[18]
  PIN so[190]
    DIRECTION OUTPUT ;
    USE SIGNAL ;
    PORT
      LAYER M5 ;
        RECT  83.388 0 83.412 0.192 ;
    END
  END so[190]
  PIN so[191]
    DIRECTION OUTPUT ;
    USE SIGNAL ;
    PORT
      LAYER M5 ;
        RECT  83.676 0 83.7 0.192 ;
    END
  END so[191]
  PIN so[192]
    DIRECTION OUTPUT ;
    USE SIGNAL ;
    PORT
      LAYER M5 ;
        RECT  83.964 0 83.988 0.192 ;
    END
  END so[192]
  PIN so[193]
    DIRECTION OUTPUT ;
    USE SIGNAL ;
    PORT
      LAYER M5 ;
        RECT  84.252 0 84.276 0.192 ;
    END
  END so[193]
  PIN so[194]
    DIRECTION OUTPUT ;
    USE SIGNAL ;
    PORT
      LAYER M5 ;
        RECT  84.492 0 84.516 0.192 ;
    END
  END so[194]
  PIN so[195]
    DIRECTION OUTPUT ;
    USE SIGNAL ;
    PORT
      LAYER M5 ;
        RECT  84.78 0 84.804 0.192 ;
    END
  END so[195]
  PIN so[196]
    DIRECTION OUTPUT ;
    USE SIGNAL ;
    PORT
      LAYER M5 ;
        RECT  85.068 0 85.092 0.192 ;
    END
  END so[196]
  PIN so[197]
    DIRECTION OUTPUT ;
    USE SIGNAL ;
    PORT
      LAYER M5 ;
        RECT  85.356 0 85.38 0.192 ;
    END
  END so[197]
  PIN so[198]
    DIRECTION OUTPUT ;
    USE SIGNAL ;
    PORT
      LAYER M5 ;
        RECT  85.596 0 85.62 0.192 ;
    END
  END so[198]
  PIN so[199]
    DIRECTION OUTPUT ;
    USE SIGNAL ;
    PORT
      LAYER M5 ;
        RECT  85.884 0 85.908 0.192 ;
    END
  END so[199]
  PIN so[19]
    DIRECTION OUTPUT ;
    USE SIGNAL ;
    PORT
      LAYER M5 ;
        RECT  36.444 0 36.468 0.192 ;
    END
  END so[19]
  PIN so[1]
    DIRECTION OUTPUT ;
    USE SIGNAL ;
    PORT
      LAYER M5 ;
        RECT  31.5 0 31.524 0.192 ;
    END
  END so[1]
  PIN so[200]
    DIRECTION OUTPUT ;
    USE SIGNAL ;
    PORT
      LAYER M5 ;
        RECT  86.172 0 86.196 0.192 ;
    END
  END so[200]
  PIN so[201]
    DIRECTION OUTPUT ;
    USE SIGNAL ;
    PORT
      LAYER M5 ;
        RECT  86.412 0 86.436 0.192 ;
    END
  END so[201]
  PIN so[202]
    DIRECTION OUTPUT ;
    USE SIGNAL ;
    PORT
      LAYER M5 ;
        RECT  86.7 0 86.724 0.192 ;
    END
  END so[202]
  PIN so[203]
    DIRECTION OUTPUT ;
    USE SIGNAL ;
    PORT
      LAYER M5 ;
        RECT  86.988 0 87.012 0.192 ;
    END
  END so[203]
  PIN so[204]
    DIRECTION OUTPUT ;
    USE SIGNAL ;
    PORT
      LAYER M5 ;
        RECT  87.276 0 87.3 0.192 ;
    END
  END so[204]
  PIN so[205]
    DIRECTION OUTPUT ;
    USE SIGNAL ;
    PORT
      LAYER M5 ;
        RECT  87.516 0 87.54 0.192 ;
    END
  END so[205]
  PIN so[206]
    DIRECTION OUTPUT ;
    USE SIGNAL ;
    PORT
      LAYER M5 ;
        RECT  87.804 0 87.828 0.192 ;
    END
  END so[206]
  PIN so[207]
    DIRECTION OUTPUT ;
    USE SIGNAL ;
    PORT
      LAYER M5 ;
        RECT  88.092 0 88.116 0.192 ;
    END
  END so[207]
  PIN so[208]
    DIRECTION OUTPUT ;
    USE SIGNAL ;
    PORT
      LAYER M5 ;
        RECT  88.332 0 88.356 0.192 ;
    END
  END so[208]
  PIN so[209]
    DIRECTION OUTPUT ;
    USE SIGNAL ;
    PORT
      LAYER M5 ;
        RECT  88.62 0 88.644 0.192 ;
    END
  END so[209]
  PIN so[20]
    DIRECTION OUTPUT ;
    USE SIGNAL ;
    PORT
      LAYER M5 ;
        RECT  36.732 0 36.756 0.192 ;
    END
  END so[20]
  PIN so[210]
    DIRECTION OUTPUT ;
    USE SIGNAL ;
    PORT
      LAYER M5 ;
        RECT  88.908 0 88.932 0.192 ;
    END
  END so[210]
  PIN so[211]
    DIRECTION OUTPUT ;
    USE SIGNAL ;
    PORT
      LAYER M5 ;
        RECT  89.196 0 89.22 0.192 ;
    END
  END so[211]
  PIN so[212]
    DIRECTION OUTPUT ;
    USE SIGNAL ;
    PORT
      LAYER M5 ;
        RECT  89.436 0 89.46 0.192 ;
    END
  END so[212]
  PIN so[213]
    DIRECTION OUTPUT ;
    USE SIGNAL ;
    PORT
      LAYER M5 ;
        RECT  89.724 0 89.748 0.192 ;
    END
  END so[213]
  PIN so[214]
    DIRECTION OUTPUT ;
    USE SIGNAL ;
    PORT
      LAYER M5 ;
        RECT  90.012 0 90.036 0.192 ;
    END
  END so[214]
  PIN so[215]
    DIRECTION OUTPUT ;
    USE SIGNAL ;
    PORT
      LAYER M5 ;
        RECT  90.252 0 90.276 0.192 ;
    END
  END so[215]
  PIN so[216]
    DIRECTION OUTPUT ;
    USE SIGNAL ;
    PORT
      LAYER M5 ;
        RECT  90.54 0 90.564 0.192 ;
    END
  END so[216]
  PIN so[217]
    DIRECTION OUTPUT ;
    USE SIGNAL ;
    PORT
      LAYER M5 ;
        RECT  90.828 0 90.852 0.192 ;
    END
  END so[217]
  PIN so[218]
    DIRECTION OUTPUT ;
    USE SIGNAL ;
    PORT
      LAYER M5 ;
        RECT  91.116 0 91.14 0.192 ;
    END
  END so[218]
  PIN so[219]
    DIRECTION OUTPUT ;
    USE SIGNAL ;
    PORT
      LAYER M5 ;
        RECT  91.356 0 91.38 0.192 ;
    END
  END so[219]
  PIN so[21]
    DIRECTION OUTPUT ;
    USE SIGNAL ;
    PORT
      LAYER M5 ;
        RECT  37.02 0 37.044 0.192 ;
    END
  END so[21]
  PIN so[220]
    DIRECTION OUTPUT ;
    USE SIGNAL ;
    PORT
      LAYER M5 ;
        RECT  91.644 0 91.668 0.192 ;
    END
  END so[220]
  PIN so[221]
    DIRECTION OUTPUT ;
    USE SIGNAL ;
    PORT
      LAYER M5 ;
        RECT  91.932 0 91.956 0.192 ;
    END
  END so[221]
  PIN so[222]
    DIRECTION OUTPUT ;
    USE SIGNAL ;
    PORT
      LAYER M5 ;
        RECT  92.22 0 92.244 0.192 ;
    END
  END so[222]
  PIN so[223]
    DIRECTION OUTPUT ;
    USE SIGNAL ;
    PORT
      LAYER M5 ;
        RECT  92.46 0 92.484 0.192 ;
    END
  END so[223]
  PIN so[224]
    DIRECTION OUTPUT ;
    USE SIGNAL ;
    PORT
      LAYER M5 ;
        RECT  92.748 0 92.772 0.192 ;
    END
  END so[224]
  PIN so[225]
    DIRECTION OUTPUT ;
    USE SIGNAL ;
    PORT
      LAYER M5 ;
        RECT  93.036 0 93.06 0.192 ;
    END
  END so[225]
  PIN so[226]
    DIRECTION OUTPUT ;
    USE SIGNAL ;
    PORT
      LAYER M5 ;
        RECT  93.276 0 93.3 0.192 ;
    END
  END so[226]
  PIN so[227]
    DIRECTION OUTPUT ;
    USE SIGNAL ;
    PORT
      LAYER M5 ;
        RECT  93.564 0 93.588 0.192 ;
    END
  END so[227]
  PIN so[228]
    DIRECTION OUTPUT ;
    USE SIGNAL ;
    PORT
      LAYER M5 ;
        RECT  93.852 0 93.876 0.192 ;
    END
  END so[228]
  PIN so[229]
    DIRECTION OUTPUT ;
    USE SIGNAL ;
    PORT
      LAYER M5 ;
        RECT  94.14 0 94.164 0.192 ;
    END
  END so[229]
  PIN so[22]
    DIRECTION OUTPUT ;
    USE SIGNAL ;
    PORT
      LAYER M5 ;
        RECT  37.26 0 37.284 0.192 ;
    END
  END so[22]
  PIN so[230]
    DIRECTION OUTPUT ;
    USE SIGNAL ;
    PORT
      LAYER M5 ;
        RECT  94.38 0 94.404 0.192 ;
    END
  END so[230]
  PIN so[231]
    DIRECTION OUTPUT ;
    USE SIGNAL ;
    PORT
      LAYER M5 ;
        RECT  94.668 0 94.692 0.192 ;
    END
  END so[231]
  PIN so[232]
    DIRECTION OUTPUT ;
    USE SIGNAL ;
    PORT
      LAYER M5 ;
        RECT  94.956 0 94.98 0.192 ;
    END
  END so[232]
  PIN so[233]
    DIRECTION OUTPUT ;
    USE SIGNAL ;
    PORT
      LAYER M5 ;
        RECT  95.196 0 95.22 0.192 ;
    END
  END so[233]
  PIN so[234]
    DIRECTION OUTPUT ;
    USE SIGNAL ;
    PORT
      LAYER M5 ;
        RECT  95.484 0 95.508 0.192 ;
    END
  END so[234]
  PIN so[235]
    DIRECTION OUTPUT ;
    USE SIGNAL ;
    PORT
      LAYER M5 ;
        RECT  95.772 0 95.796 0.192 ;
    END
  END so[235]
  PIN so[236]
    DIRECTION OUTPUT ;
    USE SIGNAL ;
    PORT
      LAYER M5 ;
        RECT  96.06 0 96.084 0.192 ;
    END
  END so[236]
  PIN so[237]
    DIRECTION OUTPUT ;
    USE SIGNAL ;
    PORT
      LAYER M5 ;
        RECT  96.3 0 96.324 0.192 ;
    END
  END so[237]
  PIN so[238]
    DIRECTION OUTPUT ;
    USE SIGNAL ;
    PORT
      LAYER M5 ;
        RECT  96.588 0 96.612 0.192 ;
    END
  END so[238]
  PIN so[239]
    DIRECTION OUTPUT ;
    USE SIGNAL ;
    PORT
      LAYER M5 ;
        RECT  96.876 0 96.9 0.192 ;
    END
  END so[239]
  PIN so[23]
    DIRECTION OUTPUT ;
    USE SIGNAL ;
    PORT
      LAYER M5 ;
        RECT  37.548 0 37.572 0.192 ;
    END
  END so[23]
  PIN so[240]
    DIRECTION OUTPUT ;
    USE SIGNAL ;
    PORT
      LAYER M5 ;
        RECT  97.164 0 97.188 0.192 ;
    END
  END so[240]
  PIN so[241]
    DIRECTION OUTPUT ;
    USE SIGNAL ;
    PORT
      LAYER M5 ;
        RECT  97.404 0 97.428 0.192 ;
    END
  END so[241]
  PIN so[242]
    DIRECTION OUTPUT ;
    USE SIGNAL ;
    PORT
      LAYER M5 ;
        RECT  97.692 0 97.716 0.192 ;
    END
  END so[242]
  PIN so[243]
    DIRECTION OUTPUT ;
    USE SIGNAL ;
    PORT
      LAYER M5 ;
        RECT  97.98 0 98.004 0.192 ;
    END
  END so[243]
  PIN so[244]
    DIRECTION OUTPUT ;
    USE SIGNAL ;
    PORT
      LAYER M5 ;
        RECT  98.22 0 98.244 0.192 ;
    END
  END so[244]
  PIN so[245]
    DIRECTION OUTPUT ;
    USE SIGNAL ;
    PORT
      LAYER M5 ;
        RECT  98.508 0 98.532 0.192 ;
    END
  END so[245]
  PIN so[246]
    DIRECTION OUTPUT ;
    USE SIGNAL ;
    PORT
      LAYER M5 ;
        RECT  98.796 0 98.82 0.192 ;
    END
  END so[246]
  PIN so[247]
    DIRECTION OUTPUT ;
    USE SIGNAL ;
    PORT
      LAYER M5 ;
        RECT  99.084 0 99.108 0.192 ;
    END
  END so[247]
  PIN so[248]
    DIRECTION OUTPUT ;
    USE SIGNAL ;
    PORT
      LAYER M5 ;
        RECT  99.324 0 99.348 0.192 ;
    END
  END so[248]
  PIN so[249]
    DIRECTION OUTPUT ;
    USE SIGNAL ;
    PORT
      LAYER M5 ;
        RECT  99.612 0 99.636 0.192 ;
    END
  END so[249]
  PIN so[24]
    DIRECTION OUTPUT ;
    USE SIGNAL ;
    PORT
      LAYER M5 ;
        RECT  37.836 0 37.86 0.192 ;
    END
  END so[24]
  PIN so[250]
    DIRECTION OUTPUT ;
    USE SIGNAL ;
    PORT
      LAYER M5 ;
        RECT  99.9 0 99.924 0.192 ;
    END
  END so[250]
  PIN so[251]
    DIRECTION OUTPUT ;
    USE SIGNAL ;
    PORT
      LAYER M5 ;
        RECT  100.14 0 100.164 0.192 ;
    END
  END so[251]
  PIN so[252]
    DIRECTION OUTPUT ;
    USE SIGNAL ;
    PORT
      LAYER M5 ;
        RECT  100.428 0 100.452 0.192 ;
    END
  END so[252]
  PIN so[253]
    DIRECTION OUTPUT ;
    USE SIGNAL ;
    PORT
      LAYER M5 ;
        RECT  100.716 0 100.74 0.192 ;
    END
  END so[253]
  PIN so[254]
    DIRECTION OUTPUT ;
    USE SIGNAL ;
    PORT
      LAYER M5 ;
        RECT  101.004 0 101.028 0.192 ;
    END
  END so[254]
  PIN so[255]
    DIRECTION OUTPUT ;
    USE SIGNAL ;
    PORT
      LAYER M5 ;
        RECT  101.244 0 101.268 0.192 ;
    END
  END so[255]
  PIN so[256]
    DIRECTION OUTPUT ;
    USE SIGNAL ;
    PORT
      LAYER M5 ;
        RECT  101.532 0 101.556 0.192 ;
    END
  END so[256]
  PIN so[257]
    DIRECTION OUTPUT ;
    USE SIGNAL ;
    PORT
      LAYER M5 ;
        RECT  101.82 0 101.844 0.192 ;
    END
  END so[257]
  PIN so[258]
    DIRECTION OUTPUT ;
    USE SIGNAL ;
    PORT
      LAYER M5 ;
        RECT  102.06 0 102.084 0.192 ;
    END
  END so[258]
  PIN so[259]
    DIRECTION OUTPUT ;
    USE SIGNAL ;
    PORT
      LAYER M5 ;
        RECT  102.348 0 102.372 0.192 ;
    END
  END so[259]
  PIN so[25]
    DIRECTION OUTPUT ;
    USE SIGNAL ;
    PORT
      LAYER M5 ;
        RECT  38.076 0 38.1 0.192 ;
    END
  END so[25]
  PIN so[260]
    DIRECTION OUTPUT ;
    USE SIGNAL ;
    PORT
      LAYER M5 ;
        RECT  102.636 0 102.66 0.192 ;
    END
  END so[260]
  PIN so[261]
    DIRECTION OUTPUT ;
    USE SIGNAL ;
    PORT
      LAYER M5 ;
        RECT  102.924 0 102.948 0.192 ;
    END
  END so[261]
  PIN so[262]
    DIRECTION OUTPUT ;
    USE SIGNAL ;
    PORT
      LAYER M5 ;
        RECT  103.164 0 103.188 0.192 ;
    END
  END so[262]
  PIN so[263]
    DIRECTION OUTPUT ;
    USE SIGNAL ;
    PORT
      LAYER M5 ;
        RECT  103.452 0 103.476 0.192 ;
    END
  END so[263]
  PIN so[264]
    DIRECTION OUTPUT ;
    USE SIGNAL ;
    PORT
      LAYER M5 ;
        RECT  103.74 0 103.764 0.192 ;
    END
  END so[264]
  PIN so[265]
    DIRECTION OUTPUT ;
    USE SIGNAL ;
    PORT
      LAYER M5 ;
        RECT  104.028 0 104.052 0.192 ;
    END
  END so[265]
  PIN so[266]
    DIRECTION OUTPUT ;
    USE SIGNAL ;
    PORT
      LAYER M5 ;
        RECT  104.268 0 104.292 0.192 ;
    END
  END so[266]
  PIN so[267]
    DIRECTION OUTPUT ;
    USE SIGNAL ;
    PORT
      LAYER M5 ;
        RECT  104.556 0 104.58 0.192 ;
    END
  END so[267]
  PIN so[268]
    DIRECTION OUTPUT ;
    USE SIGNAL ;
    PORT
      LAYER M5 ;
        RECT  104.844 0 104.868 0.192 ;
    END
  END so[268]
  PIN so[269]
    DIRECTION OUTPUT ;
    USE SIGNAL ;
    PORT
      LAYER M5 ;
        RECT  105.084 0 105.108 0.192 ;
    END
  END so[269]
  PIN so[26]
    DIRECTION OUTPUT ;
    USE SIGNAL ;
    PORT
      LAYER M5 ;
        RECT  38.364 0 38.388 0.192 ;
    END
  END so[26]
  PIN so[270]
    DIRECTION OUTPUT ;
    USE SIGNAL ;
    PORT
      LAYER M5 ;
        RECT  105.372 0 105.396 0.192 ;
    END
  END so[270]
  PIN so[27]
    DIRECTION OUTPUT ;
    USE SIGNAL ;
    PORT
      LAYER M5 ;
        RECT  38.652 0 38.676 0.192 ;
    END
  END so[27]
  PIN so[28]
    DIRECTION OUTPUT ;
    USE SIGNAL ;
    PORT
      LAYER M5 ;
        RECT  38.94 0 38.964 0.192 ;
    END
  END so[28]
  PIN so[29]
    DIRECTION OUTPUT ;
    USE SIGNAL ;
    PORT
      LAYER M5 ;
        RECT  39.18 0 39.204 0.192 ;
    END
  END so[29]
  PIN so[2]
    DIRECTION OUTPUT ;
    USE SIGNAL ;
    PORT
      LAYER M5 ;
        RECT  31.788 0 31.812 0.192 ;
    END
  END so[2]
  PIN so[30]
    DIRECTION OUTPUT ;
    USE SIGNAL ;
    PORT
      LAYER M5 ;
        RECT  39.468 0 39.492 0.192 ;
    END
  END so[30]
  PIN so[31]
    DIRECTION OUTPUT ;
    USE SIGNAL ;
    PORT
      LAYER M5 ;
        RECT  39.756 0 39.78 0.192 ;
    END
  END so[31]
  PIN so[32]
    DIRECTION OUTPUT ;
    USE SIGNAL ;
    PORT
      LAYER M5 ;
        RECT  40.044 0 40.068 0.192 ;
    END
  END so[32]
  PIN so[33]
    DIRECTION OUTPUT ;
    USE SIGNAL ;
    PORT
      LAYER M5 ;
        RECT  40.284 0 40.308 0.192 ;
    END
  END so[33]
  PIN so[34]
    DIRECTION OUTPUT ;
    USE SIGNAL ;
    PORT
      LAYER M5 ;
        RECT  40.572 0 40.596 0.192 ;
    END
  END so[34]
  PIN so[35]
    DIRECTION OUTPUT ;
    USE SIGNAL ;
    PORT
      LAYER M5 ;
        RECT  40.86 0 40.884 0.192 ;
    END
  END so[35]
  PIN so[36]
    DIRECTION OUTPUT ;
    USE SIGNAL ;
    PORT
      LAYER M5 ;
        RECT  41.1 0 41.124 0.192 ;
    END
  END so[36]
  PIN so[37]
    DIRECTION OUTPUT ;
    USE SIGNAL ;
    PORT
      LAYER M5 ;
        RECT  41.388 0 41.412 0.192 ;
    END
  END so[37]
  PIN so[38]
    DIRECTION OUTPUT ;
    USE SIGNAL ;
    PORT
      LAYER M5 ;
        RECT  41.676 0 41.7 0.192 ;
    END
  END so[38]
  PIN so[39]
    DIRECTION OUTPUT ;
    USE SIGNAL ;
    PORT
      LAYER M5 ;
        RECT  41.964 0 41.988 0.192 ;
    END
  END so[39]
  PIN so[3]
    DIRECTION OUTPUT ;
    USE SIGNAL ;
    PORT
      LAYER M5 ;
        RECT  32.076 0 32.1 0.192 ;
    END
  END so[3]
  PIN so[40]
    DIRECTION OUTPUT ;
    USE SIGNAL ;
    PORT
      LAYER M5 ;
        RECT  42.204 0 42.228 0.192 ;
    END
  END so[40]
  PIN so[41]
    DIRECTION OUTPUT ;
    USE SIGNAL ;
    PORT
      LAYER M5 ;
        RECT  42.492 0 42.516 0.192 ;
    END
  END so[41]
  PIN so[42]
    DIRECTION OUTPUT ;
    USE SIGNAL ;
    PORT
      LAYER M5 ;
        RECT  42.78 0 42.804 0.192 ;
    END
  END so[42]
  PIN so[43]
    DIRECTION OUTPUT ;
    USE SIGNAL ;
    PORT
      LAYER M5 ;
        RECT  43.02 0 43.044 0.192 ;
    END
  END so[43]
  PIN so[44]
    DIRECTION OUTPUT ;
    USE SIGNAL ;
    PORT
      LAYER M5 ;
        RECT  43.308 0 43.332 0.192 ;
    END
  END so[44]
  PIN so[45]
    DIRECTION OUTPUT ;
    USE SIGNAL ;
    PORT
      LAYER M5 ;
        RECT  43.596 0 43.62 0.192 ;
    END
  END so[45]
  PIN so[46]
    DIRECTION OUTPUT ;
    USE SIGNAL ;
    PORT
      LAYER M5 ;
        RECT  43.884 0 43.908 0.192 ;
    END
  END so[46]
  PIN so[47]
    DIRECTION OUTPUT ;
    USE SIGNAL ;
    PORT
      LAYER M5 ;
        RECT  44.124 0 44.148 0.192 ;
    END
  END so[47]
  PIN so[48]
    DIRECTION OUTPUT ;
    USE SIGNAL ;
    PORT
      LAYER M5 ;
        RECT  44.412 0 44.436 0.192 ;
    END
  END so[48]
  PIN so[49]
    DIRECTION OUTPUT ;
    USE SIGNAL ;
    PORT
      LAYER M5 ;
        RECT  44.7 0 44.724 0.192 ;
    END
  END so[49]
  PIN so[4]
    DIRECTION OUTPUT ;
    USE SIGNAL ;
    PORT
      LAYER M5 ;
        RECT  32.316 0 32.34 0.192 ;
    END
  END so[4]
  PIN so[50]
    DIRECTION OUTPUT ;
    USE SIGNAL ;
    PORT
      LAYER M5 ;
        RECT  44.988 0 45.012 0.192 ;
    END
  END so[50]
  PIN so[51]
    DIRECTION OUTPUT ;
    USE SIGNAL ;
    PORT
      LAYER M5 ;
        RECT  45.228 0 45.252 0.192 ;
    END
  END so[51]
  PIN so[52]
    DIRECTION OUTPUT ;
    USE SIGNAL ;
    PORT
      LAYER M5 ;
        RECT  45.516 0 45.54 0.192 ;
    END
  END so[52]
  PIN so[53]
    DIRECTION OUTPUT ;
    USE SIGNAL ;
    PORT
      LAYER M5 ;
        RECT  45.804 0 45.828 0.192 ;
    END
  END so[53]
  PIN so[54]
    DIRECTION OUTPUT ;
    USE SIGNAL ;
    PORT
      LAYER M5 ;
        RECT  46.044 0 46.068 0.192 ;
    END
  END so[54]
  PIN so[55]
    DIRECTION OUTPUT ;
    USE SIGNAL ;
    PORT
      LAYER M5 ;
        RECT  46.332 0 46.356 0.192 ;
    END
  END so[55]
  PIN so[56]
    DIRECTION OUTPUT ;
    USE SIGNAL ;
    PORT
      LAYER M5 ;
        RECT  46.62 0 46.644 0.192 ;
    END
  END so[56]
  PIN so[57]
    DIRECTION OUTPUT ;
    USE SIGNAL ;
    PORT
      LAYER M5 ;
        RECT  46.908 0 46.932 0.192 ;
    END
  END so[57]
  PIN so[58]
    DIRECTION OUTPUT ;
    USE SIGNAL ;
    PORT
      LAYER M5 ;
        RECT  47.148 0 47.172 0.192 ;
    END
  END so[58]
  PIN so[59]
    DIRECTION OUTPUT ;
    USE SIGNAL ;
    PORT
      LAYER M5 ;
        RECT  47.436 0 47.46 0.192 ;
    END
  END so[59]
  PIN so[5]
    DIRECTION OUTPUT ;
    USE SIGNAL ;
    PORT
      LAYER M5 ;
        RECT  32.604 0 32.628 0.192 ;
    END
  END so[5]
  PIN so[60]
    DIRECTION OUTPUT ;
    USE SIGNAL ;
    PORT
      LAYER M5 ;
        RECT  47.724 0 47.748 0.192 ;
    END
  END so[60]
  PIN so[61]
    DIRECTION OUTPUT ;
    USE SIGNAL ;
    PORT
      LAYER M5 ;
        RECT  47.964 0 47.988 0.192 ;
    END
  END so[61]
  PIN so[62]
    DIRECTION OUTPUT ;
    USE SIGNAL ;
    PORT
      LAYER M5 ;
        RECT  48.252 0 48.276 0.192 ;
    END
  END so[62]
  PIN so[63]
    DIRECTION OUTPUT ;
    USE SIGNAL ;
    PORT
      LAYER M5 ;
        RECT  48.54 0 48.564 0.192 ;
    END
  END so[63]
  PIN so[64]
    DIRECTION OUTPUT ;
    USE SIGNAL ;
    PORT
      LAYER M5 ;
        RECT  48.828 0 48.852 0.192 ;
    END
  END so[64]
  PIN so[65]
    DIRECTION OUTPUT ;
    USE SIGNAL ;
    PORT
      LAYER M5 ;
        RECT  49.068 0 49.092 0.192 ;
    END
  END so[65]
  PIN so[66]
    DIRECTION OUTPUT ;
    USE SIGNAL ;
    PORT
      LAYER M5 ;
        RECT  49.356 0 49.38 0.192 ;
    END
  END so[66]
  PIN so[67]
    DIRECTION OUTPUT ;
    USE SIGNAL ;
    PORT
      LAYER M5 ;
        RECT  49.644 0 49.668 0.192 ;
    END
  END so[67]
  PIN so[68]
    DIRECTION OUTPUT ;
    USE SIGNAL ;
    PORT
      LAYER M5 ;
        RECT  49.884 0 49.908 0.192 ;
    END
  END so[68]
  PIN so[69]
    DIRECTION OUTPUT ;
    USE SIGNAL ;
    PORT
      LAYER M5 ;
        RECT  50.172 0 50.196 0.192 ;
    END
  END so[69]
  PIN so[6]
    DIRECTION OUTPUT ;
    USE SIGNAL ;
    PORT
      LAYER M5 ;
        RECT  32.892 0 32.916 0.192 ;
    END
  END so[6]
  PIN so[70]
    DIRECTION OUTPUT ;
    USE SIGNAL ;
    PORT
      LAYER M5 ;
        RECT  50.46 0 50.484 0.192 ;
    END
  END so[70]
  PIN so[71]
    DIRECTION OUTPUT ;
    USE SIGNAL ;
    PORT
      LAYER M5 ;
        RECT  50.748 0 50.772 0.192 ;
    END
  END so[71]
  PIN so[72]
    DIRECTION OUTPUT ;
    USE SIGNAL ;
    PORT
      LAYER M5 ;
        RECT  50.988 0 51.012 0.192 ;
    END
  END so[72]
  PIN so[73]
    DIRECTION OUTPUT ;
    USE SIGNAL ;
    PORT
      LAYER M5 ;
        RECT  51.276 0 51.3 0.192 ;
    END
  END so[73]
  PIN so[74]
    DIRECTION OUTPUT ;
    USE SIGNAL ;
    PORT
      LAYER M5 ;
        RECT  51.564 0 51.588 0.192 ;
    END
  END so[74]
  PIN so[75]
    DIRECTION OUTPUT ;
    USE SIGNAL ;
    PORT
      LAYER M5 ;
        RECT  51.852 0 51.876 0.192 ;
    END
  END so[75]
  PIN so[76]
    DIRECTION OUTPUT ;
    USE SIGNAL ;
    PORT
      LAYER M5 ;
        RECT  52.092 0 52.116 0.192 ;
    END
  END so[76]
  PIN so[77]
    DIRECTION OUTPUT ;
    USE SIGNAL ;
    PORT
      LAYER M5 ;
        RECT  52.38 0 52.404 0.192 ;
    END
  END so[77]
  PIN so[78]
    DIRECTION OUTPUT ;
    USE SIGNAL ;
    PORT
      LAYER M5 ;
        RECT  52.668 0 52.692 0.192 ;
    END
  END so[78]
  PIN so[79]
    DIRECTION OUTPUT ;
    USE SIGNAL ;
    PORT
      LAYER M5 ;
        RECT  52.908 0 52.932 0.192 ;
    END
  END so[79]
  PIN so[7]
    DIRECTION OUTPUT ;
    USE SIGNAL ;
    PORT
      LAYER M5 ;
        RECT  33.18 0 33.204 0.192 ;
    END
  END so[7]
  PIN so[80]
    DIRECTION OUTPUT ;
    USE SIGNAL ;
    PORT
      LAYER M5 ;
        RECT  53.196 0 53.22 0.192 ;
    END
  END so[80]
  PIN so[81]
    DIRECTION OUTPUT ;
    USE SIGNAL ;
    PORT
      LAYER M5 ;
        RECT  53.484 0 53.508 0.192 ;
    END
  END so[81]
  PIN so[82]
    DIRECTION OUTPUT ;
    USE SIGNAL ;
    PORT
      LAYER M5 ;
        RECT  53.772 0 53.796 0.192 ;
    END
  END so[82]
  PIN so[83]
    DIRECTION OUTPUT ;
    USE SIGNAL ;
    PORT
      LAYER M5 ;
        RECT  54.012 0 54.036 0.192 ;
    END
  END so[83]
  PIN so[84]
    DIRECTION OUTPUT ;
    USE SIGNAL ;
    PORT
      LAYER M5 ;
        RECT  54.3 0 54.324 0.192 ;
    END
  END so[84]
  PIN so[85]
    DIRECTION OUTPUT ;
    USE SIGNAL ;
    PORT
      LAYER M5 ;
        RECT  54.588 0 54.612 0.192 ;
    END
  END so[85]
  PIN so[86]
    DIRECTION OUTPUT ;
    USE SIGNAL ;
    PORT
      LAYER M5 ;
        RECT  54.828 0 54.852 0.192 ;
    END
  END so[86]
  PIN so[87]
    DIRECTION OUTPUT ;
    USE SIGNAL ;
    PORT
      LAYER M5 ;
        RECT  55.116 0 55.14 0.192 ;
    END
  END so[87]
  PIN so[88]
    DIRECTION OUTPUT ;
    USE SIGNAL ;
    PORT
      LAYER M5 ;
        RECT  55.404 0 55.428 0.192 ;
    END
  END so[88]
  PIN so[89]
    DIRECTION OUTPUT ;
    USE SIGNAL ;
    PORT
      LAYER M5 ;
        RECT  55.692 0 55.716 0.192 ;
    END
  END so[89]
  PIN so[8]
    DIRECTION OUTPUT ;
    USE SIGNAL ;
    PORT
      LAYER M5 ;
        RECT  33.42 0 33.444 0.192 ;
    END
  END so[8]
  PIN so[90]
    DIRECTION OUTPUT ;
    USE SIGNAL ;
    PORT
      LAYER M5 ;
        RECT  55.932 0 55.956 0.192 ;
    END
  END so[90]
  PIN so[91]
    DIRECTION OUTPUT ;
    USE SIGNAL ;
    PORT
      LAYER M5 ;
        RECT  56.22 0 56.244 0.192 ;
    END
  END so[91]
  PIN so[92]
    DIRECTION OUTPUT ;
    USE SIGNAL ;
    PORT
      LAYER M5 ;
        RECT  56.508 0 56.532 0.192 ;
    END
  END so[92]
  PIN so[93]
    DIRECTION OUTPUT ;
    USE SIGNAL ;
    PORT
      LAYER M5 ;
        RECT  56.796 0 56.82 0.192 ;
    END
  END so[93]
  PIN so[94]
    DIRECTION OUTPUT ;
    USE SIGNAL ;
    PORT
      LAYER M5 ;
        RECT  57.036 0 57.06 0.192 ;
    END
  END so[94]
  PIN so[95]
    DIRECTION OUTPUT ;
    USE SIGNAL ;
    PORT
      LAYER M5 ;
        RECT  57.324 0 57.348 0.192 ;
    END
  END so[95]
  PIN so[96]
    DIRECTION OUTPUT ;
    USE SIGNAL ;
    PORT
      LAYER M5 ;
        RECT  57.612 0 57.636 0.192 ;
    END
  END so[96]
  PIN so[97]
    DIRECTION OUTPUT ;
    USE SIGNAL ;
    PORT
      LAYER M5 ;
        RECT  57.852 0 57.876 0.192 ;
    END
  END so[97]
  PIN so[98]
    DIRECTION OUTPUT ;
    USE SIGNAL ;
    PORT
      LAYER M5 ;
        RECT  58.14 0 58.164 0.192 ;
    END
  END so[98]
  PIN so[99]
    DIRECTION OUTPUT ;
    USE SIGNAL ;
    PORT
      LAYER M5 ;
        RECT  58.428 0 58.452 0.192 ;
    END
  END so[99]
  PIN so[9]
    DIRECTION OUTPUT ;
    USE SIGNAL ;
    PORT
      LAYER M5 ;
        RECT  33.708 0 33.732 0.192 ;
    END
  END so[9]
  PIN t0[0]
    DIRECTION OUTPUT ;
    USE SIGNAL ;
    PORT
      LAYER M5 ;
        RECT  105.66 0 105.684 0.192 ;
    END
  END t0[0]
  PIN t0[100]
    DIRECTION OUTPUT ;
    USE SIGNAL ;
    PORT
      LAYER M5 ;
        RECT  133.116 0 133.14 0.192 ;
    END
  END t0[100]
  PIN t0[101]
    DIRECTION OUTPUT ;
    USE SIGNAL ;
    PORT
      LAYER M5 ;
        RECT  133.404 0 133.428 0.192 ;
    END
  END t0[101]
  PIN t0[102]
    DIRECTION OUTPUT ;
    USE SIGNAL ;
    PORT
      LAYER M5 ;
        RECT  133.644 0 133.668 0.192 ;
    END
  END t0[102]
  PIN t0[103]
    DIRECTION OUTPUT ;
    USE SIGNAL ;
    PORT
      LAYER M5 ;
        RECT  133.932 0 133.956 0.192 ;
    END
  END t0[103]
  PIN t0[104]
    DIRECTION OUTPUT ;
    USE SIGNAL ;
    PORT
      LAYER M5 ;
        RECT  134.22 0 134.244 0.192 ;
    END
  END t0[104]
  PIN t0[105]
    DIRECTION OUTPUT ;
    USE SIGNAL ;
    PORT
      LAYER M5 ;
        RECT  134.508 0 134.532 0.192 ;
    END
  END t0[105]
  PIN t0[106]
    DIRECTION OUTPUT ;
    USE SIGNAL ;
    PORT
      LAYER M5 ;
        RECT  134.748 0 134.772 0.192 ;
    END
  END t0[106]
  PIN t0[107]
    DIRECTION OUTPUT ;
    USE SIGNAL ;
    PORT
      LAYER M5 ;
        RECT  135.036 0 135.06 0.192 ;
    END
  END t0[107]
  PIN t0[108]
    DIRECTION OUTPUT ;
    USE SIGNAL ;
    PORT
      LAYER M5 ;
        RECT  135.324 0 135.348 0.192 ;
    END
  END t0[108]
  PIN t0[109]
    DIRECTION OUTPUT ;
    USE SIGNAL ;
    PORT
      LAYER M5 ;
        RECT  135.564 0 135.588 0.192 ;
    END
  END t0[109]
  PIN t0[10]
    DIRECTION OUTPUT ;
    USE SIGNAL ;
    PORT
      LAYER M5 ;
        RECT  108.396 0 108.42 0.192 ;
    END
  END t0[10]
  PIN t0[110]
    DIRECTION OUTPUT ;
    USE SIGNAL ;
    PORT
      LAYER M5 ;
        RECT  135.852 0 135.876 0.192 ;
    END
  END t0[110]
  PIN t0[111]
    DIRECTION OUTPUT ;
    USE SIGNAL ;
    PORT
      LAYER M5 ;
        RECT  136.14 0 136.164 0.192 ;
    END
  END t0[111]
  PIN t0[112]
    DIRECTION OUTPUT ;
    USE SIGNAL ;
    PORT
      LAYER M5 ;
        RECT  136.428 0 136.452 0.192 ;
    END
  END t0[112]
  PIN t0[113]
    DIRECTION OUTPUT ;
    USE SIGNAL ;
    PORT
      LAYER M5 ;
        RECT  136.668 0 136.692 0.192 ;
    END
  END t0[113]
  PIN t0[114]
    DIRECTION OUTPUT ;
    USE SIGNAL ;
    PORT
      LAYER M5 ;
        RECT  136.956 0 136.98 0.192 ;
    END
  END t0[114]
  PIN t0[115]
    DIRECTION OUTPUT ;
    USE SIGNAL ;
    PORT
      LAYER M5 ;
        RECT  137.244 0 137.268 0.192 ;
    END
  END t0[115]
  PIN t0[116]
    DIRECTION OUTPUT ;
    USE SIGNAL ;
    PORT
      LAYER M5 ;
        RECT  137.532 0 137.556 0.192 ;
    END
  END t0[116]
  PIN t0[117]
    DIRECTION OUTPUT ;
    USE SIGNAL ;
    PORT
      LAYER M5 ;
        RECT  137.772 0 137.796 0.192 ;
    END
  END t0[117]
  PIN t0[118]
    DIRECTION OUTPUT ;
    USE SIGNAL ;
    PORT
      LAYER M5 ;
        RECT  138.06 0 138.084 0.192 ;
    END
  END t0[118]
  PIN t0[119]
    DIRECTION OUTPUT ;
    USE SIGNAL ;
    PORT
      LAYER M5 ;
        RECT  138.348 0 138.372 0.192 ;
    END
  END t0[119]
  PIN t0[11]
    DIRECTION OUTPUT ;
    USE SIGNAL ;
    PORT
      LAYER M5 ;
        RECT  108.684 0 108.708 0.192 ;
    END
  END t0[11]
  PIN t0[120]
    DIRECTION OUTPUT ;
    USE SIGNAL ;
    PORT
      LAYER M5 ;
        RECT  138.588 0 138.612 0.192 ;
    END
  END t0[120]
  PIN t0[121]
    DIRECTION OUTPUT ;
    USE SIGNAL ;
    PORT
      LAYER M5 ;
        RECT  138.876 0 138.9 0.192 ;
    END
  END t0[121]
  PIN t0[122]
    DIRECTION OUTPUT ;
    USE SIGNAL ;
    PORT
      LAYER M5 ;
        RECT  139.164 0 139.188 0.192 ;
    END
  END t0[122]
  PIN t0[123]
    DIRECTION OUTPUT ;
    USE SIGNAL ;
    PORT
      LAYER M5 ;
        RECT  139.452 0 139.476 0.192 ;
    END
  END t0[123]
  PIN t0[124]
    DIRECTION OUTPUT ;
    USE SIGNAL ;
    PORT
      LAYER M5 ;
        RECT  139.692 0 139.716 0.192 ;
    END
  END t0[124]
  PIN t0[125]
    DIRECTION OUTPUT ;
    USE SIGNAL ;
    PORT
      LAYER M5 ;
        RECT  139.98 0 140.004 0.192 ;
    END
  END t0[125]
  PIN t0[126]
    DIRECTION OUTPUT ;
    USE SIGNAL ;
    PORT
      LAYER M5 ;
        RECT  140.268 0 140.292 0.192 ;
    END
  END t0[126]
  PIN t0[127]
    DIRECTION OUTPUT ;
    USE SIGNAL ;
    PORT
      LAYER M5 ;
        RECT  140.508 0 140.532 0.192 ;
    END
  END t0[127]
  PIN t0[128]
    DIRECTION OUTPUT ;
    USE SIGNAL ;
    PORT
      LAYER M5 ;
        RECT  140.796 0 140.82 0.192 ;
    END
  END t0[128]
  PIN t0[129]
    DIRECTION OUTPUT ;
    USE SIGNAL ;
    PORT
      LAYER M5 ;
        RECT  141.084 0 141.108 0.192 ;
    END
  END t0[129]
  PIN t0[12]
    DIRECTION OUTPUT ;
    USE SIGNAL ;
    PORT
      LAYER M5 ;
        RECT  108.972 0 108.996 0.192 ;
    END
  END t0[12]
  PIN t0[130]
    DIRECTION OUTPUT ;
    USE SIGNAL ;
    PORT
      LAYER M5 ;
        RECT  141.372 0 141.396 0.192 ;
    END
  END t0[130]
  PIN t0[131]
    DIRECTION OUTPUT ;
    USE SIGNAL ;
    PORT
      LAYER M5 ;
        RECT  141.612 0 141.636 0.192 ;
    END
  END t0[131]
  PIN t0[132]
    DIRECTION OUTPUT ;
    USE SIGNAL ;
    PORT
      LAYER M5 ;
        RECT  141.9 0 141.924 0.192 ;
    END
  END t0[132]
  PIN t0[133]
    DIRECTION OUTPUT ;
    USE SIGNAL ;
    PORT
      LAYER M5 ;
        RECT  142.188 0 142.212 0.192 ;
    END
  END t0[133]
  PIN t0[134]
    DIRECTION OUTPUT ;
    USE SIGNAL ;
    PORT
      LAYER M5 ;
        RECT  142.428 0 142.452 0.192 ;
    END
  END t0[134]
  PIN t0[135]
    DIRECTION OUTPUT ;
    USE SIGNAL ;
    PORT
      LAYER M5 ;
        RECT  142.716 0 142.74 0.192 ;
    END
  END t0[135]
  PIN t0[136]
    DIRECTION OUTPUT ;
    USE SIGNAL ;
    PORT
      LAYER M5 ;
        RECT  143.004 0 143.028 0.192 ;
    END
  END t0[136]
  PIN t0[137]
    DIRECTION OUTPUT ;
    USE SIGNAL ;
    PORT
      LAYER M5 ;
        RECT  143.292 0 143.316 0.192 ;
    END
  END t0[137]
  PIN t0[138]
    DIRECTION OUTPUT ;
    USE SIGNAL ;
    PORT
      LAYER M5 ;
        RECT  143.532 0 143.556 0.192 ;
    END
  END t0[138]
  PIN t0[139]
    DIRECTION OUTPUT ;
    USE SIGNAL ;
    PORT
      LAYER M5 ;
        RECT  143.82 0 143.844 0.192 ;
    END
  END t0[139]
  PIN t0[13]
    DIRECTION OUTPUT ;
    USE SIGNAL ;
    PORT
      LAYER M5 ;
        RECT  109.212 0 109.236 0.192 ;
    END
  END t0[13]
  PIN t0[140]
    DIRECTION OUTPUT ;
    USE SIGNAL ;
    PORT
      LAYER M5 ;
        RECT  144.108 0 144.132 0.192 ;
    END
  END t0[140]
  PIN t0[141]
    DIRECTION OUTPUT ;
    USE SIGNAL ;
    PORT
      LAYER M5 ;
        RECT  144.396 0 144.42 0.192 ;
    END
  END t0[141]
  PIN t0[142]
    DIRECTION OUTPUT ;
    USE SIGNAL ;
    PORT
      LAYER M5 ;
        RECT  144.636 0 144.66 0.192 ;
    END
  END t0[142]
  PIN t0[143]
    DIRECTION OUTPUT ;
    USE SIGNAL ;
    PORT
      LAYER M5 ;
        RECT  144.924 0 144.948 0.192 ;
    END
  END t0[143]
  PIN t0[144]
    DIRECTION OUTPUT ;
    USE SIGNAL ;
    PORT
      LAYER M5 ;
        RECT  145.212 0 145.236 0.192 ;
    END
  END t0[144]
  PIN t0[145]
    DIRECTION OUTPUT ;
    USE SIGNAL ;
    PORT
      LAYER M5 ;
        RECT  145.452 0 145.476 0.192 ;
    END
  END t0[145]
  PIN t0[146]
    DIRECTION OUTPUT ;
    USE SIGNAL ;
    PORT
      LAYER M5 ;
        RECT  145.74 0 145.764 0.192 ;
    END
  END t0[146]
  PIN t0[147]
    DIRECTION OUTPUT ;
    USE SIGNAL ;
    PORT
      LAYER M5 ;
        RECT  146.028 0 146.052 0.192 ;
    END
  END t0[147]
  PIN t0[148]
    DIRECTION OUTPUT ;
    USE SIGNAL ;
    PORT
      LAYER M5 ;
        RECT  146.316 0 146.34 0.192 ;
    END
  END t0[148]
  PIN t0[149]
    DIRECTION OUTPUT ;
    USE SIGNAL ;
    PORT
      LAYER M5 ;
        RECT  146.556 0 146.58 0.192 ;
    END
  END t0[149]
  PIN t0[14]
    DIRECTION OUTPUT ;
    USE SIGNAL ;
    PORT
      LAYER M5 ;
        RECT  109.5 0 109.524 0.192 ;
    END
  END t0[14]
  PIN t0[150]
    DIRECTION OUTPUT ;
    USE SIGNAL ;
    PORT
      LAYER M5 ;
        RECT  146.844 0 146.868 0.192 ;
    END
  END t0[150]
  PIN t0[151]
    DIRECTION OUTPUT ;
    USE SIGNAL ;
    PORT
      LAYER M5 ;
        RECT  147.132 0 147.156 0.192 ;
    END
  END t0[151]
  PIN t0[152]
    DIRECTION OUTPUT ;
    USE SIGNAL ;
    PORT
      LAYER M5 ;
        RECT  147.372 0 147.396 0.192 ;
    END
  END t0[152]
  PIN t0[153]
    DIRECTION OUTPUT ;
    USE SIGNAL ;
    PORT
      LAYER M5 ;
        RECT  147.66 0 147.684 0.192 ;
    END
  END t0[153]
  PIN t0[154]
    DIRECTION OUTPUT ;
    USE SIGNAL ;
    PORT
      LAYER M5 ;
        RECT  147.948 0 147.972 0.192 ;
    END
  END t0[154]
  PIN t0[155]
    DIRECTION OUTPUT ;
    USE SIGNAL ;
    PORT
      LAYER M5 ;
        RECT  148.236 0 148.26 0.192 ;
    END
  END t0[155]
  PIN t0[156]
    DIRECTION OUTPUT ;
    USE SIGNAL ;
    PORT
      LAYER M5 ;
        RECT  148.476 0 148.5 0.192 ;
    END
  END t0[156]
  PIN t0[157]
    DIRECTION OUTPUT ;
    USE SIGNAL ;
    PORT
      LAYER M5 ;
        RECT  148.764 0 148.788 0.192 ;
    END
  END t0[157]
  PIN t0[158]
    DIRECTION OUTPUT ;
    USE SIGNAL ;
    PORT
      LAYER M5 ;
        RECT  149.052 0 149.076 0.192 ;
    END
  END t0[158]
  PIN t0[159]
    DIRECTION OUTPUT ;
    USE SIGNAL ;
    PORT
      LAYER M5 ;
        RECT  149.34 0 149.364 0.192 ;
    END
  END t0[159]
  PIN t0[15]
    DIRECTION OUTPUT ;
    USE SIGNAL ;
    PORT
      LAYER M5 ;
        RECT  109.788 0 109.812 0.192 ;
    END
  END t0[15]
  PIN t0[160]
    DIRECTION OUTPUT ;
    USE SIGNAL ;
    PORT
      LAYER M5 ;
        RECT  149.58 0 149.604 0.192 ;
    END
  END t0[160]
  PIN t0[161]
    DIRECTION OUTPUT ;
    USE SIGNAL ;
    PORT
      LAYER M5 ;
        RECT  149.868 0 149.892 0.192 ;
    END
  END t0[161]
  PIN t0[162]
    DIRECTION OUTPUT ;
    USE SIGNAL ;
    PORT
      LAYER M5 ;
        RECT  150.156 0 150.18 0.192 ;
    END
  END t0[162]
  PIN t0[163]
    DIRECTION OUTPUT ;
    USE SIGNAL ;
    PORT
      LAYER M5 ;
        RECT  150.396 0 150.42 0.192 ;
    END
  END t0[163]
  PIN t0[164]
    DIRECTION OUTPUT ;
    USE SIGNAL ;
    PORT
      LAYER M5 ;
        RECT  150.684 0 150.708 0.192 ;
    END
  END t0[164]
  PIN t0[165]
    DIRECTION OUTPUT ;
    USE SIGNAL ;
    PORT
      LAYER M5 ;
        RECT  150.972 0 150.996 0.192 ;
    END
  END t0[165]
  PIN t0[166]
    DIRECTION OUTPUT ;
    USE SIGNAL ;
    PORT
      LAYER M5 ;
        RECT  151.26 0 151.284 0.192 ;
    END
  END t0[166]
  PIN t0[167]
    DIRECTION OUTPUT ;
    USE SIGNAL ;
    PORT
      LAYER M5 ;
        RECT  151.5 0 151.524 0.192 ;
    END
  END t0[167]
  PIN t0[168]
    DIRECTION OUTPUT ;
    USE SIGNAL ;
    PORT
      LAYER M5 ;
        RECT  151.788 0 151.812 0.192 ;
    END
  END t0[168]
  PIN t0[169]
    DIRECTION OUTPUT ;
    USE SIGNAL ;
    PORT
      LAYER M5 ;
        RECT  152.076 0 152.1 0.192 ;
    END
  END t0[169]
  PIN t0[16]
    DIRECTION OUTPUT ;
    USE SIGNAL ;
    PORT
      LAYER M5 ;
        RECT  110.028 0 110.052 0.192 ;
    END
  END t0[16]
  PIN t0[170]
    DIRECTION OUTPUT ;
    USE SIGNAL ;
    PORT
      LAYER M5 ;
        RECT  152.316 0 152.34 0.192 ;
    END
  END t0[170]
  PIN t0[171]
    DIRECTION OUTPUT ;
    USE SIGNAL ;
    PORT
      LAYER M5 ;
        RECT  152.604 0 152.628 0.192 ;
    END
  END t0[171]
  PIN t0[172]
    DIRECTION OUTPUT ;
    USE SIGNAL ;
    PORT
      LAYER M5 ;
        RECT  152.892 0 152.916 0.192 ;
    END
  END t0[172]
  PIN t0[173]
    DIRECTION OUTPUT ;
    USE SIGNAL ;
    PORT
      LAYER M5 ;
        RECT  153.18 0 153.204 0.192 ;
    END
  END t0[173]
  PIN t0[174]
    DIRECTION OUTPUT ;
    USE SIGNAL ;
    PORT
      LAYER M5 ;
        RECT  153.42 0 153.444 0.192 ;
    END
  END t0[174]
  PIN t0[175]
    DIRECTION OUTPUT ;
    USE SIGNAL ;
    PORT
      LAYER M5 ;
        RECT  153.708 0 153.732 0.192 ;
    END
  END t0[175]
  PIN t0[176]
    DIRECTION OUTPUT ;
    USE SIGNAL ;
    PORT
      LAYER M5 ;
        RECT  153.996 0 154.02 0.192 ;
    END
  END t0[176]
  PIN t0[177]
    DIRECTION OUTPUT ;
    USE SIGNAL ;
    PORT
      LAYER M5 ;
        RECT  154.284 0 154.308 0.192 ;
    END
  END t0[177]
  PIN t0[178]
    DIRECTION OUTPUT ;
    USE SIGNAL ;
    PORT
      LAYER M5 ;
        RECT  154.524 0 154.548 0.192 ;
    END
  END t0[178]
  PIN t0[179]
    DIRECTION OUTPUT ;
    USE SIGNAL ;
    PORT
      LAYER M5 ;
        RECT  154.812 0 154.836 0.192 ;
    END
  END t0[179]
  PIN t0[17]
    DIRECTION OUTPUT ;
    USE SIGNAL ;
    PORT
      LAYER M5 ;
        RECT  110.316 0 110.34 0.192 ;
    END
  END t0[17]
  PIN t0[180]
    DIRECTION OUTPUT ;
    USE SIGNAL ;
    PORT
      LAYER M5 ;
        RECT  155.1 0 155.124 0.192 ;
    END
  END t0[180]
  PIN t0[181]
    DIRECTION OUTPUT ;
    USE SIGNAL ;
    PORT
      LAYER M5 ;
        RECT  155.34 0 155.364 0.192 ;
    END
  END t0[181]
  PIN t0[182]
    DIRECTION OUTPUT ;
    USE SIGNAL ;
    PORT
      LAYER M5 ;
        RECT  155.628 0 155.652 0.192 ;
    END
  END t0[182]
  PIN t0[183]
    DIRECTION OUTPUT ;
    USE SIGNAL ;
    PORT
      LAYER M5 ;
        RECT  155.916 0 155.94 0.192 ;
    END
  END t0[183]
  PIN t0[184]
    DIRECTION OUTPUT ;
    USE SIGNAL ;
    PORT
      LAYER M5 ;
        RECT  156.204 0 156.228 0.192 ;
    END
  END t0[184]
  PIN t0[185]
    DIRECTION OUTPUT ;
    USE SIGNAL ;
    PORT
      LAYER M5 ;
        RECT  156.444 0 156.468 0.192 ;
    END
  END t0[185]
  PIN t0[186]
    DIRECTION OUTPUT ;
    USE SIGNAL ;
    PORT
      LAYER M5 ;
        RECT  156.732 0 156.756 0.192 ;
    END
  END t0[186]
  PIN t0[187]
    DIRECTION OUTPUT ;
    USE SIGNAL ;
    PORT
      LAYER M5 ;
        RECT  157.02 0 157.044 0.192 ;
    END
  END t0[187]
  PIN t0[188]
    DIRECTION OUTPUT ;
    USE SIGNAL ;
    PORT
      LAYER M5 ;
        RECT  157.26 0 157.284 0.192 ;
    END
  END t0[188]
  PIN t0[189]
    DIRECTION OUTPUT ;
    USE SIGNAL ;
    PORT
      LAYER M5 ;
        RECT  157.548 0 157.572 0.192 ;
    END
  END t0[189]
  PIN t0[18]
    DIRECTION OUTPUT ;
    USE SIGNAL ;
    PORT
      LAYER M5 ;
        RECT  110.604 0 110.628 0.192 ;
    END
  END t0[18]
  PIN t0[190]
    DIRECTION OUTPUT ;
    USE SIGNAL ;
    PORT
      LAYER M5 ;
        RECT  157.836 0 157.86 0.192 ;
    END
  END t0[190]
  PIN t0[191]
    DIRECTION OUTPUT ;
    USE SIGNAL ;
    PORT
      LAYER M5 ;
        RECT  158.124 0 158.148 0.192 ;
    END
  END t0[191]
  PIN t0[192]
    DIRECTION OUTPUT ;
    USE SIGNAL ;
    PORT
      LAYER M5 ;
        RECT  158.364 0 158.388 0.192 ;
    END
  END t0[192]
  PIN t0[193]
    DIRECTION OUTPUT ;
    USE SIGNAL ;
    PORT
      LAYER M5 ;
        RECT  158.652 0 158.676 0.192 ;
    END
  END t0[193]
  PIN t0[194]
    DIRECTION OUTPUT ;
    USE SIGNAL ;
    PORT
      LAYER M5 ;
        RECT  158.94 0 158.964 0.192 ;
    END
  END t0[194]
  PIN t0[195]
    DIRECTION OUTPUT ;
    USE SIGNAL ;
    PORT
      LAYER M5 ;
        RECT  159.18 0 159.204 0.192 ;
    END
  END t0[195]
  PIN t0[196]
    DIRECTION OUTPUT ;
    USE SIGNAL ;
    PORT
      LAYER M5 ;
        RECT  159.468 0 159.492 0.192 ;
    END
  END t0[196]
  PIN t0[197]
    DIRECTION OUTPUT ;
    USE SIGNAL ;
    PORT
      LAYER M5 ;
        RECT  159.756 0 159.78 0.192 ;
    END
  END t0[197]
  PIN t0[198]
    DIRECTION OUTPUT ;
    USE SIGNAL ;
    PORT
      LAYER M5 ;
        RECT  160.044 0 160.068 0.192 ;
    END
  END t0[198]
  PIN t0[199]
    DIRECTION OUTPUT ;
    USE SIGNAL ;
    PORT
      LAYER M5 ;
        RECT  160.284 0 160.308 0.192 ;
    END
  END t0[199]
  PIN t0[19]
    DIRECTION OUTPUT ;
    USE SIGNAL ;
    PORT
      LAYER M5 ;
        RECT  110.892 0 110.916 0.192 ;
    END
  END t0[19]
  PIN t0[1]
    DIRECTION OUTPUT ;
    USE SIGNAL ;
    PORT
      LAYER M5 ;
        RECT  105.948 0 105.972 0.192 ;
    END
  END t0[1]
  PIN t0[200]
    DIRECTION OUTPUT ;
    USE SIGNAL ;
    PORT
      LAYER M5 ;
        RECT  160.572 0 160.596 0.192 ;
    END
  END t0[200]
  PIN t0[201]
    DIRECTION OUTPUT ;
    USE SIGNAL ;
    PORT
      LAYER M5 ;
        RECT  160.86 0 160.884 0.192 ;
    END
  END t0[201]
  PIN t0[202]
    DIRECTION OUTPUT ;
    USE SIGNAL ;
    PORT
      LAYER M5 ;
        RECT  161.148 0 161.172 0.192 ;
    END
  END t0[202]
  PIN t0[203]
    DIRECTION OUTPUT ;
    USE SIGNAL ;
    PORT
      LAYER M5 ;
        RECT  161.388 0 161.412 0.192 ;
    END
  END t0[203]
  PIN t0[204]
    DIRECTION OUTPUT ;
    USE SIGNAL ;
    PORT
      LAYER M5 ;
        RECT  161.676 0 161.7 0.192 ;
    END
  END t0[204]
  PIN t0[205]
    DIRECTION OUTPUT ;
    USE SIGNAL ;
    PORT
      LAYER M5 ;
        RECT  161.964 0 161.988 0.192 ;
    END
  END t0[205]
  PIN t0[206]
    DIRECTION OUTPUT ;
    USE SIGNAL ;
    PORT
      LAYER M5 ;
        RECT  162.204 0 162.228 0.192 ;
    END
  END t0[206]
  PIN t0[207]
    DIRECTION OUTPUT ;
    USE SIGNAL ;
    PORT
      LAYER M5 ;
        RECT  162.492 0 162.516 0.192 ;
    END
  END t0[207]
  PIN t0[208]
    DIRECTION OUTPUT ;
    USE SIGNAL ;
    PORT
      LAYER M5 ;
        RECT  162.78 0 162.804 0.192 ;
    END
  END t0[208]
  PIN t0[209]
    DIRECTION OUTPUT ;
    USE SIGNAL ;
    PORT
      LAYER M5 ;
        RECT  163.068 0 163.092 0.192 ;
    END
  END t0[209]
  PIN t0[20]
    DIRECTION OUTPUT ;
    USE SIGNAL ;
    PORT
      LAYER M5 ;
        RECT  111.132 0 111.156 0.192 ;
    END
  END t0[20]
  PIN t0[210]
    DIRECTION OUTPUT ;
    USE SIGNAL ;
    PORT
      LAYER M5 ;
        RECT  163.308 0 163.332 0.192 ;
    END
  END t0[210]
  PIN t0[211]
    DIRECTION OUTPUT ;
    USE SIGNAL ;
    PORT
      LAYER M5 ;
        RECT  163.596 0 163.62 0.192 ;
    END
  END t0[211]
  PIN t0[212]
    DIRECTION OUTPUT ;
    USE SIGNAL ;
    PORT
      LAYER M5 ;
        RECT  163.884 0 163.908 0.192 ;
    END
  END t0[212]
  PIN t0[213]
    DIRECTION OUTPUT ;
    USE SIGNAL ;
    PORT
      LAYER M5 ;
        RECT  164.124 0 164.148 0.192 ;
    END
  END t0[213]
  PIN t0[214]
    DIRECTION OUTPUT ;
    USE SIGNAL ;
    PORT
      LAYER M5 ;
        RECT  164.412 0 164.436 0.192 ;
    END
  END t0[214]
  PIN t0[215]
    DIRECTION OUTPUT ;
    USE SIGNAL ;
    PORT
      LAYER M5 ;
        RECT  164.7 0 164.724 0.192 ;
    END
  END t0[215]
  PIN t0[216]
    DIRECTION OUTPUT ;
    USE SIGNAL ;
    PORT
      LAYER M5 ;
        RECT  164.988 0 165.012 0.192 ;
    END
  END t0[216]
  PIN t0[217]
    DIRECTION OUTPUT ;
    USE SIGNAL ;
    PORT
      LAYER M5 ;
        RECT  165.228 0 165.252 0.192 ;
    END
  END t0[217]
  PIN t0[218]
    DIRECTION OUTPUT ;
    USE SIGNAL ;
    PORT
      LAYER M5 ;
        RECT  165.516 0 165.54 0.192 ;
    END
  END t0[218]
  PIN t0[219]
    DIRECTION OUTPUT ;
    USE SIGNAL ;
    PORT
      LAYER M5 ;
        RECT  165.804 0 165.828 0.192 ;
    END
  END t0[219]
  PIN t0[21]
    DIRECTION OUTPUT ;
    USE SIGNAL ;
    PORT
      LAYER M5 ;
        RECT  111.42 0 111.444 0.192 ;
    END
  END t0[21]
  PIN t0[220]
    DIRECTION OUTPUT ;
    USE SIGNAL ;
    PORT
      LAYER M5 ;
        RECT  166.092 0 166.116 0.192 ;
    END
  END t0[220]
  PIN t0[221]
    DIRECTION OUTPUT ;
    USE SIGNAL ;
    PORT
      LAYER M5 ;
        RECT  166.332 0 166.356 0.192 ;
    END
  END t0[221]
  PIN t0[222]
    DIRECTION OUTPUT ;
    USE SIGNAL ;
    PORT
      LAYER M5 ;
        RECT  166.62 0 166.644 0.192 ;
    END
  END t0[222]
  PIN t0[223]
    DIRECTION OUTPUT ;
    USE SIGNAL ;
    PORT
      LAYER M5 ;
        RECT  166.908 0 166.932 0.192 ;
    END
  END t0[223]
  PIN t0[224]
    DIRECTION OUTPUT ;
    USE SIGNAL ;
    PORT
      LAYER M5 ;
        RECT  167.148 0 167.172 0.192 ;
    END
  END t0[224]
  PIN t0[225]
    DIRECTION OUTPUT ;
    USE SIGNAL ;
    PORT
      LAYER M5 ;
        RECT  167.436 0 167.46 0.192 ;
    END
  END t0[225]
  PIN t0[226]
    DIRECTION OUTPUT ;
    USE SIGNAL ;
    PORT
      LAYER M5 ;
        RECT  167.724 0 167.748 0.192 ;
    END
  END t0[226]
  PIN t0[227]
    DIRECTION OUTPUT ;
    USE SIGNAL ;
    PORT
      LAYER M5 ;
        RECT  168.012 0 168.036 0.192 ;
    END
  END t0[227]
  PIN t0[228]
    DIRECTION OUTPUT ;
    USE SIGNAL ;
    PORT
      LAYER M5 ;
        RECT  168.252 0 168.276 0.192 ;
    END
  END t0[228]
  PIN t0[229]
    DIRECTION OUTPUT ;
    USE SIGNAL ;
    PORT
      LAYER M5 ;
        RECT  168.54 0 168.564 0.192 ;
    END
  END t0[229]
  PIN t0[22]
    DIRECTION OUTPUT ;
    USE SIGNAL ;
    PORT
      LAYER M5 ;
        RECT  111.708 0 111.732 0.192 ;
    END
  END t0[22]
  PIN t0[230]
    DIRECTION OUTPUT ;
    USE SIGNAL ;
    PORT
      LAYER M5 ;
        RECT  168.828 0 168.852 0.192 ;
    END
  END t0[230]
  PIN t0[231]
    DIRECTION OUTPUT ;
    USE SIGNAL ;
    PORT
      LAYER M5 ;
        RECT  169.068 0 169.092 0.192 ;
    END
  END t0[231]
  PIN t0[232]
    DIRECTION OUTPUT ;
    USE SIGNAL ;
    PORT
      LAYER M5 ;
        RECT  169.356 0 169.38 0.192 ;
    END
  END t0[232]
  PIN t0[233]
    DIRECTION OUTPUT ;
    USE SIGNAL ;
    PORT
      LAYER M5 ;
        RECT  169.644 0 169.668 0.192 ;
    END
  END t0[233]
  PIN t0[234]
    DIRECTION OUTPUT ;
    USE SIGNAL ;
    PORT
      LAYER M5 ;
        RECT  169.932 0 169.956 0.192 ;
    END
  END t0[234]
  PIN t0[235]
    DIRECTION OUTPUT ;
    USE SIGNAL ;
    PORT
      LAYER M5 ;
        RECT  170.172 0 170.196 0.192 ;
    END
  END t0[235]
  PIN t0[236]
    DIRECTION OUTPUT ;
    USE SIGNAL ;
    PORT
      LAYER M5 ;
        RECT  170.46 0 170.484 0.192 ;
    END
  END t0[236]
  PIN t0[237]
    DIRECTION OUTPUT ;
    USE SIGNAL ;
    PORT
      LAYER M5 ;
        RECT  170.748 0 170.772 0.192 ;
    END
  END t0[237]
  PIN t0[238]
    DIRECTION OUTPUT ;
    USE SIGNAL ;
    PORT
      LAYER M5 ;
        RECT  170.988 0 171.012 0.192 ;
    END
  END t0[238]
  PIN t0[239]
    DIRECTION OUTPUT ;
    USE SIGNAL ;
    PORT
      LAYER M5 ;
        RECT  171.276 0 171.3 0.192 ;
    END
  END t0[239]
  PIN t0[23]
    DIRECTION OUTPUT ;
    USE SIGNAL ;
    PORT
      LAYER M5 ;
        RECT  111.948 0 111.972 0.192 ;
    END
  END t0[23]
  PIN t0[240]
    DIRECTION OUTPUT ;
    USE SIGNAL ;
    PORT
      LAYER M5 ;
        RECT  171.564 0 171.588 0.192 ;
    END
  END t0[240]
  PIN t0[241]
    DIRECTION OUTPUT ;
    USE SIGNAL ;
    PORT
      LAYER M5 ;
        RECT  171.852 0 171.876 0.192 ;
    END
  END t0[241]
  PIN t0[242]
    DIRECTION OUTPUT ;
    USE SIGNAL ;
    PORT
      LAYER M5 ;
        RECT  172.092 0 172.116 0.192 ;
    END
  END t0[242]
  PIN t0[243]
    DIRECTION OUTPUT ;
    USE SIGNAL ;
    PORT
      LAYER M5 ;
        RECT  172.38 0 172.404 0.192 ;
    END
  END t0[243]
  PIN t0[244]
    DIRECTION OUTPUT ;
    USE SIGNAL ;
    PORT
      LAYER M5 ;
        RECT  172.668 0 172.692 0.192 ;
    END
  END t0[244]
  PIN t0[245]
    DIRECTION OUTPUT ;
    USE SIGNAL ;
    PORT
      LAYER M5 ;
        RECT  172.956 0 172.98 0.192 ;
    END
  END t0[245]
  PIN t0[246]
    DIRECTION OUTPUT ;
    USE SIGNAL ;
    PORT
      LAYER M5 ;
        RECT  173.196 0 173.22 0.192 ;
    END
  END t0[246]
  PIN t0[247]
    DIRECTION OUTPUT ;
    USE SIGNAL ;
    PORT
      LAYER M5 ;
        RECT  173.484 0 173.508 0.192 ;
    END
  END t0[247]
  PIN t0[248]
    DIRECTION OUTPUT ;
    USE SIGNAL ;
    PORT
      LAYER M5 ;
        RECT  173.772 0 173.796 0.192 ;
    END
  END t0[248]
  PIN t0[249]
    DIRECTION OUTPUT ;
    USE SIGNAL ;
    PORT
      LAYER M5 ;
        RECT  174.012 0 174.036 0.192 ;
    END
  END t0[249]
  PIN t0[24]
    DIRECTION OUTPUT ;
    USE SIGNAL ;
    PORT
      LAYER M5 ;
        RECT  112.236 0 112.26 0.192 ;
    END
  END t0[24]
  PIN t0[250]
    DIRECTION OUTPUT ;
    USE SIGNAL ;
    PORT
      LAYER M5 ;
        RECT  174.3 0 174.324 0.192 ;
    END
  END t0[250]
  PIN t0[251]
    DIRECTION OUTPUT ;
    USE SIGNAL ;
    PORT
      LAYER M5 ;
        RECT  174.588 0 174.612 0.192 ;
    END
  END t0[251]
  PIN t0[252]
    DIRECTION OUTPUT ;
    USE SIGNAL ;
    PORT
      LAYER M5 ;
        RECT  174.876 0 174.9 0.192 ;
    END
  END t0[252]
  PIN t0[253]
    DIRECTION OUTPUT ;
    USE SIGNAL ;
    PORT
      LAYER M5 ;
        RECT  175.116 0 175.14 0.192 ;
    END
  END t0[253]
  PIN t0[254]
    DIRECTION OUTPUT ;
    USE SIGNAL ;
    PORT
      LAYER M5 ;
        RECT  175.404 0 175.428 0.192 ;
    END
  END t0[254]
  PIN t0[255]
    DIRECTION OUTPUT ;
    USE SIGNAL ;
    PORT
      LAYER M5 ;
        RECT  175.692 0 175.716 0.192 ;
    END
  END t0[255]
  PIN t0[256]
    DIRECTION OUTPUT ;
    USE SIGNAL ;
    PORT
      LAYER M5 ;
        RECT  175.932 0 175.956 0.192 ;
    END
  END t0[256]
  PIN t0[257]
    DIRECTION OUTPUT ;
    USE SIGNAL ;
    PORT
      LAYER M5 ;
        RECT  176.22 0 176.244 0.192 ;
    END
  END t0[257]
  PIN t0[258]
    DIRECTION OUTPUT ;
    USE SIGNAL ;
    PORT
      LAYER M5 ;
        RECT  176.508 0 176.532 0.192 ;
    END
  END t0[258]
  PIN t0[259]
    DIRECTION OUTPUT ;
    USE SIGNAL ;
    PORT
      LAYER M5 ;
        RECT  176.796 0 176.82 0.192 ;
    END
  END t0[259]
  PIN t0[25]
    DIRECTION OUTPUT ;
    USE SIGNAL ;
    PORT
      LAYER M5 ;
        RECT  112.524 0 112.548 0.192 ;
    END
  END t0[25]
  PIN t0[260]
    DIRECTION OUTPUT ;
    USE SIGNAL ;
    PORT
      LAYER M5 ;
        RECT  177.036 0 177.06 0.192 ;
    END
  END t0[260]
  PIN t0[261]
    DIRECTION OUTPUT ;
    USE SIGNAL ;
    PORT
      LAYER M5 ;
        RECT  177.324 0 177.348 0.192 ;
    END
  END t0[261]
  PIN t0[262]
    DIRECTION OUTPUT ;
    USE SIGNAL ;
    PORT
      LAYER M5 ;
        RECT  177.612 0 177.636 0.192 ;
    END
  END t0[262]
  PIN t0[263]
    DIRECTION OUTPUT ;
    USE SIGNAL ;
    PORT
      LAYER M5 ;
        RECT  177.9 0 177.924 0.192 ;
    END
  END t0[263]
  PIN t0[264]
    DIRECTION OUTPUT ;
    USE SIGNAL ;
    PORT
      LAYER M5 ;
        RECT  178.14 0 178.164 0.192 ;
    END
  END t0[264]
  PIN t0[265]
    DIRECTION OUTPUT ;
    USE SIGNAL ;
    PORT
      LAYER M5 ;
        RECT  178.428 0 178.452 0.192 ;
    END
  END t0[265]
  PIN t0[266]
    DIRECTION OUTPUT ;
    USE SIGNAL ;
    PORT
      LAYER M5 ;
        RECT  178.716 0 178.74 0.192 ;
    END
  END t0[266]
  PIN t0[267]
    DIRECTION OUTPUT ;
    USE SIGNAL ;
    PORT
      LAYER M5 ;
        RECT  178.956 0 178.98 0.192 ;
    END
  END t0[267]
  PIN t0[268]
    DIRECTION OUTPUT ;
    USE SIGNAL ;
    PORT
      LAYER M5 ;
        RECT  179.244 0 179.268 0.192 ;
    END
  END t0[268]
  PIN t0[269]
    DIRECTION OUTPUT ;
    USE SIGNAL ;
    PORT
      LAYER M5 ;
        RECT  179.532 0 179.556 0.192 ;
    END
  END t0[269]
  PIN t0[26]
    DIRECTION OUTPUT ;
    USE SIGNAL ;
    PORT
      LAYER M5 ;
        RECT  112.812 0 112.836 0.192 ;
    END
  END t0[26]
  PIN t0[270]
    DIRECTION OUTPUT ;
    USE SIGNAL ;
    PORT
      LAYER M5 ;
        RECT  179.82 0 179.844 0.192 ;
    END
  END t0[270]
  PIN t0[271]
    DIRECTION OUTPUT ;
    USE SIGNAL ;
    PORT
      LAYER M5 ;
        RECT  180.06 0 180.084 0.192 ;
    END
  END t0[271]
  PIN t0[272]
    DIRECTION OUTPUT ;
    USE SIGNAL ;
    PORT
      LAYER M5 ;
        RECT  180.348 0 180.372 0.192 ;
    END
  END t0[272]
  PIN t0[273]
    DIRECTION OUTPUT ;
    USE SIGNAL ;
    PORT
      LAYER M5 ;
        RECT  180.636 0 180.66 0.192 ;
    END
  END t0[273]
  PIN t0[274]
    DIRECTION OUTPUT ;
    USE SIGNAL ;
    PORT
      LAYER M5 ;
        RECT  180.876 0 180.9 0.192 ;
    END
  END t0[274]
  PIN t0[275]
    DIRECTION OUTPUT ;
    USE SIGNAL ;
    PORT
      LAYER M5 ;
        RECT  181.164 0 181.188 0.192 ;
    END
  END t0[275]
  PIN t0[276]
    DIRECTION OUTPUT ;
    USE SIGNAL ;
    PORT
      LAYER M5 ;
        RECT  181.452 0 181.476 0.192 ;
    END
  END t0[276]
  PIN t0[277]
    DIRECTION OUTPUT ;
    USE SIGNAL ;
    PORT
      LAYER M5 ;
        RECT  181.74 0 181.764 0.192 ;
    END
  END t0[277]
  PIN t0[278]
    DIRECTION OUTPUT ;
    USE SIGNAL ;
    PORT
      LAYER M5 ;
        RECT  181.98 0 182.004 0.192 ;
    END
  END t0[278]
  PIN t0[279]
    DIRECTION OUTPUT ;
    USE SIGNAL ;
    PORT
      LAYER M5 ;
        RECT  182.268 0 182.292 0.192 ;
    END
  END t0[279]
  PIN t0[27]
    DIRECTION OUTPUT ;
    USE SIGNAL ;
    PORT
      LAYER M5 ;
        RECT  113.052 0 113.076 0.192 ;
    END
  END t0[27]
  PIN t0[280]
    DIRECTION OUTPUT ;
    USE SIGNAL ;
    PORT
      LAYER M5 ;
        RECT  182.556 0 182.58 0.192 ;
    END
  END t0[280]
  PIN t0[281]
    DIRECTION OUTPUT ;
    USE SIGNAL ;
    PORT
      LAYER M5 ;
        RECT  182.796 0 182.82 0.192 ;
    END
  END t0[281]
  PIN t0[282]
    DIRECTION OUTPUT ;
    USE SIGNAL ;
    PORT
      LAYER M5 ;
        RECT  183.084 0 183.108 0.192 ;
    END
  END t0[282]
  PIN t0[283]
    DIRECTION OUTPUT ;
    USE SIGNAL ;
    PORT
      LAYER M5 ;
        RECT  183.372 0 183.396 0.192 ;
    END
  END t0[283]
  PIN t0[284]
    DIRECTION OUTPUT ;
    USE SIGNAL ;
    PORT
      LAYER M5 ;
        RECT  183.66 0 183.684 0.192 ;
    END
  END t0[284]
  PIN t0[285]
    DIRECTION OUTPUT ;
    USE SIGNAL ;
    PORT
      LAYER M5 ;
        RECT  183.9 0 183.924 0.192 ;
    END
  END t0[285]
  PIN t0[286]
    DIRECTION OUTPUT ;
    USE SIGNAL ;
    PORT
      LAYER M5 ;
        RECT  184.188 0 184.212 0.192 ;
    END
  END t0[286]
  PIN t0[287]
    DIRECTION OUTPUT ;
    USE SIGNAL ;
    PORT
      LAYER M5 ;
        RECT  184.476 0 184.5 0.192 ;
    END
  END t0[287]
  PIN t0[288]
    DIRECTION OUTPUT ;
    USE SIGNAL ;
    PORT
      LAYER M5 ;
        RECT  184.764 0 184.788 0.192 ;
    END
  END t0[288]
  PIN t0[289]
    DIRECTION OUTPUT ;
    USE SIGNAL ;
    PORT
      LAYER M5 ;
        RECT  185.004 0 185.028 0.192 ;
    END
  END t0[289]
  PIN t0[28]
    DIRECTION OUTPUT ;
    USE SIGNAL ;
    PORT
      LAYER M5 ;
        RECT  113.34 0 113.364 0.192 ;
    END
  END t0[28]
  PIN t0[290]
    DIRECTION OUTPUT ;
    USE SIGNAL ;
    PORT
      LAYER M5 ;
        RECT  185.292 0 185.316 0.192 ;
    END
  END t0[290]
  PIN t0[291]
    DIRECTION OUTPUT ;
    USE SIGNAL ;
    PORT
      LAYER M5 ;
        RECT  185.58 0 185.604 0.192 ;
    END
  END t0[291]
  PIN t0[292]
    DIRECTION OUTPUT ;
    USE SIGNAL ;
    PORT
      LAYER M5 ;
        RECT  185.82 0 185.844 0.192 ;
    END
  END t0[292]
  PIN t0[293]
    DIRECTION OUTPUT ;
    USE SIGNAL ;
    PORT
      LAYER M5 ;
        RECT  186.108 0 186.132 0.192 ;
    END
  END t0[293]
  PIN t0[294]
    DIRECTION OUTPUT ;
    USE SIGNAL ;
    PORT
      LAYER M5 ;
        RECT  186.396 0 186.42 0.192 ;
    END
  END t0[294]
  PIN t0[295]
    DIRECTION OUTPUT ;
    USE SIGNAL ;
    PORT
      LAYER M5 ;
        RECT  186.684 0 186.708 0.192 ;
    END
  END t0[295]
  PIN t0[296]
    DIRECTION OUTPUT ;
    USE SIGNAL ;
    PORT
      LAYER M5 ;
        RECT  186.924 0 186.948 0.192 ;
    END
  END t0[296]
  PIN t0[297]
    DIRECTION OUTPUT ;
    USE SIGNAL ;
    PORT
      LAYER M5 ;
        RECT  187.212 0 187.236 0.192 ;
    END
  END t0[297]
  PIN t0[298]
    DIRECTION OUTPUT ;
    USE SIGNAL ;
    PORT
      LAYER M5 ;
        RECT  187.5 0 187.524 0.192 ;
    END
  END t0[298]
  PIN t0[299]
    DIRECTION OUTPUT ;
    USE SIGNAL ;
    PORT
      LAYER M5 ;
        RECT  187.74 0 187.764 0.192 ;
    END
  END t0[299]
  PIN t0[29]
    DIRECTION OUTPUT ;
    USE SIGNAL ;
    PORT
      LAYER M5 ;
        RECT  113.628 0 113.652 0.192 ;
    END
  END t0[29]
  PIN t0[2]
    DIRECTION OUTPUT ;
    USE SIGNAL ;
    PORT
      LAYER M5 ;
        RECT  106.188 0 106.212 0.192 ;
    END
  END t0[2]
  PIN t0[300]
    DIRECTION OUTPUT ;
    USE SIGNAL ;
    PORT
      LAYER M5 ;
        RECT  188.028 0 188.052 0.192 ;
    END
  END t0[300]
  PIN t0[301]
    DIRECTION OUTPUT ;
    USE SIGNAL ;
    PORT
      LAYER M5 ;
        RECT  188.316 0 188.34 0.192 ;
    END
  END t0[301]
  PIN t0[302]
    DIRECTION OUTPUT ;
    USE SIGNAL ;
    PORT
      LAYER M5 ;
        RECT  188.604 0 188.628 0.192 ;
    END
  END t0[302]
  PIN t0[303]
    DIRECTION OUTPUT ;
    USE SIGNAL ;
    PORT
      LAYER M5 ;
        RECT  188.844 0 188.868 0.192 ;
    END
  END t0[303]
  PIN t0[304]
    DIRECTION OUTPUT ;
    USE SIGNAL ;
    PORT
      LAYER M5 ;
        RECT  189.132 0 189.156 0.192 ;
    END
  END t0[304]
  PIN t0[305]
    DIRECTION OUTPUT ;
    USE SIGNAL ;
    PORT
      LAYER M5 ;
        RECT  189.42 0 189.444 0.192 ;
    END
  END t0[305]
  PIN t0[306]
    DIRECTION OUTPUT ;
    USE SIGNAL ;
    PORT
      LAYER M5 ;
        RECT  189.708 0 189.732 0.192 ;
    END
  END t0[306]
  PIN t0[307]
    DIRECTION OUTPUT ;
    USE SIGNAL ;
    PORT
      LAYER M5 ;
        RECT  189.948 0 189.972 0.192 ;
    END
  END t0[307]
  PIN t0[308]
    DIRECTION OUTPUT ;
    USE SIGNAL ;
    PORT
      LAYER M5 ;
        RECT  190.236 0 190.26 0.192 ;
    END
  END t0[308]
  PIN t0[309]
    DIRECTION OUTPUT ;
    USE SIGNAL ;
    PORT
      LAYER M5 ;
        RECT  190.524 0 190.548 0.192 ;
    END
  END t0[309]
  PIN t0[30]
    DIRECTION OUTPUT ;
    USE SIGNAL ;
    PORT
      LAYER M5 ;
        RECT  113.916 0 113.94 0.192 ;
    END
  END t0[30]
  PIN t0[310]
    DIRECTION OUTPUT ;
    USE SIGNAL ;
    PORT
      LAYER M5 ;
        RECT  190.764 0 190.788 0.192 ;
    END
  END t0[310]
  PIN t0[311]
    DIRECTION OUTPUT ;
    USE SIGNAL ;
    PORT
      LAYER M5 ;
        RECT  191.052 0 191.076 0.192 ;
    END
  END t0[311]
  PIN t0[312]
    DIRECTION OUTPUT ;
    USE SIGNAL ;
    PORT
      LAYER M5 ;
        RECT  191.34 0 191.364 0.192 ;
    END
  END t0[312]
  PIN t0[313]
    DIRECTION OUTPUT ;
    USE SIGNAL ;
    PORT
      LAYER M5 ;
        RECT  191.628 0 191.652 0.192 ;
    END
  END t0[313]
  PIN t0[314]
    DIRECTION OUTPUT ;
    USE SIGNAL ;
    PORT
      LAYER M5 ;
        RECT  191.868 0 191.892 0.192 ;
    END
  END t0[314]
  PIN t0[315]
    DIRECTION OUTPUT ;
    USE SIGNAL ;
    PORT
      LAYER M5 ;
        RECT  192.156 0 192.18 0.192 ;
    END
  END t0[315]
  PIN t0[316]
    DIRECTION OUTPUT ;
    USE SIGNAL ;
    PORT
      LAYER M5 ;
        RECT  192.444 0 192.468 0.192 ;
    END
  END t0[316]
  PIN t0[317]
    DIRECTION OUTPUT ;
    USE SIGNAL ;
    PORT
      LAYER M5 ;
        RECT  192.684 0 192.708 0.192 ;
    END
  END t0[317]
  PIN t0[318]
    DIRECTION OUTPUT ;
    USE SIGNAL ;
    PORT
      LAYER M5 ;
        RECT  192.972 0 192.996 0.192 ;
    END
  END t0[318]
  PIN t0[319]
    DIRECTION OUTPUT ;
    USE SIGNAL ;
    PORT
      LAYER M5 ;
        RECT  193.26 0 193.284 0.192 ;
    END
  END t0[319]
  PIN t0[31]
    DIRECTION OUTPUT ;
    USE SIGNAL ;
    PORT
      LAYER M5 ;
        RECT  114.156 0 114.18 0.192 ;
    END
  END t0[31]
  PIN t0[320]
    DIRECTION OUTPUT ;
    USE SIGNAL ;
    PORT
      LAYER M5 ;
        RECT  193.548 0 193.572 0.192 ;
    END
  END t0[320]
  PIN t0[321]
    DIRECTION OUTPUT ;
    USE SIGNAL ;
    PORT
      LAYER M5 ;
        RECT  193.788 0 193.812 0.192 ;
    END
  END t0[321]
  PIN t0[322]
    DIRECTION OUTPUT ;
    USE SIGNAL ;
    PORT
      LAYER M5 ;
        RECT  194.076 0 194.1 0.192 ;
    END
  END t0[322]
  PIN t0[323]
    DIRECTION OUTPUT ;
    USE SIGNAL ;
    PORT
      LAYER M5 ;
        RECT  194.364 0 194.388 0.192 ;
    END
  END t0[323]
  PIN t0[324]
    DIRECTION OUTPUT ;
    USE SIGNAL ;
    PORT
      LAYER M5 ;
        RECT  194.604 0 194.628 0.192 ;
    END
  END t0[324]
  PIN t0[325]
    DIRECTION OUTPUT ;
    USE SIGNAL ;
    PORT
      LAYER M5 ;
        RECT  194.892 0 194.916 0.192 ;
    END
  END t0[325]
  PIN t0[326]
    DIRECTION OUTPUT ;
    USE SIGNAL ;
    PORT
      LAYER M5 ;
        RECT  195.18 0 195.204 0.192 ;
    END
  END t0[326]
  PIN t0[327]
    DIRECTION OUTPUT ;
    USE SIGNAL ;
    PORT
      LAYER M5 ;
        RECT  195.468 0 195.492 0.192 ;
    END
  END t0[327]
  PIN t0[328]
    DIRECTION OUTPUT ;
    USE SIGNAL ;
    PORT
      LAYER M5 ;
        RECT  195.708 0 195.732 0.192 ;
    END
  END t0[328]
  PIN t0[329]
    DIRECTION OUTPUT ;
    USE SIGNAL ;
    PORT
      LAYER M5 ;
        RECT  195.996 0 196.02 0.192 ;
    END
  END t0[329]
  PIN t0[32]
    DIRECTION OUTPUT ;
    USE SIGNAL ;
    PORT
      LAYER M5 ;
        RECT  114.444 0 114.468 0.192 ;
    END
  END t0[32]
  PIN t0[330]
    DIRECTION OUTPUT ;
    USE SIGNAL ;
    PORT
      LAYER M5 ;
        RECT  196.284 0 196.308 0.192 ;
    END
  END t0[330]
  PIN t0[331]
    DIRECTION OUTPUT ;
    USE SIGNAL ;
    PORT
      LAYER M5 ;
        RECT  196.572 0 196.596 0.192 ;
    END
  END t0[331]
  PIN t0[332]
    DIRECTION OUTPUT ;
    USE SIGNAL ;
    PORT
      LAYER M5 ;
        RECT  196.812 0 196.836 0.192 ;
    END
  END t0[332]
  PIN t0[333]
    DIRECTION OUTPUT ;
    USE SIGNAL ;
    PORT
      LAYER M5 ;
        RECT  197.1 0 197.124 0.192 ;
    END
  END t0[333]
  PIN t0[334]
    DIRECTION OUTPUT ;
    USE SIGNAL ;
    PORT
      LAYER M5 ;
        RECT  197.388 0 197.412 0.192 ;
    END
  END t0[334]
  PIN t0[335]
    DIRECTION OUTPUT ;
    USE SIGNAL ;
    PORT
      LAYER M5 ;
        RECT  197.628 0 197.652 0.192 ;
    END
  END t0[335]
  PIN t0[336]
    DIRECTION OUTPUT ;
    USE SIGNAL ;
    PORT
      LAYER M5 ;
        RECT  197.916 0 197.94 0.192 ;
    END
  END t0[336]
  PIN t0[337]
    DIRECTION OUTPUT ;
    USE SIGNAL ;
    PORT
      LAYER M5 ;
        RECT  198.204 0 198.228 0.192 ;
    END
  END t0[337]
  PIN t0[338]
    DIRECTION OUTPUT ;
    USE SIGNAL ;
    PORT
      LAYER M5 ;
        RECT  198.492 0 198.516 0.192 ;
    END
  END t0[338]
  PIN t0[339]
    DIRECTION OUTPUT ;
    USE SIGNAL ;
    PORT
      LAYER M5 ;
        RECT  198.732 0 198.756 0.192 ;
    END
  END t0[339]
  PIN t0[33]
    DIRECTION OUTPUT ;
    USE SIGNAL ;
    PORT
      LAYER M5 ;
        RECT  114.732 0 114.756 0.192 ;
    END
  END t0[33]
  PIN t0[340]
    DIRECTION OUTPUT ;
    USE SIGNAL ;
    PORT
      LAYER M5 ;
        RECT  199.02 0 199.044 0.192 ;
    END
  END t0[340]
  PIN t0[341]
    DIRECTION OUTPUT ;
    USE SIGNAL ;
    PORT
      LAYER M5 ;
        RECT  199.308 0 199.332 0.192 ;
    END
  END t0[341]
  PIN t0[342]
    DIRECTION OUTPUT ;
    USE SIGNAL ;
    PORT
      LAYER M5 ;
        RECT  199.548 0 199.572 0.192 ;
    END
  END t0[342]
  PIN t0[343]
    DIRECTION OUTPUT ;
    USE SIGNAL ;
    PORT
      LAYER M5 ;
        RECT  199.836 0 199.86 0.192 ;
    END
  END t0[343]
  PIN t0[344]
    DIRECTION OUTPUT ;
    USE SIGNAL ;
    PORT
      LAYER M5 ;
        RECT  200.124 0 200.148 0.192 ;
    END
  END t0[344]
  PIN t0[345]
    DIRECTION OUTPUT ;
    USE SIGNAL ;
    PORT
      LAYER M5 ;
        RECT  200.412 0 200.436 0.192 ;
    END
  END t0[345]
  PIN t0[346]
    DIRECTION OUTPUT ;
    USE SIGNAL ;
    PORT
      LAYER M5 ;
        RECT  200.652 0 200.676 0.192 ;
    END
  END t0[346]
  PIN t0[347]
    DIRECTION OUTPUT ;
    USE SIGNAL ;
    PORT
      LAYER M5 ;
        RECT  200.94 0 200.964 0.192 ;
    END
  END t0[347]
  PIN t0[348]
    DIRECTION OUTPUT ;
    USE SIGNAL ;
    PORT
      LAYER M5 ;
        RECT  201.228 0 201.252 0.192 ;
    END
  END t0[348]
  PIN t0[349]
    DIRECTION OUTPUT ;
    USE SIGNAL ;
    PORT
      LAYER M5 ;
        RECT  201.516 0 201.54 0.192 ;
    END
  END t0[349]
  PIN t0[34]
    DIRECTION OUTPUT ;
    USE SIGNAL ;
    PORT
      LAYER M5 ;
        RECT  114.972 0 114.996 0.192 ;
    END
  END t0[34]
  PIN t0[350]
    DIRECTION OUTPUT ;
    USE SIGNAL ;
    PORT
      LAYER M5 ;
        RECT  201.756 0 201.78 0.192 ;
    END
  END t0[350]
  PIN t0[351]
    DIRECTION OUTPUT ;
    USE SIGNAL ;
    PORT
      LAYER M5 ;
        RECT  202.044 0 202.068 0.192 ;
    END
  END t0[351]
  PIN t0[352]
    DIRECTION OUTPUT ;
    USE SIGNAL ;
    PORT
      LAYER M5 ;
        RECT  202.332 0 202.356 0.192 ;
    END
  END t0[352]
  PIN t0[353]
    DIRECTION OUTPUT ;
    USE SIGNAL ;
    PORT
      LAYER M5 ;
        RECT  202.572 0 202.596 0.192 ;
    END
  END t0[353]
  PIN t0[354]
    DIRECTION OUTPUT ;
    USE SIGNAL ;
    PORT
      LAYER M5 ;
        RECT  202.86 0 202.884 0.192 ;
    END
  END t0[354]
  PIN t0[355]
    DIRECTION OUTPUT ;
    USE SIGNAL ;
    PORT
      LAYER M5 ;
        RECT  203.148 0 203.172 0.192 ;
    END
  END t0[355]
  PIN t0[356]
    DIRECTION OUTPUT ;
    USE SIGNAL ;
    PORT
      LAYER M5 ;
        RECT  203.436 0 203.46 0.192 ;
    END
  END t0[356]
  PIN t0[357]
    DIRECTION OUTPUT ;
    USE SIGNAL ;
    PORT
      LAYER M5 ;
        RECT  203.676 0 203.7 0.192 ;
    END
  END t0[357]
  PIN t0[358]
    DIRECTION OUTPUT ;
    USE SIGNAL ;
    PORT
      LAYER M5 ;
        RECT  203.964 0 203.988 0.192 ;
    END
  END t0[358]
  PIN t0[359]
    DIRECTION OUTPUT ;
    USE SIGNAL ;
    PORT
      LAYER M5 ;
        RECT  204.252 0 204.276 0.192 ;
    END
  END t0[359]
  PIN t0[35]
    DIRECTION OUTPUT ;
    USE SIGNAL ;
    PORT
      LAYER M5 ;
        RECT  115.26 0 115.284 0.192 ;
    END
  END t0[35]
  PIN t0[360]
    DIRECTION OUTPUT ;
    USE SIGNAL ;
    PORT
      LAYER M5 ;
        RECT  204.492 0 204.516 0.192 ;
    END
  END t0[360]
  PIN t0[361]
    DIRECTION OUTPUT ;
    USE SIGNAL ;
    PORT
      LAYER M5 ;
        RECT  204.78 0 204.804 0.192 ;
    END
  END t0[361]
  PIN t0[362]
    DIRECTION OUTPUT ;
    USE SIGNAL ;
    PORT
      LAYER M5 ;
        RECT  205.068 0 205.092 0.192 ;
    END
  END t0[362]
  PIN t0[363]
    DIRECTION OUTPUT ;
    USE SIGNAL ;
    PORT
      LAYER M5 ;
        RECT  205.356 0 205.38 0.192 ;
    END
  END t0[363]
  PIN t0[364]
    DIRECTION OUTPUT ;
    USE SIGNAL ;
    PORT
      LAYER M5 ;
        RECT  205.596 0 205.62 0.192 ;
    END
  END t0[364]
  PIN t0[365]
    DIRECTION OUTPUT ;
    USE SIGNAL ;
    PORT
      LAYER M5 ;
        RECT  205.884 0 205.908 0.192 ;
    END
  END t0[365]
  PIN t0[366]
    DIRECTION OUTPUT ;
    USE SIGNAL ;
    PORT
      LAYER M5 ;
        RECT  206.172 0 206.196 0.192 ;
    END
  END t0[366]
  PIN t0[367]
    DIRECTION OUTPUT ;
    USE SIGNAL ;
    PORT
      LAYER M5 ;
        RECT  206.46 0 206.484 0.192 ;
    END
  END t0[367]
  PIN t0[368]
    DIRECTION OUTPUT ;
    USE SIGNAL ;
    PORT
      LAYER M5 ;
        RECT  206.7 0 206.724 0.192 ;
    END
  END t0[368]
  PIN t0[369]
    DIRECTION OUTPUT ;
    USE SIGNAL ;
    PORT
      LAYER M5 ;
        RECT  206.988 0 207.012 0.192 ;
    END
  END t0[369]
  PIN t0[36]
    DIRECTION OUTPUT ;
    USE SIGNAL ;
    PORT
      LAYER M5 ;
        RECT  115.548 0 115.572 0.192 ;
    END
  END t0[36]
  PIN t0[370]
    DIRECTION OUTPUT ;
    USE SIGNAL ;
    PORT
      LAYER M5 ;
        RECT  207.276 0 207.3 0.192 ;
    END
  END t0[370]
  PIN t0[371]
    DIRECTION OUTPUT ;
    USE SIGNAL ;
    PORT
      LAYER M5 ;
        RECT  207.516 0 207.54 0.192 ;
    END
  END t0[371]
  PIN t0[372]
    DIRECTION OUTPUT ;
    USE SIGNAL ;
    PORT
      LAYER M5 ;
        RECT  207.804 0 207.828 0.192 ;
    END
  END t0[372]
  PIN t0[373]
    DIRECTION OUTPUT ;
    USE SIGNAL ;
    PORT
      LAYER M5 ;
        RECT  208.092 0 208.116 0.192 ;
    END
  END t0[373]
  PIN t0[374]
    DIRECTION OUTPUT ;
    USE SIGNAL ;
    PORT
      LAYER M5 ;
        RECT  208.38 0 208.404 0.192 ;
    END
  END t0[374]
  PIN t0[375]
    DIRECTION OUTPUT ;
    USE SIGNAL ;
    PORT
      LAYER M5 ;
        RECT  208.62 0 208.644 0.192 ;
    END
  END t0[375]
  PIN t0[376]
    DIRECTION OUTPUT ;
    USE SIGNAL ;
    PORT
      LAYER M5 ;
        RECT  208.908 0 208.932 0.192 ;
    END
  END t0[376]
  PIN t0[377]
    DIRECTION OUTPUT ;
    USE SIGNAL ;
    PORT
      LAYER M5 ;
        RECT  209.196 0 209.22 0.192 ;
    END
  END t0[377]
  PIN t0[378]
    DIRECTION OUTPUT ;
    USE SIGNAL ;
    PORT
      LAYER M5 ;
        RECT  209.436 0 209.46 0.192 ;
    END
  END t0[378]
  PIN t0[379]
    DIRECTION OUTPUT ;
    USE SIGNAL ;
    PORT
      LAYER M5 ;
        RECT  209.724 0 209.748 0.192 ;
    END
  END t0[379]
  PIN t0[37]
    DIRECTION OUTPUT ;
    USE SIGNAL ;
    PORT
      LAYER M5 ;
        RECT  115.836 0 115.86 0.192 ;
    END
  END t0[37]
  PIN t0[380]
    DIRECTION OUTPUT ;
    USE SIGNAL ;
    PORT
      LAYER M5 ;
        RECT  210.012 0 210.036 0.192 ;
    END
  END t0[380]
  PIN t0[381]
    DIRECTION OUTPUT ;
    USE SIGNAL ;
    PORT
      LAYER M5 ;
        RECT  210.3 0 210.324 0.192 ;
    END
  END t0[381]
  PIN t0[382]
    DIRECTION OUTPUT ;
    USE SIGNAL ;
    PORT
      LAYER M5 ;
        RECT  210.54 0 210.564 0.192 ;
    END
  END t0[382]
  PIN t0[383]
    DIRECTION OUTPUT ;
    USE SIGNAL ;
    PORT
      LAYER M5 ;
        RECT  210.828 0 210.852 0.192 ;
    END
  END t0[383]
  PIN t0[384]
    DIRECTION OUTPUT ;
    USE SIGNAL ;
    PORT
      LAYER M5 ;
        RECT  211.116 0 211.14 0.192 ;
    END
  END t0[384]
  PIN t0[385]
    DIRECTION OUTPUT ;
    USE SIGNAL ;
    PORT
      LAYER M5 ;
        RECT  211.356 0 211.38 0.192 ;
    END
  END t0[385]
  PIN t0[386]
    DIRECTION OUTPUT ;
    USE SIGNAL ;
    PORT
      LAYER M5 ;
        RECT  211.644 0 211.668 0.192 ;
    END
  END t0[386]
  PIN t0[387]
    DIRECTION OUTPUT ;
    USE SIGNAL ;
    PORT
      LAYER M5 ;
        RECT  211.932 0 211.956 0.192 ;
    END
  END t0[387]
  PIN t0[388]
    DIRECTION OUTPUT ;
    USE SIGNAL ;
    PORT
      LAYER M5 ;
        RECT  212.22 0 212.244 0.192 ;
    END
  END t0[388]
  PIN t0[389]
    DIRECTION OUTPUT ;
    USE SIGNAL ;
    PORT
      LAYER M5 ;
        RECT  212.46 0 212.484 0.192 ;
    END
  END t0[389]
  PIN t0[38]
    DIRECTION OUTPUT ;
    USE SIGNAL ;
    PORT
      LAYER M5 ;
        RECT  116.076 0 116.1 0.192 ;
    END
  END t0[38]
  PIN t0[390]
    DIRECTION OUTPUT ;
    USE SIGNAL ;
    PORT
      LAYER M5 ;
        RECT  212.748 0 212.772 0.192 ;
    END
  END t0[390]
  PIN t0[391]
    DIRECTION OUTPUT ;
    USE SIGNAL ;
    PORT
      LAYER M5 ;
        RECT  213.036 0 213.06 0.192 ;
    END
  END t0[391]
  PIN t0[392]
    DIRECTION OUTPUT ;
    USE SIGNAL ;
    PORT
      LAYER M5 ;
        RECT  213.324 0 213.348 0.192 ;
    END
  END t0[392]
  PIN t0[393]
    DIRECTION OUTPUT ;
    USE SIGNAL ;
    PORT
      LAYER M5 ;
        RECT  213.564 0 213.588 0.192 ;
    END
  END t0[393]
  PIN t0[394]
    DIRECTION OUTPUT ;
    USE SIGNAL ;
    PORT
      LAYER M5 ;
        RECT  213.852 0 213.876 0.192 ;
    END
  END t0[394]
  PIN t0[39]
    DIRECTION OUTPUT ;
    USE SIGNAL ;
    PORT
      LAYER M5 ;
        RECT  116.364 0 116.388 0.192 ;
    END
  END t0[39]
  PIN t0[3]
    DIRECTION OUTPUT ;
    USE SIGNAL ;
    PORT
      LAYER M5 ;
        RECT  106.476 0 106.5 0.192 ;
    END
  END t0[3]
  PIN t0[40]
    DIRECTION OUTPUT ;
    USE SIGNAL ;
    PORT
      LAYER M5 ;
        RECT  116.652 0 116.676 0.192 ;
    END
  END t0[40]
  PIN t0[41]
    DIRECTION OUTPUT ;
    USE SIGNAL ;
    PORT
      LAYER M5 ;
        RECT  116.892 0 116.916 0.192 ;
    END
  END t0[41]
  PIN t0[42]
    DIRECTION OUTPUT ;
    USE SIGNAL ;
    PORT
      LAYER M5 ;
        RECT  117.18 0 117.204 0.192 ;
    END
  END t0[42]
  PIN t0[43]
    DIRECTION OUTPUT ;
    USE SIGNAL ;
    PORT
      LAYER M5 ;
        RECT  117.468 0 117.492 0.192 ;
    END
  END t0[43]
  PIN t0[44]
    DIRECTION OUTPUT ;
    USE SIGNAL ;
    PORT
      LAYER M5 ;
        RECT  117.756 0 117.78 0.192 ;
    END
  END t0[44]
  PIN t0[45]
    DIRECTION OUTPUT ;
    USE SIGNAL ;
    PORT
      LAYER M5 ;
        RECT  117.996 0 118.02 0.192 ;
    END
  END t0[45]
  PIN t0[46]
    DIRECTION OUTPUT ;
    USE SIGNAL ;
    PORT
      LAYER M5 ;
        RECT  118.284 0 118.308 0.192 ;
    END
  END t0[46]
  PIN t0[47]
    DIRECTION OUTPUT ;
    USE SIGNAL ;
    PORT
      LAYER M5 ;
        RECT  118.572 0 118.596 0.192 ;
    END
  END t0[47]
  PIN t0[48]
    DIRECTION OUTPUT ;
    USE SIGNAL ;
    PORT
      LAYER M5 ;
        RECT  118.812 0 118.836 0.192 ;
    END
  END t0[48]
  PIN t0[49]
    DIRECTION OUTPUT ;
    USE SIGNAL ;
    PORT
      LAYER M5 ;
        RECT  119.1 0 119.124 0.192 ;
    END
  END t0[49]
  PIN t0[4]
    DIRECTION OUTPUT ;
    USE SIGNAL ;
    PORT
      LAYER M5 ;
        RECT  106.764 0 106.788 0.192 ;
    END
  END t0[4]
  PIN t0[50]
    DIRECTION OUTPUT ;
    USE SIGNAL ;
    PORT
      LAYER M5 ;
        RECT  119.388 0 119.412 0.192 ;
    END
  END t0[50]
  PIN t0[51]
    DIRECTION OUTPUT ;
    USE SIGNAL ;
    PORT
      LAYER M5 ;
        RECT  119.676 0 119.7 0.192 ;
    END
  END t0[51]
  PIN t0[52]
    DIRECTION OUTPUT ;
    USE SIGNAL ;
    PORT
      LAYER M5 ;
        RECT  119.916 0 119.94 0.192 ;
    END
  END t0[52]
  PIN t0[53]
    DIRECTION OUTPUT ;
    USE SIGNAL ;
    PORT
      LAYER M5 ;
        RECT  120.204 0 120.228 0.192 ;
    END
  END t0[53]
  PIN t0[54]
    DIRECTION OUTPUT ;
    USE SIGNAL ;
    PORT
      LAYER M5 ;
        RECT  120.492 0 120.516 0.192 ;
    END
  END t0[54]
  PIN t0[55]
    DIRECTION OUTPUT ;
    USE SIGNAL ;
    PORT
      LAYER M5 ;
        RECT  120.78 0 120.804 0.192 ;
    END
  END t0[55]
  PIN t0[56]
    DIRECTION OUTPUT ;
    USE SIGNAL ;
    PORT
      LAYER M5 ;
        RECT  121.02 0 121.044 0.192 ;
    END
  END t0[56]
  PIN t0[57]
    DIRECTION OUTPUT ;
    USE SIGNAL ;
    PORT
      LAYER M5 ;
        RECT  121.308 0 121.332 0.192 ;
    END
  END t0[57]
  PIN t0[58]
    DIRECTION OUTPUT ;
    USE SIGNAL ;
    PORT
      LAYER M5 ;
        RECT  121.596 0 121.62 0.192 ;
    END
  END t0[58]
  PIN t0[59]
    DIRECTION OUTPUT ;
    USE SIGNAL ;
    PORT
      LAYER M5 ;
        RECT  121.836 0 121.86 0.192 ;
    END
  END t0[59]
  PIN t0[5]
    DIRECTION OUTPUT ;
    USE SIGNAL ;
    PORT
      LAYER M5 ;
        RECT  107.004 0 107.028 0.192 ;
    END
  END t0[5]
  PIN t0[60]
    DIRECTION OUTPUT ;
    USE SIGNAL ;
    PORT
      LAYER M5 ;
        RECT  122.124 0 122.148 0.192 ;
    END
  END t0[60]
  PIN t0[61]
    DIRECTION OUTPUT ;
    USE SIGNAL ;
    PORT
      LAYER M5 ;
        RECT  122.412 0 122.436 0.192 ;
    END
  END t0[61]
  PIN t0[62]
    DIRECTION OUTPUT ;
    USE SIGNAL ;
    PORT
      LAYER M5 ;
        RECT  122.7 0 122.724 0.192 ;
    END
  END t0[62]
  PIN t0[63]
    DIRECTION OUTPUT ;
    USE SIGNAL ;
    PORT
      LAYER M5 ;
        RECT  122.94 0 122.964 0.192 ;
    END
  END t0[63]
  PIN t0[64]
    DIRECTION OUTPUT ;
    USE SIGNAL ;
    PORT
      LAYER M5 ;
        RECT  123.228 0 123.252 0.192 ;
    END
  END t0[64]
  PIN t0[65]
    DIRECTION OUTPUT ;
    USE SIGNAL ;
    PORT
      LAYER M5 ;
        RECT  123.516 0 123.54 0.192 ;
    END
  END t0[65]
  PIN t0[66]
    DIRECTION OUTPUT ;
    USE SIGNAL ;
    PORT
      LAYER M5 ;
        RECT  123.756 0 123.78 0.192 ;
    END
  END t0[66]
  PIN t0[67]
    DIRECTION OUTPUT ;
    USE SIGNAL ;
    PORT
      LAYER M5 ;
        RECT  124.044 0 124.068 0.192 ;
    END
  END t0[67]
  PIN t0[68]
    DIRECTION OUTPUT ;
    USE SIGNAL ;
    PORT
      LAYER M5 ;
        RECT  124.332 0 124.356 0.192 ;
    END
  END t0[68]
  PIN t0[69]
    DIRECTION OUTPUT ;
    USE SIGNAL ;
    PORT
      LAYER M5 ;
        RECT  124.62 0 124.644 0.192 ;
    END
  END t0[69]
  PIN t0[6]
    DIRECTION OUTPUT ;
    USE SIGNAL ;
    PORT
      LAYER M5 ;
        RECT  107.292 0 107.316 0.192 ;
    END
  END t0[6]
  PIN t0[70]
    DIRECTION OUTPUT ;
    USE SIGNAL ;
    PORT
      LAYER M5 ;
        RECT  124.86 0 124.884 0.192 ;
    END
  END t0[70]
  PIN t0[71]
    DIRECTION OUTPUT ;
    USE SIGNAL ;
    PORT
      LAYER M5 ;
        RECT  125.148 0 125.172 0.192 ;
    END
  END t0[71]
  PIN t0[72]
    DIRECTION OUTPUT ;
    USE SIGNAL ;
    PORT
      LAYER M5 ;
        RECT  125.436 0 125.46 0.192 ;
    END
  END t0[72]
  PIN t0[73]
    DIRECTION OUTPUT ;
    USE SIGNAL ;
    PORT
      LAYER M5 ;
        RECT  125.724 0 125.748 0.192 ;
    END
  END t0[73]
  PIN t0[74]
    DIRECTION OUTPUT ;
    USE SIGNAL ;
    PORT
      LAYER M5 ;
        RECT  125.964 0 125.988 0.192 ;
    END
  END t0[74]
  PIN t0[75]
    DIRECTION OUTPUT ;
    USE SIGNAL ;
    PORT
      LAYER M5 ;
        RECT  126.252 0 126.276 0.192 ;
    END
  END t0[75]
  PIN t0[76]
    DIRECTION OUTPUT ;
    USE SIGNAL ;
    PORT
      LAYER M5 ;
        RECT  126.54 0 126.564 0.192 ;
    END
  END t0[76]
  PIN t0[77]
    DIRECTION OUTPUT ;
    USE SIGNAL ;
    PORT
      LAYER M5 ;
        RECT  126.78 0 126.804 0.192 ;
    END
  END t0[77]
  PIN t0[78]
    DIRECTION OUTPUT ;
    USE SIGNAL ;
    PORT
      LAYER M5 ;
        RECT  127.068 0 127.092 0.192 ;
    END
  END t0[78]
  PIN t0[79]
    DIRECTION OUTPUT ;
    USE SIGNAL ;
    PORT
      LAYER M5 ;
        RECT  127.356 0 127.38 0.192 ;
    END
  END t0[79]
  PIN t0[7]
    DIRECTION OUTPUT ;
    USE SIGNAL ;
    PORT
      LAYER M5 ;
        RECT  107.58 0 107.604 0.192 ;
    END
  END t0[7]
  PIN t0[80]
    DIRECTION OUTPUT ;
    USE SIGNAL ;
    PORT
      LAYER M5 ;
        RECT  127.644 0 127.668 0.192 ;
    END
  END t0[80]
  PIN t0[81]
    DIRECTION OUTPUT ;
    USE SIGNAL ;
    PORT
      LAYER M5 ;
        RECT  127.884 0 127.908 0.192 ;
    END
  END t0[81]
  PIN t0[82]
    DIRECTION OUTPUT ;
    USE SIGNAL ;
    PORT
      LAYER M5 ;
        RECT  128.172 0 128.196 0.192 ;
    END
  END t0[82]
  PIN t0[83]
    DIRECTION OUTPUT ;
    USE SIGNAL ;
    PORT
      LAYER M5 ;
        RECT  128.46 0 128.484 0.192 ;
    END
  END t0[83]
  PIN t0[84]
    DIRECTION OUTPUT ;
    USE SIGNAL ;
    PORT
      LAYER M5 ;
        RECT  128.7 0 128.724 0.192 ;
    END
  END t0[84]
  PIN t0[85]
    DIRECTION OUTPUT ;
    USE SIGNAL ;
    PORT
      LAYER M5 ;
        RECT  128.988 0 129.012 0.192 ;
    END
  END t0[85]
  PIN t0[86]
    DIRECTION OUTPUT ;
    USE SIGNAL ;
    PORT
      LAYER M5 ;
        RECT  129.276 0 129.3 0.192 ;
    END
  END t0[86]
  PIN t0[87]
    DIRECTION OUTPUT ;
    USE SIGNAL ;
    PORT
      LAYER M5 ;
        RECT  129.564 0 129.588 0.192 ;
    END
  END t0[87]
  PIN t0[88]
    DIRECTION OUTPUT ;
    USE SIGNAL ;
    PORT
      LAYER M5 ;
        RECT  129.804 0 129.828 0.192 ;
    END
  END t0[88]
  PIN t0[89]
    DIRECTION OUTPUT ;
    USE SIGNAL ;
    PORT
      LAYER M5 ;
        RECT  130.092 0 130.116 0.192 ;
    END
  END t0[89]
  PIN t0[8]
    DIRECTION OUTPUT ;
    USE SIGNAL ;
    PORT
      LAYER M5 ;
        RECT  107.868 0 107.892 0.192 ;
    END
  END t0[8]
  PIN t0[90]
    DIRECTION OUTPUT ;
    USE SIGNAL ;
    PORT
      LAYER M5 ;
        RECT  130.38 0 130.404 0.192 ;
    END
  END t0[90]
  PIN t0[91]
    DIRECTION OUTPUT ;
    USE SIGNAL ;
    PORT
      LAYER M5 ;
        RECT  130.62 0 130.644 0.192 ;
    END
  END t0[91]
  PIN t0[92]
    DIRECTION OUTPUT ;
    USE SIGNAL ;
    PORT
      LAYER M5 ;
        RECT  130.908 0 130.932 0.192 ;
    END
  END t0[92]
  PIN t0[93]
    DIRECTION OUTPUT ;
    USE SIGNAL ;
    PORT
      LAYER M5 ;
        RECT  131.196 0 131.22 0.192 ;
    END
  END t0[93]
  PIN t0[94]
    DIRECTION OUTPUT ;
    USE SIGNAL ;
    PORT
      LAYER M5 ;
        RECT  131.484 0 131.508 0.192 ;
    END
  END t0[94]
  PIN t0[95]
    DIRECTION OUTPUT ;
    USE SIGNAL ;
    PORT
      LAYER M5 ;
        RECT  131.724 0 131.748 0.192 ;
    END
  END t0[95]
  PIN t0[96]
    DIRECTION OUTPUT ;
    USE SIGNAL ;
    PORT
      LAYER M5 ;
        RECT  132.012 0 132.036 0.192 ;
    END
  END t0[96]
  PIN t0[97]
    DIRECTION OUTPUT ;
    USE SIGNAL ;
    PORT
      LAYER M5 ;
        RECT  132.3 0 132.324 0.192 ;
    END
  END t0[97]
  PIN t0[98]
    DIRECTION OUTPUT ;
    USE SIGNAL ;
    PORT
      LAYER M5 ;
        RECT  132.588 0 132.612 0.192 ;
    END
  END t0[98]
  PIN t0[99]
    DIRECTION OUTPUT ;
    USE SIGNAL ;
    PORT
      LAYER M5 ;
        RECT  132.828 0 132.852 0.192 ;
    END
  END t0[99]
  PIN t0[9]
    DIRECTION OUTPUT ;
    USE SIGNAL ;
    PORT
      LAYER M5 ;
        RECT  108.108 0 108.132 0.192 ;
    END
  END t0[9]
  PIN VDD
    DIRECTION INOUT ;
    USE POWER ;
    PORT
      LAYER M5 ;
        RECT  209.556 4.311 209.676 168.489 ;
        RECT  205.236 4.311 205.356 168.489 ;
        RECT  200.916 4.311 201.036 168.489 ;
        RECT  196.596 4.311 196.716 168.489 ;
        RECT  192.276 4.311 192.396 168.489 ;
        RECT  187.956 4.311 188.076 168.489 ;
        RECT  183.636 4.311 183.756 168.489 ;
        RECT  179.316 4.311 179.436 168.489 ;
        RECT  174.996 4.311 175.116 168.489 ;
        RECT  170.676 4.311 170.796 168.489 ;
        RECT  166.356 4.311 166.476 168.489 ;
        RECT  162.036 4.311 162.156 168.489 ;
        RECT  157.716 4.311 157.836 168.489 ;
        RECT  153.396 4.311 153.516 168.489 ;
        RECT  149.076 4.311 149.196 168.489 ;
        RECT  144.756 4.311 144.876 168.489 ;
        RECT  140.436 4.311 140.556 168.489 ;
        RECT  136.116 4.311 136.236 168.489 ;
        RECT  131.796 4.311 131.916 168.489 ;
        RECT  127.476 4.311 127.596 168.489 ;
        RECT  123.156 4.311 123.276 168.489 ;
        RECT  118.836 4.311 118.956 168.489 ;
        RECT  114.516 4.311 114.636 168.489 ;
        RECT  110.196 4.311 110.316 168.489 ;
        RECT  105.876 4.311 105.996 168.489 ;
        RECT  101.556 4.311 101.676 168.489 ;
        RECT  97.236 4.311 97.356 168.489 ;
        RECT  92.916 4.311 93.036 168.489 ;
        RECT  88.596 4.311 88.716 168.489 ;
        RECT  84.276 4.311 84.396 168.489 ;
        RECT  79.956 4.311 80.076 168.489 ;
        RECT  75.636 4.311 75.756 168.489 ;
        RECT  71.316 4.311 71.436 168.489 ;
        RECT  66.996 4.311 67.116 168.489 ;
        RECT  62.676 4.311 62.796 168.489 ;
        RECT  58.356 4.311 58.476 168.489 ;
        RECT  54.036 4.311 54.156 168.489 ;
        RECT  49.716 4.311 49.836 168.489 ;
        RECT  45.396 4.311 45.516 168.489 ;
        RECT  41.076 4.311 41.196 168.489 ;
        RECT  36.756 4.311 36.876 168.489 ;
        RECT  32.436 4.311 32.556 168.489 ;
        RECT  28.116 4.311 28.236 168.489 ;
        RECT  23.796 4.311 23.916 168.489 ;
        RECT  19.476 4.311 19.596 168.489 ;
        RECT  15.156 4.311 15.276 168.489 ;
        RECT  10.836 4.311 10.956 168.489 ;
        RECT  6.516 4.311 6.636 168.489 ;
    END
  END VDD
  PIN VSS
    DIRECTION INOUT ;
    USE GROUND ;
    PORT
      LAYER M5 ;
        RECT  209.364 4.297 209.484 168.503 ;
        RECT  205.044 4.297 205.164 168.503 ;
        RECT  200.724 4.297 200.844 168.503 ;
        RECT  196.404 4.297 196.524 168.503 ;
        RECT  192.084 4.297 192.204 168.503 ;
        RECT  187.764 4.297 187.884 168.503 ;
        RECT  183.444 4.297 183.564 168.503 ;
        RECT  179.124 4.297 179.244 168.503 ;
        RECT  174.804 4.297 174.924 168.503 ;
        RECT  170.484 4.297 170.604 168.503 ;
        RECT  166.164 4.297 166.284 168.503 ;
        RECT  161.844 4.297 161.964 168.503 ;
        RECT  157.524 4.297 157.644 168.503 ;
        RECT  153.204 4.297 153.324 168.503 ;
        RECT  148.884 4.297 149.004 168.503 ;
        RECT  144.564 4.297 144.684 168.503 ;
        RECT  140.244 4.297 140.364 168.503 ;
        RECT  135.924 4.297 136.044 168.503 ;
        RECT  131.604 4.297 131.724 168.503 ;
        RECT  127.284 4.297 127.404 168.503 ;
        RECT  122.964 4.297 123.084 168.503 ;
        RECT  118.644 4.297 118.764 168.503 ;
        RECT  114.324 4.297 114.444 168.503 ;
        RECT  110.004 4.297 110.124 168.489 ;
        RECT  105.684 4.297 105.804 168.489 ;
        RECT  101.364 4.297 101.484 168.489 ;
        RECT  97.044 4.297 97.164 168.489 ;
        RECT  92.724 4.297 92.844 168.489 ;
        RECT  88.404 4.297 88.524 168.489 ;
        RECT  84.084 4.297 84.204 168.489 ;
        RECT  79.764 4.297 79.884 168.489 ;
        RECT  75.444 4.297 75.564 168.489 ;
        RECT  71.124 4.297 71.244 168.489 ;
        RECT  66.804 4.297 66.924 168.489 ;
        RECT  62.484 4.297 62.604 168.489 ;
        RECT  58.164 4.297 58.284 168.489 ;
        RECT  53.844 4.297 53.964 168.489 ;
        RECT  49.524 4.297 49.644 168.489 ;
        RECT  45.204 4.297 45.324 168.489 ;
        RECT  40.884 4.297 41.004 168.489 ;
        RECT  36.564 4.297 36.684 168.489 ;
        RECT  32.244 4.297 32.364 168.489 ;
        RECT  27.924 4.297 28.044 168.489 ;
        RECT  23.604 4.297 23.724 168.489 ;
        RECT  19.284 4.297 19.404 168.489 ;
        RECT  14.964 4.297 15.084 168.489 ;
        RECT  10.644 4.297 10.764 168.503 ;
        RECT  6.324 4.297 6.444 168.503 ;
    END
  END VSS
  OBS
    LAYER RVTN ;
     RECT  0 0 216 171.734 ;
    LAYER RVTP ;
     RECT  0 0 216 171.734 ;
    LAYER M1 ;
     RECT  0 0 216 171.734 ;
    LAYER M2 ;
     RECT  0 0 216 171.734 ;
    LAYER M3 ;
     RECT  0 0 216 171.734 ;
    LAYER M4 ;
     RECT  0 0 216 171.734 ;
    LAYER M5 ;
     RECT  0 0 216 171.734 ;
  END
END qkd_ectlk_q0
END LIBRARY
